# Generated by FakeRAM 2.0
VERSION 5.7 ;
BUSBITCHARS "[]" ;
PROPERTYDEFINITIONS
  MACRO width INTEGER ;
  MACRO depth INTEGER ;
  MACRO banks INTEGER ;
END PROPERTYDEFINITIONS
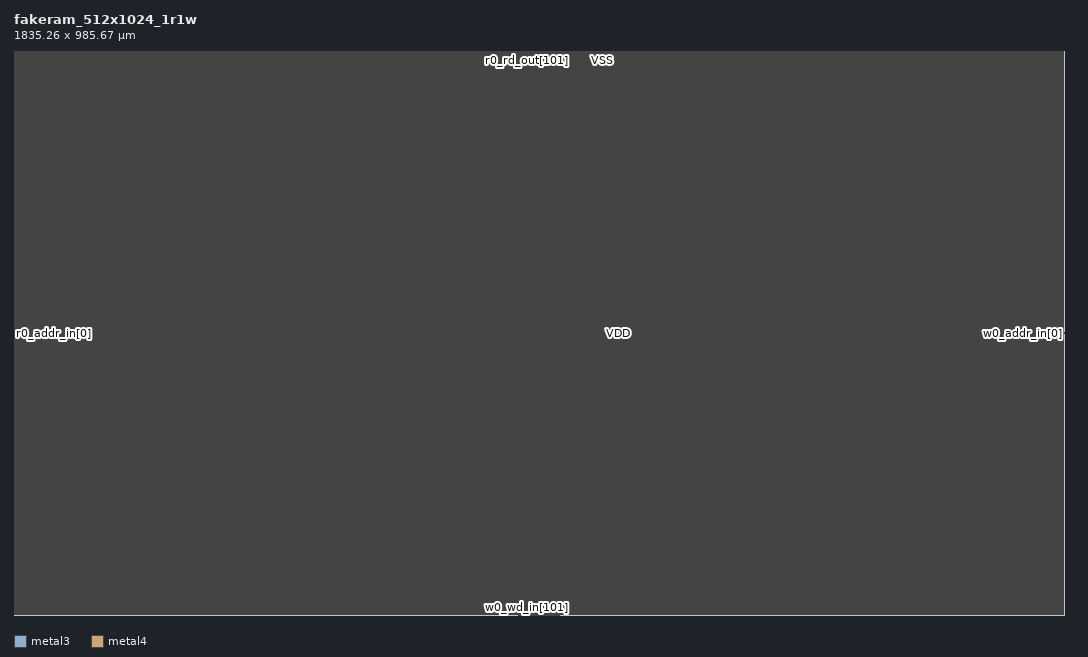
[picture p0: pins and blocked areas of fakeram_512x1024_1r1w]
MACRO fakeram_512x1024_1r1w
  PROPERTY width 512 ;
  PROPERTY depth 1024 ;
  PROPERTY banks 1 ;
  FOREIGN fakeram_512x1024_1r1w 0 0 ;
  SYMMETRY X Y R90 ;
  SIZE 1835.260 BY 985.670 ;
  CLASS BLOCK ;
  PIN r0_addr_in[0]
    DIRECTION INPUT ;
    USE SIGNAL ;
    SHAPE ABUTMENT ;
    PORT
      LAYER metal3 ;
      RECT 0.000 491.820 0.070 491.890 ;
    END
  END r0_addr_in[0]
  PIN r0_addr_in[1]
    DIRECTION INPUT ;
    USE SIGNAL ;
    SHAPE ABUTMENT ;
    PORT
      LAYER metal3 ;
      RECT 0.000 491.960 0.070 492.030 ;
    END
  END r0_addr_in[1]
  PIN r0_addr_in[2]
    DIRECTION INPUT ;
    USE SIGNAL ;
    SHAPE ABUTMENT ;
    PORT
      LAYER metal3 ;
      RECT 0.000 492.100 0.070 492.170 ;
    END
  END r0_addr_in[2]
  PIN r0_addr_in[3]
    DIRECTION INPUT ;
    USE SIGNAL ;
    SHAPE ABUTMENT ;
    PORT
      LAYER metal3 ;
      RECT 0.000 492.240 0.070 492.310 ;
    END
  END r0_addr_in[3]
  PIN r0_addr_in[4]
    DIRECTION INPUT ;
    USE SIGNAL ;
    SHAPE ABUTMENT ;
    PORT
      LAYER metal3 ;
      RECT 0.000 492.380 0.070 492.450 ;
    END
  END r0_addr_in[4]
  PIN r0_addr_in[5]
    DIRECTION INPUT ;
    USE SIGNAL ;
    SHAPE ABUTMENT ;
    PORT
      LAYER metal3 ;
      RECT 0.000 492.520 0.070 492.590 ;
    END
  END r0_addr_in[5]
  PIN r0_addr_in[6]
    DIRECTION INPUT ;
    USE SIGNAL ;
    SHAPE ABUTMENT ;
    PORT
      LAYER metal3 ;
      RECT 0.000 492.660 0.070 492.730 ;
    END
  END r0_addr_in[6]
  PIN r0_addr_in[7]
    DIRECTION INPUT ;
    USE SIGNAL ;
    SHAPE ABUTMENT ;
    PORT
      LAYER metal3 ;
      RECT 0.000 492.800 0.070 492.870 ;
    END
  END r0_addr_in[7]
  PIN r0_addr_in[8]
    DIRECTION INPUT ;
    USE SIGNAL ;
    SHAPE ABUTMENT ;
    PORT
      LAYER metal3 ;
      RECT 0.000 492.940 0.070 493.010 ;
    END
  END r0_addr_in[8]
  PIN r0_addr_in[9]
    DIRECTION INPUT ;
    USE SIGNAL ;
    SHAPE ABUTMENT ;
    PORT
      LAYER metal3 ;
      RECT 0.000 493.080 0.070 493.150 ;
    END
  END r0_addr_in[9]
  PIN r0_ce_in
    DIRECTION INPUT ;
    USE SIGNAL ;
    SHAPE ABUTMENT ;
    PORT
      LAYER metal3 ;
      RECT 0.000 493.360 0.070 493.430 ;
    END
  END r0_ce_in
  PIN r0_clk
    DIRECTION INPUT ;
    USE SIGNAL ;
    SHAPE ABUTMENT ;
    PORT
      LAYER metal3 ;
      RECT 0.000 493.500 0.070 493.570 ;
    END
  END r0_clk
  PIN r0_rd_out[0]
    DIRECTION OUTPUT ;
    USE SIGNAL ;
    SHAPE ABUTMENT ;
    PORT
      LAYER metal3 ;
      RECT 881.685 985.600 881.755 985.670 ;
    END
  END r0_rd_out[0]
  PIN r0_rd_out[1]
    DIRECTION OUTPUT ;
    USE SIGNAL ;
    SHAPE ABUTMENT ;
    PORT
      LAYER metal3 ;
      RECT 881.825 985.600 881.895 985.670 ;
    END
  END r0_rd_out[1]
  PIN r0_rd_out[2]
    DIRECTION OUTPUT ;
    USE SIGNAL ;
    SHAPE ABUTMENT ;
    PORT
      LAYER metal3 ;
      RECT 881.965 985.600 882.035 985.670 ;
    END
  END r0_rd_out[2]
  PIN r0_rd_out[3]
    DIRECTION OUTPUT ;
    USE SIGNAL ;
    SHAPE ABUTMENT ;
    PORT
      LAYER metal3 ;
      RECT 882.105 985.600 882.175 985.670 ;
    END
  END r0_rd_out[3]
  PIN r0_rd_out[4]
    DIRECTION OUTPUT ;
    USE SIGNAL ;
    SHAPE ABUTMENT ;
    PORT
      LAYER metal3 ;
      RECT 882.245 985.600 882.315 985.670 ;
    END
  END r0_rd_out[4]
  PIN r0_rd_out[5]
    DIRECTION OUTPUT ;
    USE SIGNAL ;
    SHAPE ABUTMENT ;
    PORT
      LAYER metal3 ;
      RECT 882.385 985.600 882.455 985.670 ;
    END
  END r0_rd_out[5]
  PIN r0_rd_out[6]
    DIRECTION OUTPUT ;
    USE SIGNAL ;
    SHAPE ABUTMENT ;
    PORT
      LAYER metal3 ;
      RECT 882.525 985.600 882.595 985.670 ;
    END
  END r0_rd_out[6]
  PIN r0_rd_out[7]
    DIRECTION OUTPUT ;
    USE SIGNAL ;
    SHAPE ABUTMENT ;
    PORT
      LAYER metal3 ;
      RECT 882.665 985.600 882.735 985.670 ;
    END
  END r0_rd_out[7]
  PIN r0_rd_out[8]
    DIRECTION OUTPUT ;
    USE SIGNAL ;
    SHAPE ABUTMENT ;
    PORT
      LAYER metal3 ;
      RECT 882.805 985.600 882.875 985.670 ;
    END
  END r0_rd_out[8]
  PIN r0_rd_out[9]
    DIRECTION OUTPUT ;
    USE SIGNAL ;
    SHAPE ABUTMENT ;
    PORT
      LAYER metal3 ;
      RECT 882.945 985.600 883.015 985.670 ;
    END
  END r0_rd_out[9]
  PIN r0_rd_out[10]
    DIRECTION OUTPUT ;
    USE SIGNAL ;
    SHAPE ABUTMENT ;
    PORT
      LAYER metal3 ;
      RECT 883.085 985.600 883.155 985.670 ;
    END
  END r0_rd_out[10]
  PIN r0_rd_out[11]
    DIRECTION OUTPUT ;
    USE SIGNAL ;
    SHAPE ABUTMENT ;
    PORT
      LAYER metal3 ;
      RECT 883.225 985.600 883.295 985.670 ;
    END
  END r0_rd_out[11]
  PIN r0_rd_out[12]
    DIRECTION OUTPUT ;
    USE SIGNAL ;
    SHAPE ABUTMENT ;
    PORT
      LAYER metal3 ;
      RECT 883.365 985.600 883.435 985.670 ;
    END
  END r0_rd_out[12]
  PIN r0_rd_out[13]
    DIRECTION OUTPUT ;
    USE SIGNAL ;
    SHAPE ABUTMENT ;
    PORT
      LAYER metal3 ;
      RECT 883.505 985.600 883.575 985.670 ;
    END
  END r0_rd_out[13]
  PIN r0_rd_out[14]
    DIRECTION OUTPUT ;
    USE SIGNAL ;
    SHAPE ABUTMENT ;
    PORT
      LAYER metal3 ;
      RECT 883.645 985.600 883.715 985.670 ;
    END
  END r0_rd_out[14]
  PIN r0_rd_out[15]
    DIRECTION OUTPUT ;
    USE SIGNAL ;
    SHAPE ABUTMENT ;
    PORT
      LAYER metal3 ;
      RECT 883.785 985.600 883.855 985.670 ;
    END
  END r0_rd_out[15]
  PIN r0_rd_out[16]
    DIRECTION OUTPUT ;
    USE SIGNAL ;
    SHAPE ABUTMENT ;
    PORT
      LAYER metal3 ;
      RECT 883.925 985.600 883.995 985.670 ;
    END
  END r0_rd_out[16]
  PIN r0_rd_out[17]
    DIRECTION OUTPUT ;
    USE SIGNAL ;
    SHAPE ABUTMENT ;
    PORT
      LAYER metal3 ;
      RECT 884.065 985.600 884.135 985.670 ;
    END
  END r0_rd_out[17]
  PIN r0_rd_out[18]
    DIRECTION OUTPUT ;
    USE SIGNAL ;
    SHAPE ABUTMENT ;
    PORT
      LAYER metal3 ;
      RECT 884.205 985.600 884.275 985.670 ;
    END
  END r0_rd_out[18]
  PIN r0_rd_out[19]
    DIRECTION OUTPUT ;
    USE SIGNAL ;
    SHAPE ABUTMENT ;
    PORT
      LAYER metal3 ;
      RECT 884.345 985.600 884.415 985.670 ;
    END
  END r0_rd_out[19]
  PIN r0_rd_out[20]
    DIRECTION OUTPUT ;
    USE SIGNAL ;
    SHAPE ABUTMENT ;
    PORT
      LAYER metal3 ;
      RECT 884.485 985.600 884.555 985.670 ;
    END
  END r0_rd_out[20]
  PIN r0_rd_out[21]
    DIRECTION OUTPUT ;
    USE SIGNAL ;
    SHAPE ABUTMENT ;
    PORT
      LAYER metal3 ;
      RECT 884.625 985.600 884.695 985.670 ;
    END
  END r0_rd_out[21]
  PIN r0_rd_out[22]
    DIRECTION OUTPUT ;
    USE SIGNAL ;
    SHAPE ABUTMENT ;
    PORT
      LAYER metal3 ;
      RECT 884.765 985.600 884.835 985.670 ;
    END
  END r0_rd_out[22]
  PIN r0_rd_out[23]
    DIRECTION OUTPUT ;
    USE SIGNAL ;
    SHAPE ABUTMENT ;
    PORT
      LAYER metal3 ;
      RECT 884.905 985.600 884.975 985.670 ;
    END
  END r0_rd_out[23]
  PIN r0_rd_out[24]
    DIRECTION OUTPUT ;
    USE SIGNAL ;
    SHAPE ABUTMENT ;
    PORT
      LAYER metal3 ;
      RECT 885.045 985.600 885.115 985.670 ;
    END
  END r0_rd_out[24]
  PIN r0_rd_out[25]
    DIRECTION OUTPUT ;
    USE SIGNAL ;
    SHAPE ABUTMENT ;
    PORT
      LAYER metal3 ;
      RECT 885.185 985.600 885.255 985.670 ;
    END
  END r0_rd_out[25]
  PIN r0_rd_out[26]
    DIRECTION OUTPUT ;
    USE SIGNAL ;
    SHAPE ABUTMENT ;
    PORT
      LAYER metal3 ;
      RECT 885.325 985.600 885.395 985.670 ;
    END
  END r0_rd_out[26]
  PIN r0_rd_out[27]
    DIRECTION OUTPUT ;
    USE SIGNAL ;
    SHAPE ABUTMENT ;
    PORT
      LAYER metal3 ;
      RECT 885.465 985.600 885.535 985.670 ;
    END
  END r0_rd_out[27]
  PIN r0_rd_out[28]
    DIRECTION OUTPUT ;
    USE SIGNAL ;
    SHAPE ABUTMENT ;
    PORT
      LAYER metal3 ;
      RECT 885.605 985.600 885.675 985.670 ;
    END
  END r0_rd_out[28]
  PIN r0_rd_out[29]
    DIRECTION OUTPUT ;
    USE SIGNAL ;
    SHAPE ABUTMENT ;
    PORT
      LAYER metal3 ;
      RECT 885.745 985.600 885.815 985.670 ;
    END
  END r0_rd_out[29]
  PIN r0_rd_out[30]
    DIRECTION OUTPUT ;
    USE SIGNAL ;
    SHAPE ABUTMENT ;
    PORT
      LAYER metal3 ;
      RECT 885.885 985.600 885.955 985.670 ;
    END
  END r0_rd_out[30]
  PIN r0_rd_out[31]
    DIRECTION OUTPUT ;
    USE SIGNAL ;
    SHAPE ABUTMENT ;
    PORT
      LAYER metal3 ;
      RECT 886.025 985.600 886.095 985.670 ;
    END
  END r0_rd_out[31]
  PIN r0_rd_out[32]
    DIRECTION OUTPUT ;
    USE SIGNAL ;
    SHAPE ABUTMENT ;
    PORT
      LAYER metal3 ;
      RECT 886.165 985.600 886.235 985.670 ;
    END
  END r0_rd_out[32]
  PIN r0_rd_out[33]
    DIRECTION OUTPUT ;
    USE SIGNAL ;
    SHAPE ABUTMENT ;
    PORT
      LAYER metal3 ;
      RECT 886.305 985.600 886.375 985.670 ;
    END
  END r0_rd_out[33]
  PIN r0_rd_out[34]
    DIRECTION OUTPUT ;
    USE SIGNAL ;
    SHAPE ABUTMENT ;
    PORT
      LAYER metal3 ;
      RECT 886.445 985.600 886.515 985.670 ;
    END
  END r0_rd_out[34]
  PIN r0_rd_out[35]
    DIRECTION OUTPUT ;
    USE SIGNAL ;
    SHAPE ABUTMENT ;
    PORT
      LAYER metal3 ;
      RECT 886.585 985.600 886.655 985.670 ;
    END
  END r0_rd_out[35]
  PIN r0_rd_out[36]
    DIRECTION OUTPUT ;
    USE SIGNAL ;
    SHAPE ABUTMENT ;
    PORT
      LAYER metal3 ;
      RECT 886.725 985.600 886.795 985.670 ;
    END
  END r0_rd_out[36]
  PIN r0_rd_out[37]
    DIRECTION OUTPUT ;
    USE SIGNAL ;
    SHAPE ABUTMENT ;
    PORT
      LAYER metal3 ;
      RECT 886.865 985.600 886.935 985.670 ;
    END
  END r0_rd_out[37]
  PIN r0_rd_out[38]
    DIRECTION OUTPUT ;
    USE SIGNAL ;
    SHAPE ABUTMENT ;
    PORT
      LAYER metal3 ;
      RECT 887.005 985.600 887.075 985.670 ;
    END
  END r0_rd_out[38]
  PIN r0_rd_out[39]
    DIRECTION OUTPUT ;
    USE SIGNAL ;
    SHAPE ABUTMENT ;
    PORT
      LAYER metal3 ;
      RECT 887.145 985.600 887.215 985.670 ;
    END
  END r0_rd_out[39]
  PIN r0_rd_out[40]
    DIRECTION OUTPUT ;
    USE SIGNAL ;
    SHAPE ABUTMENT ;
    PORT
      LAYER metal3 ;
      RECT 887.285 985.600 887.355 985.670 ;
    END
  END r0_rd_out[40]
  PIN r0_rd_out[41]
    DIRECTION OUTPUT ;
    USE SIGNAL ;
    SHAPE ABUTMENT ;
    PORT
      LAYER metal3 ;
      RECT 887.425 985.600 887.495 985.670 ;
    END
  END r0_rd_out[41]
  PIN r0_rd_out[42]
    DIRECTION OUTPUT ;
    USE SIGNAL ;
    SHAPE ABUTMENT ;
    PORT
      LAYER metal3 ;
      RECT 887.565 985.600 887.635 985.670 ;
    END
  END r0_rd_out[42]
  PIN r0_rd_out[43]
    DIRECTION OUTPUT ;
    USE SIGNAL ;
    SHAPE ABUTMENT ;
    PORT
      LAYER metal3 ;
      RECT 887.705 985.600 887.775 985.670 ;
    END
  END r0_rd_out[43]
  PIN r0_rd_out[44]
    DIRECTION OUTPUT ;
    USE SIGNAL ;
    SHAPE ABUTMENT ;
    PORT
      LAYER metal3 ;
      RECT 887.845 985.600 887.915 985.670 ;
    END
  END r0_rd_out[44]
  PIN r0_rd_out[45]
    DIRECTION OUTPUT ;
    USE SIGNAL ;
    SHAPE ABUTMENT ;
    PORT
      LAYER metal3 ;
      RECT 887.985 985.600 888.055 985.670 ;
    END
  END r0_rd_out[45]
  PIN r0_rd_out[46]
    DIRECTION OUTPUT ;
    USE SIGNAL ;
    SHAPE ABUTMENT ;
    PORT
      LAYER metal3 ;
      RECT 888.125 985.600 888.195 985.670 ;
    END
  END r0_rd_out[46]
  PIN r0_rd_out[47]
    DIRECTION OUTPUT ;
    USE SIGNAL ;
    SHAPE ABUTMENT ;
    PORT
      LAYER metal3 ;
      RECT 888.265 985.600 888.335 985.670 ;
    END
  END r0_rd_out[47]
  PIN r0_rd_out[48]
    DIRECTION OUTPUT ;
    USE SIGNAL ;
    SHAPE ABUTMENT ;
    PORT
      LAYER metal3 ;
      RECT 888.405 985.600 888.475 985.670 ;
    END
  END r0_rd_out[48]
  PIN r0_rd_out[49]
    DIRECTION OUTPUT ;
    USE SIGNAL ;
    SHAPE ABUTMENT ;
    PORT
      LAYER metal3 ;
      RECT 888.545 985.600 888.615 985.670 ;
    END
  END r0_rd_out[49]
  PIN r0_rd_out[50]
    DIRECTION OUTPUT ;
    USE SIGNAL ;
    SHAPE ABUTMENT ;
    PORT
      LAYER metal3 ;
      RECT 888.685 985.600 888.755 985.670 ;
    END
  END r0_rd_out[50]
  PIN r0_rd_out[51]
    DIRECTION OUTPUT ;
    USE SIGNAL ;
    SHAPE ABUTMENT ;
    PORT
      LAYER metal3 ;
      RECT 888.825 985.600 888.895 985.670 ;
    END
  END r0_rd_out[51]
  PIN r0_rd_out[52]
    DIRECTION OUTPUT ;
    USE SIGNAL ;
    SHAPE ABUTMENT ;
    PORT
      LAYER metal3 ;
      RECT 888.965 985.600 889.035 985.670 ;
    END
  END r0_rd_out[52]
  PIN r0_rd_out[53]
    DIRECTION OUTPUT ;
    USE SIGNAL ;
    SHAPE ABUTMENT ;
    PORT
      LAYER metal3 ;
      RECT 889.105 985.600 889.175 985.670 ;
    END
  END r0_rd_out[53]
  PIN r0_rd_out[54]
    DIRECTION OUTPUT ;
    USE SIGNAL ;
    SHAPE ABUTMENT ;
    PORT
      LAYER metal3 ;
      RECT 889.245 985.600 889.315 985.670 ;
    END
  END r0_rd_out[54]
  PIN r0_rd_out[55]
    DIRECTION OUTPUT ;
    USE SIGNAL ;
    SHAPE ABUTMENT ;
    PORT
      LAYER metal3 ;
      RECT 889.385 985.600 889.455 985.670 ;
    END
  END r0_rd_out[55]
  PIN r0_rd_out[56]
    DIRECTION OUTPUT ;
    USE SIGNAL ;
    SHAPE ABUTMENT ;
    PORT
      LAYER metal3 ;
      RECT 889.525 985.600 889.595 985.670 ;
    END
  END r0_rd_out[56]
  PIN r0_rd_out[57]
    DIRECTION OUTPUT ;
    USE SIGNAL ;
    SHAPE ABUTMENT ;
    PORT
      LAYER metal3 ;
      RECT 889.665 985.600 889.735 985.670 ;
    END
  END r0_rd_out[57]
  PIN r0_rd_out[58]
    DIRECTION OUTPUT ;
    USE SIGNAL ;
    SHAPE ABUTMENT ;
    PORT
      LAYER metal3 ;
      RECT 889.805 985.600 889.875 985.670 ;
    END
  END r0_rd_out[58]
  PIN r0_rd_out[59]
    DIRECTION OUTPUT ;
    USE SIGNAL ;
    SHAPE ABUTMENT ;
    PORT
      LAYER metal3 ;
      RECT 889.945 985.600 890.015 985.670 ;
    END
  END r0_rd_out[59]
  PIN r0_rd_out[60]
    DIRECTION OUTPUT ;
    USE SIGNAL ;
    SHAPE ABUTMENT ;
    PORT
      LAYER metal3 ;
      RECT 890.085 985.600 890.155 985.670 ;
    END
  END r0_rd_out[60]
  PIN r0_rd_out[61]
    DIRECTION OUTPUT ;
    USE SIGNAL ;
    SHAPE ABUTMENT ;
    PORT
      LAYER metal3 ;
      RECT 890.225 985.600 890.295 985.670 ;
    END
  END r0_rd_out[61]
  PIN r0_rd_out[62]
    DIRECTION OUTPUT ;
    USE SIGNAL ;
    SHAPE ABUTMENT ;
    PORT
      LAYER metal3 ;
      RECT 890.365 985.600 890.435 985.670 ;
    END
  END r0_rd_out[62]
  PIN r0_rd_out[63]
    DIRECTION OUTPUT ;
    USE SIGNAL ;
    SHAPE ABUTMENT ;
    PORT
      LAYER metal3 ;
      RECT 890.505 985.600 890.575 985.670 ;
    END
  END r0_rd_out[63]
  PIN r0_rd_out[64]
    DIRECTION OUTPUT ;
    USE SIGNAL ;
    SHAPE ABUTMENT ;
    PORT
      LAYER metal3 ;
      RECT 890.645 985.600 890.715 985.670 ;
    END
  END r0_rd_out[64]
  PIN r0_rd_out[65]
    DIRECTION OUTPUT ;
    USE SIGNAL ;
    SHAPE ABUTMENT ;
    PORT
      LAYER metal3 ;
      RECT 890.785 985.600 890.855 985.670 ;
    END
  END r0_rd_out[65]
  PIN r0_rd_out[66]
    DIRECTION OUTPUT ;
    USE SIGNAL ;
    SHAPE ABUTMENT ;
    PORT
      LAYER metal3 ;
      RECT 890.925 985.600 890.995 985.670 ;
    END
  END r0_rd_out[66]
  PIN r0_rd_out[67]
    DIRECTION OUTPUT ;
    USE SIGNAL ;
    SHAPE ABUTMENT ;
    PORT
      LAYER metal3 ;
      RECT 891.065 985.600 891.135 985.670 ;
    END
  END r0_rd_out[67]
  PIN r0_rd_out[68]
    DIRECTION OUTPUT ;
    USE SIGNAL ;
    SHAPE ABUTMENT ;
    PORT
      LAYER metal3 ;
      RECT 891.205 985.600 891.275 985.670 ;
    END
  END r0_rd_out[68]
  PIN r0_rd_out[69]
    DIRECTION OUTPUT ;
    USE SIGNAL ;
    SHAPE ABUTMENT ;
    PORT
      LAYER metal3 ;
      RECT 891.345 985.600 891.415 985.670 ;
    END
  END r0_rd_out[69]
  PIN r0_rd_out[70]
    DIRECTION OUTPUT ;
    USE SIGNAL ;
    SHAPE ABUTMENT ;
    PORT
      LAYER metal3 ;
      RECT 891.485 985.600 891.555 985.670 ;
    END
  END r0_rd_out[70]
  PIN r0_rd_out[71]
    DIRECTION OUTPUT ;
    USE SIGNAL ;
    SHAPE ABUTMENT ;
    PORT
      LAYER metal3 ;
      RECT 891.625 985.600 891.695 985.670 ;
    END
  END r0_rd_out[71]
  PIN r0_rd_out[72]
    DIRECTION OUTPUT ;
    USE SIGNAL ;
    SHAPE ABUTMENT ;
    PORT
      LAYER metal3 ;
      RECT 891.765 985.600 891.835 985.670 ;
    END
  END r0_rd_out[72]
  PIN r0_rd_out[73]
    DIRECTION OUTPUT ;
    USE SIGNAL ;
    SHAPE ABUTMENT ;
    PORT
      LAYER metal3 ;
      RECT 891.905 985.600 891.975 985.670 ;
    END
  END r0_rd_out[73]
  PIN r0_rd_out[74]
    DIRECTION OUTPUT ;
    USE SIGNAL ;
    SHAPE ABUTMENT ;
    PORT
      LAYER metal3 ;
      RECT 892.045 985.600 892.115 985.670 ;
    END
  END r0_rd_out[74]
  PIN r0_rd_out[75]
    DIRECTION OUTPUT ;
    USE SIGNAL ;
    SHAPE ABUTMENT ;
    PORT
      LAYER metal3 ;
      RECT 892.185 985.600 892.255 985.670 ;
    END
  END r0_rd_out[75]
  PIN r0_rd_out[76]
    DIRECTION OUTPUT ;
    USE SIGNAL ;
    SHAPE ABUTMENT ;
    PORT
      LAYER metal3 ;
      RECT 892.325 985.600 892.395 985.670 ;
    END
  END r0_rd_out[76]
  PIN r0_rd_out[77]
    DIRECTION OUTPUT ;
    USE SIGNAL ;
    SHAPE ABUTMENT ;
    PORT
      LAYER metal3 ;
      RECT 892.465 985.600 892.535 985.670 ;
    END
  END r0_rd_out[77]
  PIN r0_rd_out[78]
    DIRECTION OUTPUT ;
    USE SIGNAL ;
    SHAPE ABUTMENT ;
    PORT
      LAYER metal3 ;
      RECT 892.605 985.600 892.675 985.670 ;
    END
  END r0_rd_out[78]
  PIN r0_rd_out[79]
    DIRECTION OUTPUT ;
    USE SIGNAL ;
    SHAPE ABUTMENT ;
    PORT
      LAYER metal3 ;
      RECT 892.745 985.600 892.815 985.670 ;
    END
  END r0_rd_out[79]
  PIN r0_rd_out[80]
    DIRECTION OUTPUT ;
    USE SIGNAL ;
    SHAPE ABUTMENT ;
    PORT
      LAYER metal3 ;
      RECT 892.885 985.600 892.955 985.670 ;
    END
  END r0_rd_out[80]
  PIN r0_rd_out[81]
    DIRECTION OUTPUT ;
    USE SIGNAL ;
    SHAPE ABUTMENT ;
    PORT
      LAYER metal3 ;
      RECT 893.025 985.600 893.095 985.670 ;
    END
  END r0_rd_out[81]
  PIN r0_rd_out[82]
    DIRECTION OUTPUT ;
    USE SIGNAL ;
    SHAPE ABUTMENT ;
    PORT
      LAYER metal3 ;
      RECT 893.165 985.600 893.235 985.670 ;
    END
  END r0_rd_out[82]
  PIN r0_rd_out[83]
    DIRECTION OUTPUT ;
    USE SIGNAL ;
    SHAPE ABUTMENT ;
    PORT
      LAYER metal3 ;
      RECT 893.305 985.600 893.375 985.670 ;
    END
  END r0_rd_out[83]
  PIN r0_rd_out[84]
    DIRECTION OUTPUT ;
    USE SIGNAL ;
    SHAPE ABUTMENT ;
    PORT
      LAYER metal3 ;
      RECT 893.445 985.600 893.515 985.670 ;
    END
  END r0_rd_out[84]
  PIN r0_rd_out[85]
    DIRECTION OUTPUT ;
    USE SIGNAL ;
    SHAPE ABUTMENT ;
    PORT
      LAYER metal3 ;
      RECT 893.585 985.600 893.655 985.670 ;
    END
  END r0_rd_out[85]
  PIN r0_rd_out[86]
    DIRECTION OUTPUT ;
    USE SIGNAL ;
    SHAPE ABUTMENT ;
    PORT
      LAYER metal3 ;
      RECT 893.725 985.600 893.795 985.670 ;
    END
  END r0_rd_out[86]
  PIN r0_rd_out[87]
    DIRECTION OUTPUT ;
    USE SIGNAL ;
    SHAPE ABUTMENT ;
    PORT
      LAYER metal3 ;
      RECT 893.865 985.600 893.935 985.670 ;
    END
  END r0_rd_out[87]
  PIN r0_rd_out[88]
    DIRECTION OUTPUT ;
    USE SIGNAL ;
    SHAPE ABUTMENT ;
    PORT
      LAYER metal3 ;
      RECT 894.005 985.600 894.075 985.670 ;
    END
  END r0_rd_out[88]
  PIN r0_rd_out[89]
    DIRECTION OUTPUT ;
    USE SIGNAL ;
    SHAPE ABUTMENT ;
    PORT
      LAYER metal3 ;
      RECT 894.145 985.600 894.215 985.670 ;
    END
  END r0_rd_out[89]
  PIN r0_rd_out[90]
    DIRECTION OUTPUT ;
    USE SIGNAL ;
    SHAPE ABUTMENT ;
    PORT
      LAYER metal3 ;
      RECT 894.285 985.600 894.355 985.670 ;
    END
  END r0_rd_out[90]
  PIN r0_rd_out[91]
    DIRECTION OUTPUT ;
    USE SIGNAL ;
    SHAPE ABUTMENT ;
    PORT
      LAYER metal3 ;
      RECT 894.425 985.600 894.495 985.670 ;
    END
  END r0_rd_out[91]
  PIN r0_rd_out[92]
    DIRECTION OUTPUT ;
    USE SIGNAL ;
    SHAPE ABUTMENT ;
    PORT
      LAYER metal3 ;
      RECT 894.565 985.600 894.635 985.670 ;
    END
  END r0_rd_out[92]
  PIN r0_rd_out[93]
    DIRECTION OUTPUT ;
    USE SIGNAL ;
    SHAPE ABUTMENT ;
    PORT
      LAYER metal3 ;
      RECT 894.705 985.600 894.775 985.670 ;
    END
  END r0_rd_out[93]
  PIN r0_rd_out[94]
    DIRECTION OUTPUT ;
    USE SIGNAL ;
    SHAPE ABUTMENT ;
    PORT
      LAYER metal3 ;
      RECT 894.845 985.600 894.915 985.670 ;
    END
  END r0_rd_out[94]
  PIN r0_rd_out[95]
    DIRECTION OUTPUT ;
    USE SIGNAL ;
    SHAPE ABUTMENT ;
    PORT
      LAYER metal3 ;
      RECT 894.985 985.600 895.055 985.670 ;
    END
  END r0_rd_out[95]
  PIN r0_rd_out[96]
    DIRECTION OUTPUT ;
    USE SIGNAL ;
    SHAPE ABUTMENT ;
    PORT
      LAYER metal3 ;
      RECT 895.125 985.600 895.195 985.670 ;
    END
  END r0_rd_out[96]
  PIN r0_rd_out[97]
    DIRECTION OUTPUT ;
    USE SIGNAL ;
    SHAPE ABUTMENT ;
    PORT
      LAYER metal3 ;
      RECT 895.265 985.600 895.335 985.670 ;
    END
  END r0_rd_out[97]
  PIN r0_rd_out[98]
    DIRECTION OUTPUT ;
    USE SIGNAL ;
    SHAPE ABUTMENT ;
    PORT
      LAYER metal3 ;
      RECT 895.405 985.600 895.475 985.670 ;
    END
  END r0_rd_out[98]
  PIN r0_rd_out[99]
    DIRECTION OUTPUT ;
    USE SIGNAL ;
    SHAPE ABUTMENT ;
    PORT
      LAYER metal3 ;
      RECT 895.545 985.600 895.615 985.670 ;
    END
  END r0_rd_out[99]
  PIN r0_rd_out[100]
    DIRECTION OUTPUT ;
    USE SIGNAL ;
    SHAPE ABUTMENT ;
    PORT
      LAYER metal3 ;
      RECT 895.685 985.600 895.755 985.670 ;
    END
  END r0_rd_out[100]
  PIN r0_rd_out[101]
    DIRECTION OUTPUT ;
    USE SIGNAL ;
    SHAPE ABUTMENT ;
    PORT
      LAYER metal3 ;
      RECT 895.825 985.600 895.895 985.670 ;
    END
  END r0_rd_out[101]
  PIN r0_rd_out[102]
    DIRECTION OUTPUT ;
    USE SIGNAL ;
    SHAPE ABUTMENT ;
    PORT
      LAYER metal3 ;
      RECT 895.965 985.600 896.035 985.670 ;
    END
  END r0_rd_out[102]
  PIN r0_rd_out[103]
    DIRECTION OUTPUT ;
    USE SIGNAL ;
    SHAPE ABUTMENT ;
    PORT
      LAYER metal3 ;
      RECT 896.105 985.600 896.175 985.670 ;
    END
  END r0_rd_out[103]
  PIN r0_rd_out[104]
    DIRECTION OUTPUT ;
    USE SIGNAL ;
    SHAPE ABUTMENT ;
    PORT
      LAYER metal3 ;
      RECT 896.245 985.600 896.315 985.670 ;
    END
  END r0_rd_out[104]
  PIN r0_rd_out[105]
    DIRECTION OUTPUT ;
    USE SIGNAL ;
    SHAPE ABUTMENT ;
    PORT
      LAYER metal3 ;
      RECT 896.385 985.600 896.455 985.670 ;
    END
  END r0_rd_out[105]
  PIN r0_rd_out[106]
    DIRECTION OUTPUT ;
    USE SIGNAL ;
    SHAPE ABUTMENT ;
    PORT
      LAYER metal3 ;
      RECT 896.525 985.600 896.595 985.670 ;
    END
  END r0_rd_out[106]
  PIN r0_rd_out[107]
    DIRECTION OUTPUT ;
    USE SIGNAL ;
    SHAPE ABUTMENT ;
    PORT
      LAYER metal3 ;
      RECT 896.665 985.600 896.735 985.670 ;
    END
  END r0_rd_out[107]
  PIN r0_rd_out[108]
    DIRECTION OUTPUT ;
    USE SIGNAL ;
    SHAPE ABUTMENT ;
    PORT
      LAYER metal3 ;
      RECT 896.805 985.600 896.875 985.670 ;
    END
  END r0_rd_out[108]
  PIN r0_rd_out[109]
    DIRECTION OUTPUT ;
    USE SIGNAL ;
    SHAPE ABUTMENT ;
    PORT
      LAYER metal3 ;
      RECT 896.945 985.600 897.015 985.670 ;
    END
  END r0_rd_out[109]
  PIN r0_rd_out[110]
    DIRECTION OUTPUT ;
    USE SIGNAL ;
    SHAPE ABUTMENT ;
    PORT
      LAYER metal3 ;
      RECT 897.085 985.600 897.155 985.670 ;
    END
  END r0_rd_out[110]
  PIN r0_rd_out[111]
    DIRECTION OUTPUT ;
    USE SIGNAL ;
    SHAPE ABUTMENT ;
    PORT
      LAYER metal3 ;
      RECT 897.225 985.600 897.295 985.670 ;
    END
  END r0_rd_out[111]
  PIN r0_rd_out[112]
    DIRECTION OUTPUT ;
    USE SIGNAL ;
    SHAPE ABUTMENT ;
    PORT
      LAYER metal3 ;
      RECT 897.365 985.600 897.435 985.670 ;
    END
  END r0_rd_out[112]
  PIN r0_rd_out[113]
    DIRECTION OUTPUT ;
    USE SIGNAL ;
    SHAPE ABUTMENT ;
    PORT
      LAYER metal3 ;
      RECT 897.505 985.600 897.575 985.670 ;
    END
  END r0_rd_out[113]
  PIN r0_rd_out[114]
    DIRECTION OUTPUT ;
    USE SIGNAL ;
    SHAPE ABUTMENT ;
    PORT
      LAYER metal3 ;
      RECT 897.645 985.600 897.715 985.670 ;
    END
  END r0_rd_out[114]
  PIN r0_rd_out[115]
    DIRECTION OUTPUT ;
    USE SIGNAL ;
    SHAPE ABUTMENT ;
    PORT
      LAYER metal3 ;
      RECT 897.785 985.600 897.855 985.670 ;
    END
  END r0_rd_out[115]
  PIN r0_rd_out[116]
    DIRECTION OUTPUT ;
    USE SIGNAL ;
    SHAPE ABUTMENT ;
    PORT
      LAYER metal3 ;
      RECT 897.925 985.600 897.995 985.670 ;
    END
  END r0_rd_out[116]
  PIN r0_rd_out[117]
    DIRECTION OUTPUT ;
    USE SIGNAL ;
    SHAPE ABUTMENT ;
    PORT
      LAYER metal3 ;
      RECT 898.065 985.600 898.135 985.670 ;
    END
  END r0_rd_out[117]
  PIN r0_rd_out[118]
    DIRECTION OUTPUT ;
    USE SIGNAL ;
    SHAPE ABUTMENT ;
    PORT
      LAYER metal3 ;
      RECT 898.205 985.600 898.275 985.670 ;
    END
  END r0_rd_out[118]
  PIN r0_rd_out[119]
    DIRECTION OUTPUT ;
    USE SIGNAL ;
    SHAPE ABUTMENT ;
    PORT
      LAYER metal3 ;
      RECT 898.345 985.600 898.415 985.670 ;
    END
  END r0_rd_out[119]
  PIN r0_rd_out[120]
    DIRECTION OUTPUT ;
    USE SIGNAL ;
    SHAPE ABUTMENT ;
    PORT
      LAYER metal3 ;
      RECT 898.485 985.600 898.555 985.670 ;
    END
  END r0_rd_out[120]
  PIN r0_rd_out[121]
    DIRECTION OUTPUT ;
    USE SIGNAL ;
    SHAPE ABUTMENT ;
    PORT
      LAYER metal3 ;
      RECT 898.625 985.600 898.695 985.670 ;
    END
  END r0_rd_out[121]
  PIN r0_rd_out[122]
    DIRECTION OUTPUT ;
    USE SIGNAL ;
    SHAPE ABUTMENT ;
    PORT
      LAYER metal3 ;
      RECT 898.765 985.600 898.835 985.670 ;
    END
  END r0_rd_out[122]
  PIN r0_rd_out[123]
    DIRECTION OUTPUT ;
    USE SIGNAL ;
    SHAPE ABUTMENT ;
    PORT
      LAYER metal3 ;
      RECT 898.905 985.600 898.975 985.670 ;
    END
  END r0_rd_out[123]
  PIN r0_rd_out[124]
    DIRECTION OUTPUT ;
    USE SIGNAL ;
    SHAPE ABUTMENT ;
    PORT
      LAYER metal3 ;
      RECT 899.045 985.600 899.115 985.670 ;
    END
  END r0_rd_out[124]
  PIN r0_rd_out[125]
    DIRECTION OUTPUT ;
    USE SIGNAL ;
    SHAPE ABUTMENT ;
    PORT
      LAYER metal3 ;
      RECT 899.185 985.600 899.255 985.670 ;
    END
  END r0_rd_out[125]
  PIN r0_rd_out[126]
    DIRECTION OUTPUT ;
    USE SIGNAL ;
    SHAPE ABUTMENT ;
    PORT
      LAYER metal3 ;
      RECT 899.325 985.600 899.395 985.670 ;
    END
  END r0_rd_out[126]
  PIN r0_rd_out[127]
    DIRECTION OUTPUT ;
    USE SIGNAL ;
    SHAPE ABUTMENT ;
    PORT
      LAYER metal3 ;
      RECT 899.465 985.600 899.535 985.670 ;
    END
  END r0_rd_out[127]
  PIN r0_rd_out[128]
    DIRECTION OUTPUT ;
    USE SIGNAL ;
    SHAPE ABUTMENT ;
    PORT
      LAYER metal3 ;
      RECT 899.605 985.600 899.675 985.670 ;
    END
  END r0_rd_out[128]
  PIN r0_rd_out[129]
    DIRECTION OUTPUT ;
    USE SIGNAL ;
    SHAPE ABUTMENT ;
    PORT
      LAYER metal3 ;
      RECT 899.745 985.600 899.815 985.670 ;
    END
  END r0_rd_out[129]
  PIN r0_rd_out[130]
    DIRECTION OUTPUT ;
    USE SIGNAL ;
    SHAPE ABUTMENT ;
    PORT
      LAYER metal3 ;
      RECT 899.885 985.600 899.955 985.670 ;
    END
  END r0_rd_out[130]
  PIN r0_rd_out[131]
    DIRECTION OUTPUT ;
    USE SIGNAL ;
    SHAPE ABUTMENT ;
    PORT
      LAYER metal3 ;
      RECT 900.025 985.600 900.095 985.670 ;
    END
  END r0_rd_out[131]
  PIN r0_rd_out[132]
    DIRECTION OUTPUT ;
    USE SIGNAL ;
    SHAPE ABUTMENT ;
    PORT
      LAYER metal3 ;
      RECT 900.165 985.600 900.235 985.670 ;
    END
  END r0_rd_out[132]
  PIN r0_rd_out[133]
    DIRECTION OUTPUT ;
    USE SIGNAL ;
    SHAPE ABUTMENT ;
    PORT
      LAYER metal3 ;
      RECT 900.305 985.600 900.375 985.670 ;
    END
  END r0_rd_out[133]
  PIN r0_rd_out[134]
    DIRECTION OUTPUT ;
    USE SIGNAL ;
    SHAPE ABUTMENT ;
    PORT
      LAYER metal3 ;
      RECT 900.445 985.600 900.515 985.670 ;
    END
  END r0_rd_out[134]
  PIN r0_rd_out[135]
    DIRECTION OUTPUT ;
    USE SIGNAL ;
    SHAPE ABUTMENT ;
    PORT
      LAYER metal3 ;
      RECT 900.585 985.600 900.655 985.670 ;
    END
  END r0_rd_out[135]
  PIN r0_rd_out[136]
    DIRECTION OUTPUT ;
    USE SIGNAL ;
    SHAPE ABUTMENT ;
    PORT
      LAYER metal3 ;
      RECT 900.725 985.600 900.795 985.670 ;
    END
  END r0_rd_out[136]
  PIN r0_rd_out[137]
    DIRECTION OUTPUT ;
    USE SIGNAL ;
    SHAPE ABUTMENT ;
    PORT
      LAYER metal3 ;
      RECT 900.865 985.600 900.935 985.670 ;
    END
  END r0_rd_out[137]
  PIN r0_rd_out[138]
    DIRECTION OUTPUT ;
    USE SIGNAL ;
    SHAPE ABUTMENT ;
    PORT
      LAYER metal3 ;
      RECT 901.005 985.600 901.075 985.670 ;
    END
  END r0_rd_out[138]
  PIN r0_rd_out[139]
    DIRECTION OUTPUT ;
    USE SIGNAL ;
    SHAPE ABUTMENT ;
    PORT
      LAYER metal3 ;
      RECT 901.145 985.600 901.215 985.670 ;
    END
  END r0_rd_out[139]
  PIN r0_rd_out[140]
    DIRECTION OUTPUT ;
    USE SIGNAL ;
    SHAPE ABUTMENT ;
    PORT
      LAYER metal3 ;
      RECT 901.285 985.600 901.355 985.670 ;
    END
  END r0_rd_out[140]
  PIN r0_rd_out[141]
    DIRECTION OUTPUT ;
    USE SIGNAL ;
    SHAPE ABUTMENT ;
    PORT
      LAYER metal3 ;
      RECT 901.425 985.600 901.495 985.670 ;
    END
  END r0_rd_out[141]
  PIN r0_rd_out[142]
    DIRECTION OUTPUT ;
    USE SIGNAL ;
    SHAPE ABUTMENT ;
    PORT
      LAYER metal3 ;
      RECT 901.565 985.600 901.635 985.670 ;
    END
  END r0_rd_out[142]
  PIN r0_rd_out[143]
    DIRECTION OUTPUT ;
    USE SIGNAL ;
    SHAPE ABUTMENT ;
    PORT
      LAYER metal3 ;
      RECT 901.705 985.600 901.775 985.670 ;
    END
  END r0_rd_out[143]
  PIN r0_rd_out[144]
    DIRECTION OUTPUT ;
    USE SIGNAL ;
    SHAPE ABUTMENT ;
    PORT
      LAYER metal3 ;
      RECT 901.845 985.600 901.915 985.670 ;
    END
  END r0_rd_out[144]
  PIN r0_rd_out[145]
    DIRECTION OUTPUT ;
    USE SIGNAL ;
    SHAPE ABUTMENT ;
    PORT
      LAYER metal3 ;
      RECT 901.985 985.600 902.055 985.670 ;
    END
  END r0_rd_out[145]
  PIN r0_rd_out[146]
    DIRECTION OUTPUT ;
    USE SIGNAL ;
    SHAPE ABUTMENT ;
    PORT
      LAYER metal3 ;
      RECT 902.125 985.600 902.195 985.670 ;
    END
  END r0_rd_out[146]
  PIN r0_rd_out[147]
    DIRECTION OUTPUT ;
    USE SIGNAL ;
    SHAPE ABUTMENT ;
    PORT
      LAYER metal3 ;
      RECT 902.265 985.600 902.335 985.670 ;
    END
  END r0_rd_out[147]
  PIN r0_rd_out[148]
    DIRECTION OUTPUT ;
    USE SIGNAL ;
    SHAPE ABUTMENT ;
    PORT
      LAYER metal3 ;
      RECT 902.405 985.600 902.475 985.670 ;
    END
  END r0_rd_out[148]
  PIN r0_rd_out[149]
    DIRECTION OUTPUT ;
    USE SIGNAL ;
    SHAPE ABUTMENT ;
    PORT
      LAYER metal3 ;
      RECT 902.545 985.600 902.615 985.670 ;
    END
  END r0_rd_out[149]
  PIN r0_rd_out[150]
    DIRECTION OUTPUT ;
    USE SIGNAL ;
    SHAPE ABUTMENT ;
    PORT
      LAYER metal3 ;
      RECT 902.685 985.600 902.755 985.670 ;
    END
  END r0_rd_out[150]
  PIN r0_rd_out[151]
    DIRECTION OUTPUT ;
    USE SIGNAL ;
    SHAPE ABUTMENT ;
    PORT
      LAYER metal3 ;
      RECT 902.825 985.600 902.895 985.670 ;
    END
  END r0_rd_out[151]
  PIN r0_rd_out[152]
    DIRECTION OUTPUT ;
    USE SIGNAL ;
    SHAPE ABUTMENT ;
    PORT
      LAYER metal3 ;
      RECT 902.965 985.600 903.035 985.670 ;
    END
  END r0_rd_out[152]
  PIN r0_rd_out[153]
    DIRECTION OUTPUT ;
    USE SIGNAL ;
    SHAPE ABUTMENT ;
    PORT
      LAYER metal3 ;
      RECT 903.105 985.600 903.175 985.670 ;
    END
  END r0_rd_out[153]
  PIN r0_rd_out[154]
    DIRECTION OUTPUT ;
    USE SIGNAL ;
    SHAPE ABUTMENT ;
    PORT
      LAYER metal3 ;
      RECT 903.245 985.600 903.315 985.670 ;
    END
  END r0_rd_out[154]
  PIN r0_rd_out[155]
    DIRECTION OUTPUT ;
    USE SIGNAL ;
    SHAPE ABUTMENT ;
    PORT
      LAYER metal3 ;
      RECT 903.385 985.600 903.455 985.670 ;
    END
  END r0_rd_out[155]
  PIN r0_rd_out[156]
    DIRECTION OUTPUT ;
    USE SIGNAL ;
    SHAPE ABUTMENT ;
    PORT
      LAYER metal3 ;
      RECT 903.525 985.600 903.595 985.670 ;
    END
  END r0_rd_out[156]
  PIN r0_rd_out[157]
    DIRECTION OUTPUT ;
    USE SIGNAL ;
    SHAPE ABUTMENT ;
    PORT
      LAYER metal3 ;
      RECT 903.665 985.600 903.735 985.670 ;
    END
  END r0_rd_out[157]
  PIN r0_rd_out[158]
    DIRECTION OUTPUT ;
    USE SIGNAL ;
    SHAPE ABUTMENT ;
    PORT
      LAYER metal3 ;
      RECT 903.805 985.600 903.875 985.670 ;
    END
  END r0_rd_out[158]
  PIN r0_rd_out[159]
    DIRECTION OUTPUT ;
    USE SIGNAL ;
    SHAPE ABUTMENT ;
    PORT
      LAYER metal3 ;
      RECT 903.945 985.600 904.015 985.670 ;
    END
  END r0_rd_out[159]
  PIN r0_rd_out[160]
    DIRECTION OUTPUT ;
    USE SIGNAL ;
    SHAPE ABUTMENT ;
    PORT
      LAYER metal3 ;
      RECT 904.085 985.600 904.155 985.670 ;
    END
  END r0_rd_out[160]
  PIN r0_rd_out[161]
    DIRECTION OUTPUT ;
    USE SIGNAL ;
    SHAPE ABUTMENT ;
    PORT
      LAYER metal3 ;
      RECT 904.225 985.600 904.295 985.670 ;
    END
  END r0_rd_out[161]
  PIN r0_rd_out[162]
    DIRECTION OUTPUT ;
    USE SIGNAL ;
    SHAPE ABUTMENT ;
    PORT
      LAYER metal3 ;
      RECT 904.365 985.600 904.435 985.670 ;
    END
  END r0_rd_out[162]
  PIN r0_rd_out[163]
    DIRECTION OUTPUT ;
    USE SIGNAL ;
    SHAPE ABUTMENT ;
    PORT
      LAYER metal3 ;
      RECT 904.505 985.600 904.575 985.670 ;
    END
  END r0_rd_out[163]
  PIN r0_rd_out[164]
    DIRECTION OUTPUT ;
    USE SIGNAL ;
    SHAPE ABUTMENT ;
    PORT
      LAYER metal3 ;
      RECT 904.645 985.600 904.715 985.670 ;
    END
  END r0_rd_out[164]
  PIN r0_rd_out[165]
    DIRECTION OUTPUT ;
    USE SIGNAL ;
    SHAPE ABUTMENT ;
    PORT
      LAYER metal3 ;
      RECT 904.785 985.600 904.855 985.670 ;
    END
  END r0_rd_out[165]
  PIN r0_rd_out[166]
    DIRECTION OUTPUT ;
    USE SIGNAL ;
    SHAPE ABUTMENT ;
    PORT
      LAYER metal3 ;
      RECT 904.925 985.600 904.995 985.670 ;
    END
  END r0_rd_out[166]
  PIN r0_rd_out[167]
    DIRECTION OUTPUT ;
    USE SIGNAL ;
    SHAPE ABUTMENT ;
    PORT
      LAYER metal3 ;
      RECT 905.065 985.600 905.135 985.670 ;
    END
  END r0_rd_out[167]
  PIN r0_rd_out[168]
    DIRECTION OUTPUT ;
    USE SIGNAL ;
    SHAPE ABUTMENT ;
    PORT
      LAYER metal3 ;
      RECT 905.205 985.600 905.275 985.670 ;
    END
  END r0_rd_out[168]
  PIN r0_rd_out[169]
    DIRECTION OUTPUT ;
    USE SIGNAL ;
    SHAPE ABUTMENT ;
    PORT
      LAYER metal3 ;
      RECT 905.345 985.600 905.415 985.670 ;
    END
  END r0_rd_out[169]
  PIN r0_rd_out[170]
    DIRECTION OUTPUT ;
    USE SIGNAL ;
    SHAPE ABUTMENT ;
    PORT
      LAYER metal3 ;
      RECT 905.485 985.600 905.555 985.670 ;
    END
  END r0_rd_out[170]
  PIN r0_rd_out[171]
    DIRECTION OUTPUT ;
    USE SIGNAL ;
    SHAPE ABUTMENT ;
    PORT
      LAYER metal3 ;
      RECT 905.625 985.600 905.695 985.670 ;
    END
  END r0_rd_out[171]
  PIN r0_rd_out[172]
    DIRECTION OUTPUT ;
    USE SIGNAL ;
    SHAPE ABUTMENT ;
    PORT
      LAYER metal3 ;
      RECT 905.765 985.600 905.835 985.670 ;
    END
  END r0_rd_out[172]
  PIN r0_rd_out[173]
    DIRECTION OUTPUT ;
    USE SIGNAL ;
    SHAPE ABUTMENT ;
    PORT
      LAYER metal3 ;
      RECT 905.905 985.600 905.975 985.670 ;
    END
  END r0_rd_out[173]
  PIN r0_rd_out[174]
    DIRECTION OUTPUT ;
    USE SIGNAL ;
    SHAPE ABUTMENT ;
    PORT
      LAYER metal3 ;
      RECT 906.045 985.600 906.115 985.670 ;
    END
  END r0_rd_out[174]
  PIN r0_rd_out[175]
    DIRECTION OUTPUT ;
    USE SIGNAL ;
    SHAPE ABUTMENT ;
    PORT
      LAYER metal3 ;
      RECT 906.185 985.600 906.255 985.670 ;
    END
  END r0_rd_out[175]
  PIN r0_rd_out[176]
    DIRECTION OUTPUT ;
    USE SIGNAL ;
    SHAPE ABUTMENT ;
    PORT
      LAYER metal3 ;
      RECT 906.325 985.600 906.395 985.670 ;
    END
  END r0_rd_out[176]
  PIN r0_rd_out[177]
    DIRECTION OUTPUT ;
    USE SIGNAL ;
    SHAPE ABUTMENT ;
    PORT
      LAYER metal3 ;
      RECT 906.465 985.600 906.535 985.670 ;
    END
  END r0_rd_out[177]
  PIN r0_rd_out[178]
    DIRECTION OUTPUT ;
    USE SIGNAL ;
    SHAPE ABUTMENT ;
    PORT
      LAYER metal3 ;
      RECT 906.605 985.600 906.675 985.670 ;
    END
  END r0_rd_out[178]
  PIN r0_rd_out[179]
    DIRECTION OUTPUT ;
    USE SIGNAL ;
    SHAPE ABUTMENT ;
    PORT
      LAYER metal3 ;
      RECT 906.745 985.600 906.815 985.670 ;
    END
  END r0_rd_out[179]
  PIN r0_rd_out[180]
    DIRECTION OUTPUT ;
    USE SIGNAL ;
    SHAPE ABUTMENT ;
    PORT
      LAYER metal3 ;
      RECT 906.885 985.600 906.955 985.670 ;
    END
  END r0_rd_out[180]
  PIN r0_rd_out[181]
    DIRECTION OUTPUT ;
    USE SIGNAL ;
    SHAPE ABUTMENT ;
    PORT
      LAYER metal3 ;
      RECT 907.025 985.600 907.095 985.670 ;
    END
  END r0_rd_out[181]
  PIN r0_rd_out[182]
    DIRECTION OUTPUT ;
    USE SIGNAL ;
    SHAPE ABUTMENT ;
    PORT
      LAYER metal3 ;
      RECT 907.165 985.600 907.235 985.670 ;
    END
  END r0_rd_out[182]
  PIN r0_rd_out[183]
    DIRECTION OUTPUT ;
    USE SIGNAL ;
    SHAPE ABUTMENT ;
    PORT
      LAYER metal3 ;
      RECT 907.305 985.600 907.375 985.670 ;
    END
  END r0_rd_out[183]
  PIN r0_rd_out[184]
    DIRECTION OUTPUT ;
    USE SIGNAL ;
    SHAPE ABUTMENT ;
    PORT
      LAYER metal3 ;
      RECT 907.445 985.600 907.515 985.670 ;
    END
  END r0_rd_out[184]
  PIN r0_rd_out[185]
    DIRECTION OUTPUT ;
    USE SIGNAL ;
    SHAPE ABUTMENT ;
    PORT
      LAYER metal3 ;
      RECT 907.585 985.600 907.655 985.670 ;
    END
  END r0_rd_out[185]
  PIN r0_rd_out[186]
    DIRECTION OUTPUT ;
    USE SIGNAL ;
    SHAPE ABUTMENT ;
    PORT
      LAYER metal3 ;
      RECT 907.725 985.600 907.795 985.670 ;
    END
  END r0_rd_out[186]
  PIN r0_rd_out[187]
    DIRECTION OUTPUT ;
    USE SIGNAL ;
    SHAPE ABUTMENT ;
    PORT
      LAYER metal3 ;
      RECT 907.865 985.600 907.935 985.670 ;
    END
  END r0_rd_out[187]
  PIN r0_rd_out[188]
    DIRECTION OUTPUT ;
    USE SIGNAL ;
    SHAPE ABUTMENT ;
    PORT
      LAYER metal3 ;
      RECT 908.005 985.600 908.075 985.670 ;
    END
  END r0_rd_out[188]
  PIN r0_rd_out[189]
    DIRECTION OUTPUT ;
    USE SIGNAL ;
    SHAPE ABUTMENT ;
    PORT
      LAYER metal3 ;
      RECT 908.145 985.600 908.215 985.670 ;
    END
  END r0_rd_out[189]
  PIN r0_rd_out[190]
    DIRECTION OUTPUT ;
    USE SIGNAL ;
    SHAPE ABUTMENT ;
    PORT
      LAYER metal3 ;
      RECT 908.285 985.600 908.355 985.670 ;
    END
  END r0_rd_out[190]
  PIN r0_rd_out[191]
    DIRECTION OUTPUT ;
    USE SIGNAL ;
    SHAPE ABUTMENT ;
    PORT
      LAYER metal3 ;
      RECT 908.425 985.600 908.495 985.670 ;
    END
  END r0_rd_out[191]
  PIN r0_rd_out[192]
    DIRECTION OUTPUT ;
    USE SIGNAL ;
    SHAPE ABUTMENT ;
    PORT
      LAYER metal3 ;
      RECT 908.565 985.600 908.635 985.670 ;
    END
  END r0_rd_out[192]
  PIN r0_rd_out[193]
    DIRECTION OUTPUT ;
    USE SIGNAL ;
    SHAPE ABUTMENT ;
    PORT
      LAYER metal3 ;
      RECT 908.705 985.600 908.775 985.670 ;
    END
  END r0_rd_out[193]
  PIN r0_rd_out[194]
    DIRECTION OUTPUT ;
    USE SIGNAL ;
    SHAPE ABUTMENT ;
    PORT
      LAYER metal3 ;
      RECT 908.845 985.600 908.915 985.670 ;
    END
  END r0_rd_out[194]
  PIN r0_rd_out[195]
    DIRECTION OUTPUT ;
    USE SIGNAL ;
    SHAPE ABUTMENT ;
    PORT
      LAYER metal3 ;
      RECT 908.985 985.600 909.055 985.670 ;
    END
  END r0_rd_out[195]
  PIN r0_rd_out[196]
    DIRECTION OUTPUT ;
    USE SIGNAL ;
    SHAPE ABUTMENT ;
    PORT
      LAYER metal3 ;
      RECT 909.125 985.600 909.195 985.670 ;
    END
  END r0_rd_out[196]
  PIN r0_rd_out[197]
    DIRECTION OUTPUT ;
    USE SIGNAL ;
    SHAPE ABUTMENT ;
    PORT
      LAYER metal3 ;
      RECT 909.265 985.600 909.335 985.670 ;
    END
  END r0_rd_out[197]
  PIN r0_rd_out[198]
    DIRECTION OUTPUT ;
    USE SIGNAL ;
    SHAPE ABUTMENT ;
    PORT
      LAYER metal3 ;
      RECT 909.405 985.600 909.475 985.670 ;
    END
  END r0_rd_out[198]
  PIN r0_rd_out[199]
    DIRECTION OUTPUT ;
    USE SIGNAL ;
    SHAPE ABUTMENT ;
    PORT
      LAYER metal3 ;
      RECT 909.545 985.600 909.615 985.670 ;
    END
  END r0_rd_out[199]
  PIN r0_rd_out[200]
    DIRECTION OUTPUT ;
    USE SIGNAL ;
    SHAPE ABUTMENT ;
    PORT
      LAYER metal3 ;
      RECT 909.685 985.600 909.755 985.670 ;
    END
  END r0_rd_out[200]
  PIN r0_rd_out[201]
    DIRECTION OUTPUT ;
    USE SIGNAL ;
    SHAPE ABUTMENT ;
    PORT
      LAYER metal3 ;
      RECT 909.825 985.600 909.895 985.670 ;
    END
  END r0_rd_out[201]
  PIN r0_rd_out[202]
    DIRECTION OUTPUT ;
    USE SIGNAL ;
    SHAPE ABUTMENT ;
    PORT
      LAYER metal3 ;
      RECT 909.965 985.600 910.035 985.670 ;
    END
  END r0_rd_out[202]
  PIN r0_rd_out[203]
    DIRECTION OUTPUT ;
    USE SIGNAL ;
    SHAPE ABUTMENT ;
    PORT
      LAYER metal3 ;
      RECT 910.105 985.600 910.175 985.670 ;
    END
  END r0_rd_out[203]
  PIN r0_rd_out[204]
    DIRECTION OUTPUT ;
    USE SIGNAL ;
    SHAPE ABUTMENT ;
    PORT
      LAYER metal3 ;
      RECT 910.245 985.600 910.315 985.670 ;
    END
  END r0_rd_out[204]
  PIN r0_rd_out[205]
    DIRECTION OUTPUT ;
    USE SIGNAL ;
    SHAPE ABUTMENT ;
    PORT
      LAYER metal3 ;
      RECT 910.385 985.600 910.455 985.670 ;
    END
  END r0_rd_out[205]
  PIN r0_rd_out[206]
    DIRECTION OUTPUT ;
    USE SIGNAL ;
    SHAPE ABUTMENT ;
    PORT
      LAYER metal3 ;
      RECT 910.525 985.600 910.595 985.670 ;
    END
  END r0_rd_out[206]
  PIN r0_rd_out[207]
    DIRECTION OUTPUT ;
    USE SIGNAL ;
    SHAPE ABUTMENT ;
    PORT
      LAYER metal3 ;
      RECT 910.665 985.600 910.735 985.670 ;
    END
  END r0_rd_out[207]
  PIN r0_rd_out[208]
    DIRECTION OUTPUT ;
    USE SIGNAL ;
    SHAPE ABUTMENT ;
    PORT
      LAYER metal3 ;
      RECT 910.805 985.600 910.875 985.670 ;
    END
  END r0_rd_out[208]
  PIN r0_rd_out[209]
    DIRECTION OUTPUT ;
    USE SIGNAL ;
    SHAPE ABUTMENT ;
    PORT
      LAYER metal3 ;
      RECT 910.945 985.600 911.015 985.670 ;
    END
  END r0_rd_out[209]
  PIN r0_rd_out[210]
    DIRECTION OUTPUT ;
    USE SIGNAL ;
    SHAPE ABUTMENT ;
    PORT
      LAYER metal3 ;
      RECT 911.085 985.600 911.155 985.670 ;
    END
  END r0_rd_out[210]
  PIN r0_rd_out[211]
    DIRECTION OUTPUT ;
    USE SIGNAL ;
    SHAPE ABUTMENT ;
    PORT
      LAYER metal3 ;
      RECT 911.225 985.600 911.295 985.670 ;
    END
  END r0_rd_out[211]
  PIN r0_rd_out[212]
    DIRECTION OUTPUT ;
    USE SIGNAL ;
    SHAPE ABUTMENT ;
    PORT
      LAYER metal3 ;
      RECT 911.365 985.600 911.435 985.670 ;
    END
  END r0_rd_out[212]
  PIN r0_rd_out[213]
    DIRECTION OUTPUT ;
    USE SIGNAL ;
    SHAPE ABUTMENT ;
    PORT
      LAYER metal3 ;
      RECT 911.505 985.600 911.575 985.670 ;
    END
  END r0_rd_out[213]
  PIN r0_rd_out[214]
    DIRECTION OUTPUT ;
    USE SIGNAL ;
    SHAPE ABUTMENT ;
    PORT
      LAYER metal3 ;
      RECT 911.645 985.600 911.715 985.670 ;
    END
  END r0_rd_out[214]
  PIN r0_rd_out[215]
    DIRECTION OUTPUT ;
    USE SIGNAL ;
    SHAPE ABUTMENT ;
    PORT
      LAYER metal3 ;
      RECT 911.785 985.600 911.855 985.670 ;
    END
  END r0_rd_out[215]
  PIN r0_rd_out[216]
    DIRECTION OUTPUT ;
    USE SIGNAL ;
    SHAPE ABUTMENT ;
    PORT
      LAYER metal3 ;
      RECT 911.925 985.600 911.995 985.670 ;
    END
  END r0_rd_out[216]
  PIN r0_rd_out[217]
    DIRECTION OUTPUT ;
    USE SIGNAL ;
    SHAPE ABUTMENT ;
    PORT
      LAYER metal3 ;
      RECT 912.065 985.600 912.135 985.670 ;
    END
  END r0_rd_out[217]
  PIN r0_rd_out[218]
    DIRECTION OUTPUT ;
    USE SIGNAL ;
    SHAPE ABUTMENT ;
    PORT
      LAYER metal3 ;
      RECT 912.205 985.600 912.275 985.670 ;
    END
  END r0_rd_out[218]
  PIN r0_rd_out[219]
    DIRECTION OUTPUT ;
    USE SIGNAL ;
    SHAPE ABUTMENT ;
    PORT
      LAYER metal3 ;
      RECT 912.345 985.600 912.415 985.670 ;
    END
  END r0_rd_out[219]
  PIN r0_rd_out[220]
    DIRECTION OUTPUT ;
    USE SIGNAL ;
    SHAPE ABUTMENT ;
    PORT
      LAYER metal3 ;
      RECT 912.485 985.600 912.555 985.670 ;
    END
  END r0_rd_out[220]
  PIN r0_rd_out[221]
    DIRECTION OUTPUT ;
    USE SIGNAL ;
    SHAPE ABUTMENT ;
    PORT
      LAYER metal3 ;
      RECT 912.625 985.600 912.695 985.670 ;
    END
  END r0_rd_out[221]
  PIN r0_rd_out[222]
    DIRECTION OUTPUT ;
    USE SIGNAL ;
    SHAPE ABUTMENT ;
    PORT
      LAYER metal3 ;
      RECT 912.765 985.600 912.835 985.670 ;
    END
  END r0_rd_out[222]
  PIN r0_rd_out[223]
    DIRECTION OUTPUT ;
    USE SIGNAL ;
    SHAPE ABUTMENT ;
    PORT
      LAYER metal3 ;
      RECT 912.905 985.600 912.975 985.670 ;
    END
  END r0_rd_out[223]
  PIN r0_rd_out[224]
    DIRECTION OUTPUT ;
    USE SIGNAL ;
    SHAPE ABUTMENT ;
    PORT
      LAYER metal3 ;
      RECT 913.045 985.600 913.115 985.670 ;
    END
  END r0_rd_out[224]
  PIN r0_rd_out[225]
    DIRECTION OUTPUT ;
    USE SIGNAL ;
    SHAPE ABUTMENT ;
    PORT
      LAYER metal3 ;
      RECT 913.185 985.600 913.255 985.670 ;
    END
  END r0_rd_out[225]
  PIN r0_rd_out[226]
    DIRECTION OUTPUT ;
    USE SIGNAL ;
    SHAPE ABUTMENT ;
    PORT
      LAYER metal3 ;
      RECT 913.325 985.600 913.395 985.670 ;
    END
  END r0_rd_out[226]
  PIN r0_rd_out[227]
    DIRECTION OUTPUT ;
    USE SIGNAL ;
    SHAPE ABUTMENT ;
    PORT
      LAYER metal3 ;
      RECT 913.465 985.600 913.535 985.670 ;
    END
  END r0_rd_out[227]
  PIN r0_rd_out[228]
    DIRECTION OUTPUT ;
    USE SIGNAL ;
    SHAPE ABUTMENT ;
    PORT
      LAYER metal3 ;
      RECT 913.605 985.600 913.675 985.670 ;
    END
  END r0_rd_out[228]
  PIN r0_rd_out[229]
    DIRECTION OUTPUT ;
    USE SIGNAL ;
    SHAPE ABUTMENT ;
    PORT
      LAYER metal3 ;
      RECT 913.745 985.600 913.815 985.670 ;
    END
  END r0_rd_out[229]
  PIN r0_rd_out[230]
    DIRECTION OUTPUT ;
    USE SIGNAL ;
    SHAPE ABUTMENT ;
    PORT
      LAYER metal3 ;
      RECT 913.885 985.600 913.955 985.670 ;
    END
  END r0_rd_out[230]
  PIN r0_rd_out[231]
    DIRECTION OUTPUT ;
    USE SIGNAL ;
    SHAPE ABUTMENT ;
    PORT
      LAYER metal3 ;
      RECT 914.025 985.600 914.095 985.670 ;
    END
  END r0_rd_out[231]
  PIN r0_rd_out[232]
    DIRECTION OUTPUT ;
    USE SIGNAL ;
    SHAPE ABUTMENT ;
    PORT
      LAYER metal3 ;
      RECT 914.165 985.600 914.235 985.670 ;
    END
  END r0_rd_out[232]
  PIN r0_rd_out[233]
    DIRECTION OUTPUT ;
    USE SIGNAL ;
    SHAPE ABUTMENT ;
    PORT
      LAYER metal3 ;
      RECT 914.305 985.600 914.375 985.670 ;
    END
  END r0_rd_out[233]
  PIN r0_rd_out[234]
    DIRECTION OUTPUT ;
    USE SIGNAL ;
    SHAPE ABUTMENT ;
    PORT
      LAYER metal3 ;
      RECT 914.445 985.600 914.515 985.670 ;
    END
  END r0_rd_out[234]
  PIN r0_rd_out[235]
    DIRECTION OUTPUT ;
    USE SIGNAL ;
    SHAPE ABUTMENT ;
    PORT
      LAYER metal3 ;
      RECT 914.585 985.600 914.655 985.670 ;
    END
  END r0_rd_out[235]
  PIN r0_rd_out[236]
    DIRECTION OUTPUT ;
    USE SIGNAL ;
    SHAPE ABUTMENT ;
    PORT
      LAYER metal3 ;
      RECT 914.725 985.600 914.795 985.670 ;
    END
  END r0_rd_out[236]
  PIN r0_rd_out[237]
    DIRECTION OUTPUT ;
    USE SIGNAL ;
    SHAPE ABUTMENT ;
    PORT
      LAYER metal3 ;
      RECT 914.865 985.600 914.935 985.670 ;
    END
  END r0_rd_out[237]
  PIN r0_rd_out[238]
    DIRECTION OUTPUT ;
    USE SIGNAL ;
    SHAPE ABUTMENT ;
    PORT
      LAYER metal3 ;
      RECT 915.005 985.600 915.075 985.670 ;
    END
  END r0_rd_out[238]
  PIN r0_rd_out[239]
    DIRECTION OUTPUT ;
    USE SIGNAL ;
    SHAPE ABUTMENT ;
    PORT
      LAYER metal3 ;
      RECT 915.145 985.600 915.215 985.670 ;
    END
  END r0_rd_out[239]
  PIN r0_rd_out[240]
    DIRECTION OUTPUT ;
    USE SIGNAL ;
    SHAPE ABUTMENT ;
    PORT
      LAYER metal3 ;
      RECT 915.285 985.600 915.355 985.670 ;
    END
  END r0_rd_out[240]
  PIN r0_rd_out[241]
    DIRECTION OUTPUT ;
    USE SIGNAL ;
    SHAPE ABUTMENT ;
    PORT
      LAYER metal3 ;
      RECT 915.425 985.600 915.495 985.670 ;
    END
  END r0_rd_out[241]
  PIN r0_rd_out[242]
    DIRECTION OUTPUT ;
    USE SIGNAL ;
    SHAPE ABUTMENT ;
    PORT
      LAYER metal3 ;
      RECT 915.565 985.600 915.635 985.670 ;
    END
  END r0_rd_out[242]
  PIN r0_rd_out[243]
    DIRECTION OUTPUT ;
    USE SIGNAL ;
    SHAPE ABUTMENT ;
    PORT
      LAYER metal3 ;
      RECT 915.705 985.600 915.775 985.670 ;
    END
  END r0_rd_out[243]
  PIN r0_rd_out[244]
    DIRECTION OUTPUT ;
    USE SIGNAL ;
    SHAPE ABUTMENT ;
    PORT
      LAYER metal3 ;
      RECT 915.845 985.600 915.915 985.670 ;
    END
  END r0_rd_out[244]
  PIN r0_rd_out[245]
    DIRECTION OUTPUT ;
    USE SIGNAL ;
    SHAPE ABUTMENT ;
    PORT
      LAYER metal3 ;
      RECT 915.985 985.600 916.055 985.670 ;
    END
  END r0_rd_out[245]
  PIN r0_rd_out[246]
    DIRECTION OUTPUT ;
    USE SIGNAL ;
    SHAPE ABUTMENT ;
    PORT
      LAYER metal3 ;
      RECT 916.125 985.600 916.195 985.670 ;
    END
  END r0_rd_out[246]
  PIN r0_rd_out[247]
    DIRECTION OUTPUT ;
    USE SIGNAL ;
    SHAPE ABUTMENT ;
    PORT
      LAYER metal3 ;
      RECT 916.265 985.600 916.335 985.670 ;
    END
  END r0_rd_out[247]
  PIN r0_rd_out[248]
    DIRECTION OUTPUT ;
    USE SIGNAL ;
    SHAPE ABUTMENT ;
    PORT
      LAYER metal3 ;
      RECT 916.405 985.600 916.475 985.670 ;
    END
  END r0_rd_out[248]
  PIN r0_rd_out[249]
    DIRECTION OUTPUT ;
    USE SIGNAL ;
    SHAPE ABUTMENT ;
    PORT
      LAYER metal3 ;
      RECT 916.545 985.600 916.615 985.670 ;
    END
  END r0_rd_out[249]
  PIN r0_rd_out[250]
    DIRECTION OUTPUT ;
    USE SIGNAL ;
    SHAPE ABUTMENT ;
    PORT
      LAYER metal3 ;
      RECT 916.685 985.600 916.755 985.670 ;
    END
  END r0_rd_out[250]
  PIN r0_rd_out[251]
    DIRECTION OUTPUT ;
    USE SIGNAL ;
    SHAPE ABUTMENT ;
    PORT
      LAYER metal3 ;
      RECT 916.825 985.600 916.895 985.670 ;
    END
  END r0_rd_out[251]
  PIN r0_rd_out[252]
    DIRECTION OUTPUT ;
    USE SIGNAL ;
    SHAPE ABUTMENT ;
    PORT
      LAYER metal3 ;
      RECT 916.965 985.600 917.035 985.670 ;
    END
  END r0_rd_out[252]
  PIN r0_rd_out[253]
    DIRECTION OUTPUT ;
    USE SIGNAL ;
    SHAPE ABUTMENT ;
    PORT
      LAYER metal3 ;
      RECT 917.105 985.600 917.175 985.670 ;
    END
  END r0_rd_out[253]
  PIN r0_rd_out[254]
    DIRECTION OUTPUT ;
    USE SIGNAL ;
    SHAPE ABUTMENT ;
    PORT
      LAYER metal3 ;
      RECT 917.245 985.600 917.315 985.670 ;
    END
  END r0_rd_out[254]
  PIN r0_rd_out[255]
    DIRECTION OUTPUT ;
    USE SIGNAL ;
    SHAPE ABUTMENT ;
    PORT
      LAYER metal3 ;
      RECT 917.385 985.600 917.455 985.670 ;
    END
  END r0_rd_out[255]
  PIN r0_rd_out[256]
    DIRECTION OUTPUT ;
    USE SIGNAL ;
    SHAPE ABUTMENT ;
    PORT
      LAYER metal3 ;
      RECT 917.525 985.600 917.595 985.670 ;
    END
  END r0_rd_out[256]
  PIN r0_rd_out[257]
    DIRECTION OUTPUT ;
    USE SIGNAL ;
    SHAPE ABUTMENT ;
    PORT
      LAYER metal3 ;
      RECT 917.665 985.600 917.735 985.670 ;
    END
  END r0_rd_out[257]
  PIN r0_rd_out[258]
    DIRECTION OUTPUT ;
    USE SIGNAL ;
    SHAPE ABUTMENT ;
    PORT
      LAYER metal3 ;
      RECT 917.805 985.600 917.875 985.670 ;
    END
  END r0_rd_out[258]
  PIN r0_rd_out[259]
    DIRECTION OUTPUT ;
    USE SIGNAL ;
    SHAPE ABUTMENT ;
    PORT
      LAYER metal3 ;
      RECT 917.945 985.600 918.015 985.670 ;
    END
  END r0_rd_out[259]
  PIN r0_rd_out[260]
    DIRECTION OUTPUT ;
    USE SIGNAL ;
    SHAPE ABUTMENT ;
    PORT
      LAYER metal3 ;
      RECT 918.085 985.600 918.155 985.670 ;
    END
  END r0_rd_out[260]
  PIN r0_rd_out[261]
    DIRECTION OUTPUT ;
    USE SIGNAL ;
    SHAPE ABUTMENT ;
    PORT
      LAYER metal3 ;
      RECT 918.225 985.600 918.295 985.670 ;
    END
  END r0_rd_out[261]
  PIN r0_rd_out[262]
    DIRECTION OUTPUT ;
    USE SIGNAL ;
    SHAPE ABUTMENT ;
    PORT
      LAYER metal3 ;
      RECT 918.365 985.600 918.435 985.670 ;
    END
  END r0_rd_out[262]
  PIN r0_rd_out[263]
    DIRECTION OUTPUT ;
    USE SIGNAL ;
    SHAPE ABUTMENT ;
    PORT
      LAYER metal3 ;
      RECT 918.505 985.600 918.575 985.670 ;
    END
  END r0_rd_out[263]
  PIN r0_rd_out[264]
    DIRECTION OUTPUT ;
    USE SIGNAL ;
    SHAPE ABUTMENT ;
    PORT
      LAYER metal3 ;
      RECT 918.645 985.600 918.715 985.670 ;
    END
  END r0_rd_out[264]
  PIN r0_rd_out[265]
    DIRECTION OUTPUT ;
    USE SIGNAL ;
    SHAPE ABUTMENT ;
    PORT
      LAYER metal3 ;
      RECT 918.785 985.600 918.855 985.670 ;
    END
  END r0_rd_out[265]
  PIN r0_rd_out[266]
    DIRECTION OUTPUT ;
    USE SIGNAL ;
    SHAPE ABUTMENT ;
    PORT
      LAYER metal3 ;
      RECT 918.925 985.600 918.995 985.670 ;
    END
  END r0_rd_out[266]
  PIN r0_rd_out[267]
    DIRECTION OUTPUT ;
    USE SIGNAL ;
    SHAPE ABUTMENT ;
    PORT
      LAYER metal3 ;
      RECT 919.065 985.600 919.135 985.670 ;
    END
  END r0_rd_out[267]
  PIN r0_rd_out[268]
    DIRECTION OUTPUT ;
    USE SIGNAL ;
    SHAPE ABUTMENT ;
    PORT
      LAYER metal3 ;
      RECT 919.205 985.600 919.275 985.670 ;
    END
  END r0_rd_out[268]
  PIN r0_rd_out[269]
    DIRECTION OUTPUT ;
    USE SIGNAL ;
    SHAPE ABUTMENT ;
    PORT
      LAYER metal3 ;
      RECT 919.345 985.600 919.415 985.670 ;
    END
  END r0_rd_out[269]
  PIN r0_rd_out[270]
    DIRECTION OUTPUT ;
    USE SIGNAL ;
    SHAPE ABUTMENT ;
    PORT
      LAYER metal3 ;
      RECT 919.485 985.600 919.555 985.670 ;
    END
  END r0_rd_out[270]
  PIN r0_rd_out[271]
    DIRECTION OUTPUT ;
    USE SIGNAL ;
    SHAPE ABUTMENT ;
    PORT
      LAYER metal3 ;
      RECT 919.625 985.600 919.695 985.670 ;
    END
  END r0_rd_out[271]
  PIN r0_rd_out[272]
    DIRECTION OUTPUT ;
    USE SIGNAL ;
    SHAPE ABUTMENT ;
    PORT
      LAYER metal3 ;
      RECT 919.765 985.600 919.835 985.670 ;
    END
  END r0_rd_out[272]
  PIN r0_rd_out[273]
    DIRECTION OUTPUT ;
    USE SIGNAL ;
    SHAPE ABUTMENT ;
    PORT
      LAYER metal3 ;
      RECT 919.905 985.600 919.975 985.670 ;
    END
  END r0_rd_out[273]
  PIN r0_rd_out[274]
    DIRECTION OUTPUT ;
    USE SIGNAL ;
    SHAPE ABUTMENT ;
    PORT
      LAYER metal3 ;
      RECT 920.045 985.600 920.115 985.670 ;
    END
  END r0_rd_out[274]
  PIN r0_rd_out[275]
    DIRECTION OUTPUT ;
    USE SIGNAL ;
    SHAPE ABUTMENT ;
    PORT
      LAYER metal3 ;
      RECT 920.185 985.600 920.255 985.670 ;
    END
  END r0_rd_out[275]
  PIN r0_rd_out[276]
    DIRECTION OUTPUT ;
    USE SIGNAL ;
    SHAPE ABUTMENT ;
    PORT
      LAYER metal3 ;
      RECT 920.325 985.600 920.395 985.670 ;
    END
  END r0_rd_out[276]
  PIN r0_rd_out[277]
    DIRECTION OUTPUT ;
    USE SIGNAL ;
    SHAPE ABUTMENT ;
    PORT
      LAYER metal3 ;
      RECT 920.465 985.600 920.535 985.670 ;
    END
  END r0_rd_out[277]
  PIN r0_rd_out[278]
    DIRECTION OUTPUT ;
    USE SIGNAL ;
    SHAPE ABUTMENT ;
    PORT
      LAYER metal3 ;
      RECT 920.605 985.600 920.675 985.670 ;
    END
  END r0_rd_out[278]
  PIN r0_rd_out[279]
    DIRECTION OUTPUT ;
    USE SIGNAL ;
    SHAPE ABUTMENT ;
    PORT
      LAYER metal3 ;
      RECT 920.745 985.600 920.815 985.670 ;
    END
  END r0_rd_out[279]
  PIN r0_rd_out[280]
    DIRECTION OUTPUT ;
    USE SIGNAL ;
    SHAPE ABUTMENT ;
    PORT
      LAYER metal3 ;
      RECT 920.885 985.600 920.955 985.670 ;
    END
  END r0_rd_out[280]
  PIN r0_rd_out[281]
    DIRECTION OUTPUT ;
    USE SIGNAL ;
    SHAPE ABUTMENT ;
    PORT
      LAYER metal3 ;
      RECT 921.025 985.600 921.095 985.670 ;
    END
  END r0_rd_out[281]
  PIN r0_rd_out[282]
    DIRECTION OUTPUT ;
    USE SIGNAL ;
    SHAPE ABUTMENT ;
    PORT
      LAYER metal3 ;
      RECT 921.165 985.600 921.235 985.670 ;
    END
  END r0_rd_out[282]
  PIN r0_rd_out[283]
    DIRECTION OUTPUT ;
    USE SIGNAL ;
    SHAPE ABUTMENT ;
    PORT
      LAYER metal3 ;
      RECT 921.305 985.600 921.375 985.670 ;
    END
  END r0_rd_out[283]
  PIN r0_rd_out[284]
    DIRECTION OUTPUT ;
    USE SIGNAL ;
    SHAPE ABUTMENT ;
    PORT
      LAYER metal3 ;
      RECT 921.445 985.600 921.515 985.670 ;
    END
  END r0_rd_out[284]
  PIN r0_rd_out[285]
    DIRECTION OUTPUT ;
    USE SIGNAL ;
    SHAPE ABUTMENT ;
    PORT
      LAYER metal3 ;
      RECT 921.585 985.600 921.655 985.670 ;
    END
  END r0_rd_out[285]
  PIN r0_rd_out[286]
    DIRECTION OUTPUT ;
    USE SIGNAL ;
    SHAPE ABUTMENT ;
    PORT
      LAYER metal3 ;
      RECT 921.725 985.600 921.795 985.670 ;
    END
  END r0_rd_out[286]
  PIN r0_rd_out[287]
    DIRECTION OUTPUT ;
    USE SIGNAL ;
    SHAPE ABUTMENT ;
    PORT
      LAYER metal3 ;
      RECT 921.865 985.600 921.935 985.670 ;
    END
  END r0_rd_out[287]
  PIN r0_rd_out[288]
    DIRECTION OUTPUT ;
    USE SIGNAL ;
    SHAPE ABUTMENT ;
    PORT
      LAYER metal3 ;
      RECT 922.005 985.600 922.075 985.670 ;
    END
  END r0_rd_out[288]
  PIN r0_rd_out[289]
    DIRECTION OUTPUT ;
    USE SIGNAL ;
    SHAPE ABUTMENT ;
    PORT
      LAYER metal3 ;
      RECT 922.145 985.600 922.215 985.670 ;
    END
  END r0_rd_out[289]
  PIN r0_rd_out[290]
    DIRECTION OUTPUT ;
    USE SIGNAL ;
    SHAPE ABUTMENT ;
    PORT
      LAYER metal3 ;
      RECT 922.285 985.600 922.355 985.670 ;
    END
  END r0_rd_out[290]
  PIN r0_rd_out[291]
    DIRECTION OUTPUT ;
    USE SIGNAL ;
    SHAPE ABUTMENT ;
    PORT
      LAYER metal3 ;
      RECT 922.425 985.600 922.495 985.670 ;
    END
  END r0_rd_out[291]
  PIN r0_rd_out[292]
    DIRECTION OUTPUT ;
    USE SIGNAL ;
    SHAPE ABUTMENT ;
    PORT
      LAYER metal3 ;
      RECT 922.565 985.600 922.635 985.670 ;
    END
  END r0_rd_out[292]
  PIN r0_rd_out[293]
    DIRECTION OUTPUT ;
    USE SIGNAL ;
    SHAPE ABUTMENT ;
    PORT
      LAYER metal3 ;
      RECT 922.705 985.600 922.775 985.670 ;
    END
  END r0_rd_out[293]
  PIN r0_rd_out[294]
    DIRECTION OUTPUT ;
    USE SIGNAL ;
    SHAPE ABUTMENT ;
    PORT
      LAYER metal3 ;
      RECT 922.845 985.600 922.915 985.670 ;
    END
  END r0_rd_out[294]
  PIN r0_rd_out[295]
    DIRECTION OUTPUT ;
    USE SIGNAL ;
    SHAPE ABUTMENT ;
    PORT
      LAYER metal3 ;
      RECT 922.985 985.600 923.055 985.670 ;
    END
  END r0_rd_out[295]
  PIN r0_rd_out[296]
    DIRECTION OUTPUT ;
    USE SIGNAL ;
    SHAPE ABUTMENT ;
    PORT
      LAYER metal3 ;
      RECT 923.125 985.600 923.195 985.670 ;
    END
  END r0_rd_out[296]
  PIN r0_rd_out[297]
    DIRECTION OUTPUT ;
    USE SIGNAL ;
    SHAPE ABUTMENT ;
    PORT
      LAYER metal3 ;
      RECT 923.265 985.600 923.335 985.670 ;
    END
  END r0_rd_out[297]
  PIN r0_rd_out[298]
    DIRECTION OUTPUT ;
    USE SIGNAL ;
    SHAPE ABUTMENT ;
    PORT
      LAYER metal3 ;
      RECT 923.405 985.600 923.475 985.670 ;
    END
  END r0_rd_out[298]
  PIN r0_rd_out[299]
    DIRECTION OUTPUT ;
    USE SIGNAL ;
    SHAPE ABUTMENT ;
    PORT
      LAYER metal3 ;
      RECT 923.545 985.600 923.615 985.670 ;
    END
  END r0_rd_out[299]
  PIN r0_rd_out[300]
    DIRECTION OUTPUT ;
    USE SIGNAL ;
    SHAPE ABUTMENT ;
    PORT
      LAYER metal3 ;
      RECT 923.685 985.600 923.755 985.670 ;
    END
  END r0_rd_out[300]
  PIN r0_rd_out[301]
    DIRECTION OUTPUT ;
    USE SIGNAL ;
    SHAPE ABUTMENT ;
    PORT
      LAYER metal3 ;
      RECT 923.825 985.600 923.895 985.670 ;
    END
  END r0_rd_out[301]
  PIN r0_rd_out[302]
    DIRECTION OUTPUT ;
    USE SIGNAL ;
    SHAPE ABUTMENT ;
    PORT
      LAYER metal3 ;
      RECT 923.965 985.600 924.035 985.670 ;
    END
  END r0_rd_out[302]
  PIN r0_rd_out[303]
    DIRECTION OUTPUT ;
    USE SIGNAL ;
    SHAPE ABUTMENT ;
    PORT
      LAYER metal3 ;
      RECT 924.105 985.600 924.175 985.670 ;
    END
  END r0_rd_out[303]
  PIN r0_rd_out[304]
    DIRECTION OUTPUT ;
    USE SIGNAL ;
    SHAPE ABUTMENT ;
    PORT
      LAYER metal3 ;
      RECT 924.245 985.600 924.315 985.670 ;
    END
  END r0_rd_out[304]
  PIN r0_rd_out[305]
    DIRECTION OUTPUT ;
    USE SIGNAL ;
    SHAPE ABUTMENT ;
    PORT
      LAYER metal3 ;
      RECT 924.385 985.600 924.455 985.670 ;
    END
  END r0_rd_out[305]
  PIN r0_rd_out[306]
    DIRECTION OUTPUT ;
    USE SIGNAL ;
    SHAPE ABUTMENT ;
    PORT
      LAYER metal3 ;
      RECT 924.525 985.600 924.595 985.670 ;
    END
  END r0_rd_out[306]
  PIN r0_rd_out[307]
    DIRECTION OUTPUT ;
    USE SIGNAL ;
    SHAPE ABUTMENT ;
    PORT
      LAYER metal3 ;
      RECT 924.665 985.600 924.735 985.670 ;
    END
  END r0_rd_out[307]
  PIN r0_rd_out[308]
    DIRECTION OUTPUT ;
    USE SIGNAL ;
    SHAPE ABUTMENT ;
    PORT
      LAYER metal3 ;
      RECT 924.805 985.600 924.875 985.670 ;
    END
  END r0_rd_out[308]
  PIN r0_rd_out[309]
    DIRECTION OUTPUT ;
    USE SIGNAL ;
    SHAPE ABUTMENT ;
    PORT
      LAYER metal3 ;
      RECT 924.945 985.600 925.015 985.670 ;
    END
  END r0_rd_out[309]
  PIN r0_rd_out[310]
    DIRECTION OUTPUT ;
    USE SIGNAL ;
    SHAPE ABUTMENT ;
    PORT
      LAYER metal3 ;
      RECT 925.085 985.600 925.155 985.670 ;
    END
  END r0_rd_out[310]
  PIN r0_rd_out[311]
    DIRECTION OUTPUT ;
    USE SIGNAL ;
    SHAPE ABUTMENT ;
    PORT
      LAYER metal3 ;
      RECT 925.225 985.600 925.295 985.670 ;
    END
  END r0_rd_out[311]
  PIN r0_rd_out[312]
    DIRECTION OUTPUT ;
    USE SIGNAL ;
    SHAPE ABUTMENT ;
    PORT
      LAYER metal3 ;
      RECT 925.365 985.600 925.435 985.670 ;
    END
  END r0_rd_out[312]
  PIN r0_rd_out[313]
    DIRECTION OUTPUT ;
    USE SIGNAL ;
    SHAPE ABUTMENT ;
    PORT
      LAYER metal3 ;
      RECT 925.505 985.600 925.575 985.670 ;
    END
  END r0_rd_out[313]
  PIN r0_rd_out[314]
    DIRECTION OUTPUT ;
    USE SIGNAL ;
    SHAPE ABUTMENT ;
    PORT
      LAYER metal3 ;
      RECT 925.645 985.600 925.715 985.670 ;
    END
  END r0_rd_out[314]
  PIN r0_rd_out[315]
    DIRECTION OUTPUT ;
    USE SIGNAL ;
    SHAPE ABUTMENT ;
    PORT
      LAYER metal3 ;
      RECT 925.785 985.600 925.855 985.670 ;
    END
  END r0_rd_out[315]
  PIN r0_rd_out[316]
    DIRECTION OUTPUT ;
    USE SIGNAL ;
    SHAPE ABUTMENT ;
    PORT
      LAYER metal3 ;
      RECT 925.925 985.600 925.995 985.670 ;
    END
  END r0_rd_out[316]
  PIN r0_rd_out[317]
    DIRECTION OUTPUT ;
    USE SIGNAL ;
    SHAPE ABUTMENT ;
    PORT
      LAYER metal3 ;
      RECT 926.065 985.600 926.135 985.670 ;
    END
  END r0_rd_out[317]
  PIN r0_rd_out[318]
    DIRECTION OUTPUT ;
    USE SIGNAL ;
    SHAPE ABUTMENT ;
    PORT
      LAYER metal3 ;
      RECT 926.205 985.600 926.275 985.670 ;
    END
  END r0_rd_out[318]
  PIN r0_rd_out[319]
    DIRECTION OUTPUT ;
    USE SIGNAL ;
    SHAPE ABUTMENT ;
    PORT
      LAYER metal3 ;
      RECT 926.345 985.600 926.415 985.670 ;
    END
  END r0_rd_out[319]
  PIN r0_rd_out[320]
    DIRECTION OUTPUT ;
    USE SIGNAL ;
    SHAPE ABUTMENT ;
    PORT
      LAYER metal3 ;
      RECT 926.485 985.600 926.555 985.670 ;
    END
  END r0_rd_out[320]
  PIN r0_rd_out[321]
    DIRECTION OUTPUT ;
    USE SIGNAL ;
    SHAPE ABUTMENT ;
    PORT
      LAYER metal3 ;
      RECT 926.625 985.600 926.695 985.670 ;
    END
  END r0_rd_out[321]
  PIN r0_rd_out[322]
    DIRECTION OUTPUT ;
    USE SIGNAL ;
    SHAPE ABUTMENT ;
    PORT
      LAYER metal3 ;
      RECT 926.765 985.600 926.835 985.670 ;
    END
  END r0_rd_out[322]
  PIN r0_rd_out[323]
    DIRECTION OUTPUT ;
    USE SIGNAL ;
    SHAPE ABUTMENT ;
    PORT
      LAYER metal3 ;
      RECT 926.905 985.600 926.975 985.670 ;
    END
  END r0_rd_out[323]
  PIN r0_rd_out[324]
    DIRECTION OUTPUT ;
    USE SIGNAL ;
    SHAPE ABUTMENT ;
    PORT
      LAYER metal3 ;
      RECT 927.045 985.600 927.115 985.670 ;
    END
  END r0_rd_out[324]
  PIN r0_rd_out[325]
    DIRECTION OUTPUT ;
    USE SIGNAL ;
    SHAPE ABUTMENT ;
    PORT
      LAYER metal3 ;
      RECT 927.185 985.600 927.255 985.670 ;
    END
  END r0_rd_out[325]
  PIN r0_rd_out[326]
    DIRECTION OUTPUT ;
    USE SIGNAL ;
    SHAPE ABUTMENT ;
    PORT
      LAYER metal3 ;
      RECT 927.325 985.600 927.395 985.670 ;
    END
  END r0_rd_out[326]
  PIN r0_rd_out[327]
    DIRECTION OUTPUT ;
    USE SIGNAL ;
    SHAPE ABUTMENT ;
    PORT
      LAYER metal3 ;
      RECT 927.465 985.600 927.535 985.670 ;
    END
  END r0_rd_out[327]
  PIN r0_rd_out[328]
    DIRECTION OUTPUT ;
    USE SIGNAL ;
    SHAPE ABUTMENT ;
    PORT
      LAYER metal3 ;
      RECT 927.605 985.600 927.675 985.670 ;
    END
  END r0_rd_out[328]
  PIN r0_rd_out[329]
    DIRECTION OUTPUT ;
    USE SIGNAL ;
    SHAPE ABUTMENT ;
    PORT
      LAYER metal3 ;
      RECT 927.745 985.600 927.815 985.670 ;
    END
  END r0_rd_out[329]
  PIN r0_rd_out[330]
    DIRECTION OUTPUT ;
    USE SIGNAL ;
    SHAPE ABUTMENT ;
    PORT
      LAYER metal3 ;
      RECT 927.885 985.600 927.955 985.670 ;
    END
  END r0_rd_out[330]
  PIN r0_rd_out[331]
    DIRECTION OUTPUT ;
    USE SIGNAL ;
    SHAPE ABUTMENT ;
    PORT
      LAYER metal3 ;
      RECT 928.025 985.600 928.095 985.670 ;
    END
  END r0_rd_out[331]
  PIN r0_rd_out[332]
    DIRECTION OUTPUT ;
    USE SIGNAL ;
    SHAPE ABUTMENT ;
    PORT
      LAYER metal3 ;
      RECT 928.165 985.600 928.235 985.670 ;
    END
  END r0_rd_out[332]
  PIN r0_rd_out[333]
    DIRECTION OUTPUT ;
    USE SIGNAL ;
    SHAPE ABUTMENT ;
    PORT
      LAYER metal3 ;
      RECT 928.305 985.600 928.375 985.670 ;
    END
  END r0_rd_out[333]
  PIN r0_rd_out[334]
    DIRECTION OUTPUT ;
    USE SIGNAL ;
    SHAPE ABUTMENT ;
    PORT
      LAYER metal3 ;
      RECT 928.445 985.600 928.515 985.670 ;
    END
  END r0_rd_out[334]
  PIN r0_rd_out[335]
    DIRECTION OUTPUT ;
    USE SIGNAL ;
    SHAPE ABUTMENT ;
    PORT
      LAYER metal3 ;
      RECT 928.585 985.600 928.655 985.670 ;
    END
  END r0_rd_out[335]
  PIN r0_rd_out[336]
    DIRECTION OUTPUT ;
    USE SIGNAL ;
    SHAPE ABUTMENT ;
    PORT
      LAYER metal3 ;
      RECT 928.725 985.600 928.795 985.670 ;
    END
  END r0_rd_out[336]
  PIN r0_rd_out[337]
    DIRECTION OUTPUT ;
    USE SIGNAL ;
    SHAPE ABUTMENT ;
    PORT
      LAYER metal3 ;
      RECT 928.865 985.600 928.935 985.670 ;
    END
  END r0_rd_out[337]
  PIN r0_rd_out[338]
    DIRECTION OUTPUT ;
    USE SIGNAL ;
    SHAPE ABUTMENT ;
    PORT
      LAYER metal3 ;
      RECT 929.005 985.600 929.075 985.670 ;
    END
  END r0_rd_out[338]
  PIN r0_rd_out[339]
    DIRECTION OUTPUT ;
    USE SIGNAL ;
    SHAPE ABUTMENT ;
    PORT
      LAYER metal3 ;
      RECT 929.145 985.600 929.215 985.670 ;
    END
  END r0_rd_out[339]
  PIN r0_rd_out[340]
    DIRECTION OUTPUT ;
    USE SIGNAL ;
    SHAPE ABUTMENT ;
    PORT
      LAYER metal3 ;
      RECT 929.285 985.600 929.355 985.670 ;
    END
  END r0_rd_out[340]
  PIN r0_rd_out[341]
    DIRECTION OUTPUT ;
    USE SIGNAL ;
    SHAPE ABUTMENT ;
    PORT
      LAYER metal3 ;
      RECT 929.425 985.600 929.495 985.670 ;
    END
  END r0_rd_out[341]
  PIN r0_rd_out[342]
    DIRECTION OUTPUT ;
    USE SIGNAL ;
    SHAPE ABUTMENT ;
    PORT
      LAYER metal3 ;
      RECT 929.565 985.600 929.635 985.670 ;
    END
  END r0_rd_out[342]
  PIN r0_rd_out[343]
    DIRECTION OUTPUT ;
    USE SIGNAL ;
    SHAPE ABUTMENT ;
    PORT
      LAYER metal3 ;
      RECT 929.705 985.600 929.775 985.670 ;
    END
  END r0_rd_out[343]
  PIN r0_rd_out[344]
    DIRECTION OUTPUT ;
    USE SIGNAL ;
    SHAPE ABUTMENT ;
    PORT
      LAYER metal3 ;
      RECT 929.845 985.600 929.915 985.670 ;
    END
  END r0_rd_out[344]
  PIN r0_rd_out[345]
    DIRECTION OUTPUT ;
    USE SIGNAL ;
    SHAPE ABUTMENT ;
    PORT
      LAYER metal3 ;
      RECT 929.985 985.600 930.055 985.670 ;
    END
  END r0_rd_out[345]
  PIN r0_rd_out[346]
    DIRECTION OUTPUT ;
    USE SIGNAL ;
    SHAPE ABUTMENT ;
    PORT
      LAYER metal3 ;
      RECT 930.125 985.600 930.195 985.670 ;
    END
  END r0_rd_out[346]
  PIN r0_rd_out[347]
    DIRECTION OUTPUT ;
    USE SIGNAL ;
    SHAPE ABUTMENT ;
    PORT
      LAYER metal3 ;
      RECT 930.265 985.600 930.335 985.670 ;
    END
  END r0_rd_out[347]
  PIN r0_rd_out[348]
    DIRECTION OUTPUT ;
    USE SIGNAL ;
    SHAPE ABUTMENT ;
    PORT
      LAYER metal3 ;
      RECT 930.405 985.600 930.475 985.670 ;
    END
  END r0_rd_out[348]
  PIN r0_rd_out[349]
    DIRECTION OUTPUT ;
    USE SIGNAL ;
    SHAPE ABUTMENT ;
    PORT
      LAYER metal3 ;
      RECT 930.545 985.600 930.615 985.670 ;
    END
  END r0_rd_out[349]
  PIN r0_rd_out[350]
    DIRECTION OUTPUT ;
    USE SIGNAL ;
    SHAPE ABUTMENT ;
    PORT
      LAYER metal3 ;
      RECT 930.685 985.600 930.755 985.670 ;
    END
  END r0_rd_out[350]
  PIN r0_rd_out[351]
    DIRECTION OUTPUT ;
    USE SIGNAL ;
    SHAPE ABUTMENT ;
    PORT
      LAYER metal3 ;
      RECT 930.825 985.600 930.895 985.670 ;
    END
  END r0_rd_out[351]
  PIN r0_rd_out[352]
    DIRECTION OUTPUT ;
    USE SIGNAL ;
    SHAPE ABUTMENT ;
    PORT
      LAYER metal3 ;
      RECT 930.965 985.600 931.035 985.670 ;
    END
  END r0_rd_out[352]
  PIN r0_rd_out[353]
    DIRECTION OUTPUT ;
    USE SIGNAL ;
    SHAPE ABUTMENT ;
    PORT
      LAYER metal3 ;
      RECT 931.105 985.600 931.175 985.670 ;
    END
  END r0_rd_out[353]
  PIN r0_rd_out[354]
    DIRECTION OUTPUT ;
    USE SIGNAL ;
    SHAPE ABUTMENT ;
    PORT
      LAYER metal3 ;
      RECT 931.245 985.600 931.315 985.670 ;
    END
  END r0_rd_out[354]
  PIN r0_rd_out[355]
    DIRECTION OUTPUT ;
    USE SIGNAL ;
    SHAPE ABUTMENT ;
    PORT
      LAYER metal3 ;
      RECT 931.385 985.600 931.455 985.670 ;
    END
  END r0_rd_out[355]
  PIN r0_rd_out[356]
    DIRECTION OUTPUT ;
    USE SIGNAL ;
    SHAPE ABUTMENT ;
    PORT
      LAYER metal3 ;
      RECT 931.525 985.600 931.595 985.670 ;
    END
  END r0_rd_out[356]
  PIN r0_rd_out[357]
    DIRECTION OUTPUT ;
    USE SIGNAL ;
    SHAPE ABUTMENT ;
    PORT
      LAYER metal3 ;
      RECT 931.665 985.600 931.735 985.670 ;
    END
  END r0_rd_out[357]
  PIN r0_rd_out[358]
    DIRECTION OUTPUT ;
    USE SIGNAL ;
    SHAPE ABUTMENT ;
    PORT
      LAYER metal3 ;
      RECT 931.805 985.600 931.875 985.670 ;
    END
  END r0_rd_out[358]
  PIN r0_rd_out[359]
    DIRECTION OUTPUT ;
    USE SIGNAL ;
    SHAPE ABUTMENT ;
    PORT
      LAYER metal3 ;
      RECT 931.945 985.600 932.015 985.670 ;
    END
  END r0_rd_out[359]
  PIN r0_rd_out[360]
    DIRECTION OUTPUT ;
    USE SIGNAL ;
    SHAPE ABUTMENT ;
    PORT
      LAYER metal3 ;
      RECT 932.085 985.600 932.155 985.670 ;
    END
  END r0_rd_out[360]
  PIN r0_rd_out[361]
    DIRECTION OUTPUT ;
    USE SIGNAL ;
    SHAPE ABUTMENT ;
    PORT
      LAYER metal3 ;
      RECT 932.225 985.600 932.295 985.670 ;
    END
  END r0_rd_out[361]
  PIN r0_rd_out[362]
    DIRECTION OUTPUT ;
    USE SIGNAL ;
    SHAPE ABUTMENT ;
    PORT
      LAYER metal3 ;
      RECT 932.365 985.600 932.435 985.670 ;
    END
  END r0_rd_out[362]
  PIN r0_rd_out[363]
    DIRECTION OUTPUT ;
    USE SIGNAL ;
    SHAPE ABUTMENT ;
    PORT
      LAYER metal3 ;
      RECT 932.505 985.600 932.575 985.670 ;
    END
  END r0_rd_out[363]
  PIN r0_rd_out[364]
    DIRECTION OUTPUT ;
    USE SIGNAL ;
    SHAPE ABUTMENT ;
    PORT
      LAYER metal3 ;
      RECT 932.645 985.600 932.715 985.670 ;
    END
  END r0_rd_out[364]
  PIN r0_rd_out[365]
    DIRECTION OUTPUT ;
    USE SIGNAL ;
    SHAPE ABUTMENT ;
    PORT
      LAYER metal3 ;
      RECT 932.785 985.600 932.855 985.670 ;
    END
  END r0_rd_out[365]
  PIN r0_rd_out[366]
    DIRECTION OUTPUT ;
    USE SIGNAL ;
    SHAPE ABUTMENT ;
    PORT
      LAYER metal3 ;
      RECT 932.925 985.600 932.995 985.670 ;
    END
  END r0_rd_out[366]
  PIN r0_rd_out[367]
    DIRECTION OUTPUT ;
    USE SIGNAL ;
    SHAPE ABUTMENT ;
    PORT
      LAYER metal3 ;
      RECT 933.065 985.600 933.135 985.670 ;
    END
  END r0_rd_out[367]
  PIN r0_rd_out[368]
    DIRECTION OUTPUT ;
    USE SIGNAL ;
    SHAPE ABUTMENT ;
    PORT
      LAYER metal3 ;
      RECT 933.205 985.600 933.275 985.670 ;
    END
  END r0_rd_out[368]
  PIN r0_rd_out[369]
    DIRECTION OUTPUT ;
    USE SIGNAL ;
    SHAPE ABUTMENT ;
    PORT
      LAYER metal3 ;
      RECT 933.345 985.600 933.415 985.670 ;
    END
  END r0_rd_out[369]
  PIN r0_rd_out[370]
    DIRECTION OUTPUT ;
    USE SIGNAL ;
    SHAPE ABUTMENT ;
    PORT
      LAYER metal3 ;
      RECT 933.485 985.600 933.555 985.670 ;
    END
  END r0_rd_out[370]
  PIN r0_rd_out[371]
    DIRECTION OUTPUT ;
    USE SIGNAL ;
    SHAPE ABUTMENT ;
    PORT
      LAYER metal3 ;
      RECT 933.625 985.600 933.695 985.670 ;
    END
  END r0_rd_out[371]
  PIN r0_rd_out[372]
    DIRECTION OUTPUT ;
    USE SIGNAL ;
    SHAPE ABUTMENT ;
    PORT
      LAYER metal3 ;
      RECT 933.765 985.600 933.835 985.670 ;
    END
  END r0_rd_out[372]
  PIN r0_rd_out[373]
    DIRECTION OUTPUT ;
    USE SIGNAL ;
    SHAPE ABUTMENT ;
    PORT
      LAYER metal3 ;
      RECT 933.905 985.600 933.975 985.670 ;
    END
  END r0_rd_out[373]
  PIN r0_rd_out[374]
    DIRECTION OUTPUT ;
    USE SIGNAL ;
    SHAPE ABUTMENT ;
    PORT
      LAYER metal3 ;
      RECT 934.045 985.600 934.115 985.670 ;
    END
  END r0_rd_out[374]
  PIN r0_rd_out[375]
    DIRECTION OUTPUT ;
    USE SIGNAL ;
    SHAPE ABUTMENT ;
    PORT
      LAYER metal3 ;
      RECT 934.185 985.600 934.255 985.670 ;
    END
  END r0_rd_out[375]
  PIN r0_rd_out[376]
    DIRECTION OUTPUT ;
    USE SIGNAL ;
    SHAPE ABUTMENT ;
    PORT
      LAYER metal3 ;
      RECT 934.325 985.600 934.395 985.670 ;
    END
  END r0_rd_out[376]
  PIN r0_rd_out[377]
    DIRECTION OUTPUT ;
    USE SIGNAL ;
    SHAPE ABUTMENT ;
    PORT
      LAYER metal3 ;
      RECT 934.465 985.600 934.535 985.670 ;
    END
  END r0_rd_out[377]
  PIN r0_rd_out[378]
    DIRECTION OUTPUT ;
    USE SIGNAL ;
    SHAPE ABUTMENT ;
    PORT
      LAYER metal3 ;
      RECT 934.605 985.600 934.675 985.670 ;
    END
  END r0_rd_out[378]
  PIN r0_rd_out[379]
    DIRECTION OUTPUT ;
    USE SIGNAL ;
    SHAPE ABUTMENT ;
    PORT
      LAYER metal3 ;
      RECT 934.745 985.600 934.815 985.670 ;
    END
  END r0_rd_out[379]
  PIN r0_rd_out[380]
    DIRECTION OUTPUT ;
    USE SIGNAL ;
    SHAPE ABUTMENT ;
    PORT
      LAYER metal3 ;
      RECT 934.885 985.600 934.955 985.670 ;
    END
  END r0_rd_out[380]
  PIN r0_rd_out[381]
    DIRECTION OUTPUT ;
    USE SIGNAL ;
    SHAPE ABUTMENT ;
    PORT
      LAYER metal3 ;
      RECT 935.025 985.600 935.095 985.670 ;
    END
  END r0_rd_out[381]
  PIN r0_rd_out[382]
    DIRECTION OUTPUT ;
    USE SIGNAL ;
    SHAPE ABUTMENT ;
    PORT
      LAYER metal3 ;
      RECT 935.165 985.600 935.235 985.670 ;
    END
  END r0_rd_out[382]
  PIN r0_rd_out[383]
    DIRECTION OUTPUT ;
    USE SIGNAL ;
    SHAPE ABUTMENT ;
    PORT
      LAYER metal3 ;
      RECT 935.305 985.600 935.375 985.670 ;
    END
  END r0_rd_out[383]
  PIN r0_rd_out[384]
    DIRECTION OUTPUT ;
    USE SIGNAL ;
    SHAPE ABUTMENT ;
    PORT
      LAYER metal3 ;
      RECT 935.445 985.600 935.515 985.670 ;
    END
  END r0_rd_out[384]
  PIN r0_rd_out[385]
    DIRECTION OUTPUT ;
    USE SIGNAL ;
    SHAPE ABUTMENT ;
    PORT
      LAYER metal3 ;
      RECT 935.585 985.600 935.655 985.670 ;
    END
  END r0_rd_out[385]
  PIN r0_rd_out[386]
    DIRECTION OUTPUT ;
    USE SIGNAL ;
    SHAPE ABUTMENT ;
    PORT
      LAYER metal3 ;
      RECT 935.725 985.600 935.795 985.670 ;
    END
  END r0_rd_out[386]
  PIN r0_rd_out[387]
    DIRECTION OUTPUT ;
    USE SIGNAL ;
    SHAPE ABUTMENT ;
    PORT
      LAYER metal3 ;
      RECT 935.865 985.600 935.935 985.670 ;
    END
  END r0_rd_out[387]
  PIN r0_rd_out[388]
    DIRECTION OUTPUT ;
    USE SIGNAL ;
    SHAPE ABUTMENT ;
    PORT
      LAYER metal3 ;
      RECT 936.005 985.600 936.075 985.670 ;
    END
  END r0_rd_out[388]
  PIN r0_rd_out[389]
    DIRECTION OUTPUT ;
    USE SIGNAL ;
    SHAPE ABUTMENT ;
    PORT
      LAYER metal3 ;
      RECT 936.145 985.600 936.215 985.670 ;
    END
  END r0_rd_out[389]
  PIN r0_rd_out[390]
    DIRECTION OUTPUT ;
    USE SIGNAL ;
    SHAPE ABUTMENT ;
    PORT
      LAYER metal3 ;
      RECT 936.285 985.600 936.355 985.670 ;
    END
  END r0_rd_out[390]
  PIN r0_rd_out[391]
    DIRECTION OUTPUT ;
    USE SIGNAL ;
    SHAPE ABUTMENT ;
    PORT
      LAYER metal3 ;
      RECT 936.425 985.600 936.495 985.670 ;
    END
  END r0_rd_out[391]
  PIN r0_rd_out[392]
    DIRECTION OUTPUT ;
    USE SIGNAL ;
    SHAPE ABUTMENT ;
    PORT
      LAYER metal3 ;
      RECT 936.565 985.600 936.635 985.670 ;
    END
  END r0_rd_out[392]
  PIN r0_rd_out[393]
    DIRECTION OUTPUT ;
    USE SIGNAL ;
    SHAPE ABUTMENT ;
    PORT
      LAYER metal3 ;
      RECT 936.705 985.600 936.775 985.670 ;
    END
  END r0_rd_out[393]
  PIN r0_rd_out[394]
    DIRECTION OUTPUT ;
    USE SIGNAL ;
    SHAPE ABUTMENT ;
    PORT
      LAYER metal3 ;
      RECT 936.845 985.600 936.915 985.670 ;
    END
  END r0_rd_out[394]
  PIN r0_rd_out[395]
    DIRECTION OUTPUT ;
    USE SIGNAL ;
    SHAPE ABUTMENT ;
    PORT
      LAYER metal3 ;
      RECT 936.985 985.600 937.055 985.670 ;
    END
  END r0_rd_out[395]
  PIN r0_rd_out[396]
    DIRECTION OUTPUT ;
    USE SIGNAL ;
    SHAPE ABUTMENT ;
    PORT
      LAYER metal3 ;
      RECT 937.125 985.600 937.195 985.670 ;
    END
  END r0_rd_out[396]
  PIN r0_rd_out[397]
    DIRECTION OUTPUT ;
    USE SIGNAL ;
    SHAPE ABUTMENT ;
    PORT
      LAYER metal3 ;
      RECT 937.265 985.600 937.335 985.670 ;
    END
  END r0_rd_out[397]
  PIN r0_rd_out[398]
    DIRECTION OUTPUT ;
    USE SIGNAL ;
    SHAPE ABUTMENT ;
    PORT
      LAYER metal3 ;
      RECT 937.405 985.600 937.475 985.670 ;
    END
  END r0_rd_out[398]
  PIN r0_rd_out[399]
    DIRECTION OUTPUT ;
    USE SIGNAL ;
    SHAPE ABUTMENT ;
    PORT
      LAYER metal3 ;
      RECT 937.545 985.600 937.615 985.670 ;
    END
  END r0_rd_out[399]
  PIN r0_rd_out[400]
    DIRECTION OUTPUT ;
    USE SIGNAL ;
    SHAPE ABUTMENT ;
    PORT
      LAYER metal3 ;
      RECT 937.685 985.600 937.755 985.670 ;
    END
  END r0_rd_out[400]
  PIN r0_rd_out[401]
    DIRECTION OUTPUT ;
    USE SIGNAL ;
    SHAPE ABUTMENT ;
    PORT
      LAYER metal3 ;
      RECT 937.825 985.600 937.895 985.670 ;
    END
  END r0_rd_out[401]
  PIN r0_rd_out[402]
    DIRECTION OUTPUT ;
    USE SIGNAL ;
    SHAPE ABUTMENT ;
    PORT
      LAYER metal3 ;
      RECT 937.965 985.600 938.035 985.670 ;
    END
  END r0_rd_out[402]
  PIN r0_rd_out[403]
    DIRECTION OUTPUT ;
    USE SIGNAL ;
    SHAPE ABUTMENT ;
    PORT
      LAYER metal3 ;
      RECT 938.105 985.600 938.175 985.670 ;
    END
  END r0_rd_out[403]
  PIN r0_rd_out[404]
    DIRECTION OUTPUT ;
    USE SIGNAL ;
    SHAPE ABUTMENT ;
    PORT
      LAYER metal3 ;
      RECT 938.245 985.600 938.315 985.670 ;
    END
  END r0_rd_out[404]
  PIN r0_rd_out[405]
    DIRECTION OUTPUT ;
    USE SIGNAL ;
    SHAPE ABUTMENT ;
    PORT
      LAYER metal3 ;
      RECT 938.385 985.600 938.455 985.670 ;
    END
  END r0_rd_out[405]
  PIN r0_rd_out[406]
    DIRECTION OUTPUT ;
    USE SIGNAL ;
    SHAPE ABUTMENT ;
    PORT
      LAYER metal3 ;
      RECT 938.525 985.600 938.595 985.670 ;
    END
  END r0_rd_out[406]
  PIN r0_rd_out[407]
    DIRECTION OUTPUT ;
    USE SIGNAL ;
    SHAPE ABUTMENT ;
    PORT
      LAYER metal3 ;
      RECT 938.665 985.600 938.735 985.670 ;
    END
  END r0_rd_out[407]
  PIN r0_rd_out[408]
    DIRECTION OUTPUT ;
    USE SIGNAL ;
    SHAPE ABUTMENT ;
    PORT
      LAYER metal3 ;
      RECT 938.805 985.600 938.875 985.670 ;
    END
  END r0_rd_out[408]
  PIN r0_rd_out[409]
    DIRECTION OUTPUT ;
    USE SIGNAL ;
    SHAPE ABUTMENT ;
    PORT
      LAYER metal3 ;
      RECT 938.945 985.600 939.015 985.670 ;
    END
  END r0_rd_out[409]
  PIN r0_rd_out[410]
    DIRECTION OUTPUT ;
    USE SIGNAL ;
    SHAPE ABUTMENT ;
    PORT
      LAYER metal3 ;
      RECT 939.085 985.600 939.155 985.670 ;
    END
  END r0_rd_out[410]
  PIN r0_rd_out[411]
    DIRECTION OUTPUT ;
    USE SIGNAL ;
    SHAPE ABUTMENT ;
    PORT
      LAYER metal3 ;
      RECT 939.225 985.600 939.295 985.670 ;
    END
  END r0_rd_out[411]
  PIN r0_rd_out[412]
    DIRECTION OUTPUT ;
    USE SIGNAL ;
    SHAPE ABUTMENT ;
    PORT
      LAYER metal3 ;
      RECT 939.365 985.600 939.435 985.670 ;
    END
  END r0_rd_out[412]
  PIN r0_rd_out[413]
    DIRECTION OUTPUT ;
    USE SIGNAL ;
    SHAPE ABUTMENT ;
    PORT
      LAYER metal3 ;
      RECT 939.505 985.600 939.575 985.670 ;
    END
  END r0_rd_out[413]
  PIN r0_rd_out[414]
    DIRECTION OUTPUT ;
    USE SIGNAL ;
    SHAPE ABUTMENT ;
    PORT
      LAYER metal3 ;
      RECT 939.645 985.600 939.715 985.670 ;
    END
  END r0_rd_out[414]
  PIN r0_rd_out[415]
    DIRECTION OUTPUT ;
    USE SIGNAL ;
    SHAPE ABUTMENT ;
    PORT
      LAYER metal3 ;
      RECT 939.785 985.600 939.855 985.670 ;
    END
  END r0_rd_out[415]
  PIN r0_rd_out[416]
    DIRECTION OUTPUT ;
    USE SIGNAL ;
    SHAPE ABUTMENT ;
    PORT
      LAYER metal3 ;
      RECT 939.925 985.600 939.995 985.670 ;
    END
  END r0_rd_out[416]
  PIN r0_rd_out[417]
    DIRECTION OUTPUT ;
    USE SIGNAL ;
    SHAPE ABUTMENT ;
    PORT
      LAYER metal3 ;
      RECT 940.065 985.600 940.135 985.670 ;
    END
  END r0_rd_out[417]
  PIN r0_rd_out[418]
    DIRECTION OUTPUT ;
    USE SIGNAL ;
    SHAPE ABUTMENT ;
    PORT
      LAYER metal3 ;
      RECT 940.205 985.600 940.275 985.670 ;
    END
  END r0_rd_out[418]
  PIN r0_rd_out[419]
    DIRECTION OUTPUT ;
    USE SIGNAL ;
    SHAPE ABUTMENT ;
    PORT
      LAYER metal3 ;
      RECT 940.345 985.600 940.415 985.670 ;
    END
  END r0_rd_out[419]
  PIN r0_rd_out[420]
    DIRECTION OUTPUT ;
    USE SIGNAL ;
    SHAPE ABUTMENT ;
    PORT
      LAYER metal3 ;
      RECT 940.485 985.600 940.555 985.670 ;
    END
  END r0_rd_out[420]
  PIN r0_rd_out[421]
    DIRECTION OUTPUT ;
    USE SIGNAL ;
    SHAPE ABUTMENT ;
    PORT
      LAYER metal3 ;
      RECT 940.625 985.600 940.695 985.670 ;
    END
  END r0_rd_out[421]
  PIN r0_rd_out[422]
    DIRECTION OUTPUT ;
    USE SIGNAL ;
    SHAPE ABUTMENT ;
    PORT
      LAYER metal3 ;
      RECT 940.765 985.600 940.835 985.670 ;
    END
  END r0_rd_out[422]
  PIN r0_rd_out[423]
    DIRECTION OUTPUT ;
    USE SIGNAL ;
    SHAPE ABUTMENT ;
    PORT
      LAYER metal3 ;
      RECT 940.905 985.600 940.975 985.670 ;
    END
  END r0_rd_out[423]
  PIN r0_rd_out[424]
    DIRECTION OUTPUT ;
    USE SIGNAL ;
    SHAPE ABUTMENT ;
    PORT
      LAYER metal3 ;
      RECT 941.045 985.600 941.115 985.670 ;
    END
  END r0_rd_out[424]
  PIN r0_rd_out[425]
    DIRECTION OUTPUT ;
    USE SIGNAL ;
    SHAPE ABUTMENT ;
    PORT
      LAYER metal3 ;
      RECT 941.185 985.600 941.255 985.670 ;
    END
  END r0_rd_out[425]
  PIN r0_rd_out[426]
    DIRECTION OUTPUT ;
    USE SIGNAL ;
    SHAPE ABUTMENT ;
    PORT
      LAYER metal3 ;
      RECT 941.325 985.600 941.395 985.670 ;
    END
  END r0_rd_out[426]
  PIN r0_rd_out[427]
    DIRECTION OUTPUT ;
    USE SIGNAL ;
    SHAPE ABUTMENT ;
    PORT
      LAYER metal3 ;
      RECT 941.465 985.600 941.535 985.670 ;
    END
  END r0_rd_out[427]
  PIN r0_rd_out[428]
    DIRECTION OUTPUT ;
    USE SIGNAL ;
    SHAPE ABUTMENT ;
    PORT
      LAYER metal3 ;
      RECT 941.605 985.600 941.675 985.670 ;
    END
  END r0_rd_out[428]
  PIN r0_rd_out[429]
    DIRECTION OUTPUT ;
    USE SIGNAL ;
    SHAPE ABUTMENT ;
    PORT
      LAYER metal3 ;
      RECT 941.745 985.600 941.815 985.670 ;
    END
  END r0_rd_out[429]
  PIN r0_rd_out[430]
    DIRECTION OUTPUT ;
    USE SIGNAL ;
    SHAPE ABUTMENT ;
    PORT
      LAYER metal3 ;
      RECT 941.885 985.600 941.955 985.670 ;
    END
  END r0_rd_out[430]
  PIN r0_rd_out[431]
    DIRECTION OUTPUT ;
    USE SIGNAL ;
    SHAPE ABUTMENT ;
    PORT
      LAYER metal3 ;
      RECT 942.025 985.600 942.095 985.670 ;
    END
  END r0_rd_out[431]
  PIN r0_rd_out[432]
    DIRECTION OUTPUT ;
    USE SIGNAL ;
    SHAPE ABUTMENT ;
    PORT
      LAYER metal3 ;
      RECT 942.165 985.600 942.235 985.670 ;
    END
  END r0_rd_out[432]
  PIN r0_rd_out[433]
    DIRECTION OUTPUT ;
    USE SIGNAL ;
    SHAPE ABUTMENT ;
    PORT
      LAYER metal3 ;
      RECT 942.305 985.600 942.375 985.670 ;
    END
  END r0_rd_out[433]
  PIN r0_rd_out[434]
    DIRECTION OUTPUT ;
    USE SIGNAL ;
    SHAPE ABUTMENT ;
    PORT
      LAYER metal3 ;
      RECT 942.445 985.600 942.515 985.670 ;
    END
  END r0_rd_out[434]
  PIN r0_rd_out[435]
    DIRECTION OUTPUT ;
    USE SIGNAL ;
    SHAPE ABUTMENT ;
    PORT
      LAYER metal3 ;
      RECT 942.585 985.600 942.655 985.670 ;
    END
  END r0_rd_out[435]
  PIN r0_rd_out[436]
    DIRECTION OUTPUT ;
    USE SIGNAL ;
    SHAPE ABUTMENT ;
    PORT
      LAYER metal3 ;
      RECT 942.725 985.600 942.795 985.670 ;
    END
  END r0_rd_out[436]
  PIN r0_rd_out[437]
    DIRECTION OUTPUT ;
    USE SIGNAL ;
    SHAPE ABUTMENT ;
    PORT
      LAYER metal3 ;
      RECT 942.865 985.600 942.935 985.670 ;
    END
  END r0_rd_out[437]
  PIN r0_rd_out[438]
    DIRECTION OUTPUT ;
    USE SIGNAL ;
    SHAPE ABUTMENT ;
    PORT
      LAYER metal3 ;
      RECT 943.005 985.600 943.075 985.670 ;
    END
  END r0_rd_out[438]
  PIN r0_rd_out[439]
    DIRECTION OUTPUT ;
    USE SIGNAL ;
    SHAPE ABUTMENT ;
    PORT
      LAYER metal3 ;
      RECT 943.145 985.600 943.215 985.670 ;
    END
  END r0_rd_out[439]
  PIN r0_rd_out[440]
    DIRECTION OUTPUT ;
    USE SIGNAL ;
    SHAPE ABUTMENT ;
    PORT
      LAYER metal3 ;
      RECT 943.285 985.600 943.355 985.670 ;
    END
  END r0_rd_out[440]
  PIN r0_rd_out[441]
    DIRECTION OUTPUT ;
    USE SIGNAL ;
    SHAPE ABUTMENT ;
    PORT
      LAYER metal3 ;
      RECT 943.425 985.600 943.495 985.670 ;
    END
  END r0_rd_out[441]
  PIN r0_rd_out[442]
    DIRECTION OUTPUT ;
    USE SIGNAL ;
    SHAPE ABUTMENT ;
    PORT
      LAYER metal3 ;
      RECT 943.565 985.600 943.635 985.670 ;
    END
  END r0_rd_out[442]
  PIN r0_rd_out[443]
    DIRECTION OUTPUT ;
    USE SIGNAL ;
    SHAPE ABUTMENT ;
    PORT
      LAYER metal3 ;
      RECT 943.705 985.600 943.775 985.670 ;
    END
  END r0_rd_out[443]
  PIN r0_rd_out[444]
    DIRECTION OUTPUT ;
    USE SIGNAL ;
    SHAPE ABUTMENT ;
    PORT
      LAYER metal3 ;
      RECT 943.845 985.600 943.915 985.670 ;
    END
  END r0_rd_out[444]
  PIN r0_rd_out[445]
    DIRECTION OUTPUT ;
    USE SIGNAL ;
    SHAPE ABUTMENT ;
    PORT
      LAYER metal3 ;
      RECT 943.985 985.600 944.055 985.670 ;
    END
  END r0_rd_out[445]
  PIN r0_rd_out[446]
    DIRECTION OUTPUT ;
    USE SIGNAL ;
    SHAPE ABUTMENT ;
    PORT
      LAYER metal3 ;
      RECT 944.125 985.600 944.195 985.670 ;
    END
  END r0_rd_out[446]
  PIN r0_rd_out[447]
    DIRECTION OUTPUT ;
    USE SIGNAL ;
    SHAPE ABUTMENT ;
    PORT
      LAYER metal3 ;
      RECT 944.265 985.600 944.335 985.670 ;
    END
  END r0_rd_out[447]
  PIN r0_rd_out[448]
    DIRECTION OUTPUT ;
    USE SIGNAL ;
    SHAPE ABUTMENT ;
    PORT
      LAYER metal3 ;
      RECT 944.405 985.600 944.475 985.670 ;
    END
  END r0_rd_out[448]
  PIN r0_rd_out[449]
    DIRECTION OUTPUT ;
    USE SIGNAL ;
    SHAPE ABUTMENT ;
    PORT
      LAYER metal3 ;
      RECT 944.545 985.600 944.615 985.670 ;
    END
  END r0_rd_out[449]
  PIN r0_rd_out[450]
    DIRECTION OUTPUT ;
    USE SIGNAL ;
    SHAPE ABUTMENT ;
    PORT
      LAYER metal3 ;
      RECT 944.685 985.600 944.755 985.670 ;
    END
  END r0_rd_out[450]
  PIN r0_rd_out[451]
    DIRECTION OUTPUT ;
    USE SIGNAL ;
    SHAPE ABUTMENT ;
    PORT
      LAYER metal3 ;
      RECT 944.825 985.600 944.895 985.670 ;
    END
  END r0_rd_out[451]
  PIN r0_rd_out[452]
    DIRECTION OUTPUT ;
    USE SIGNAL ;
    SHAPE ABUTMENT ;
    PORT
      LAYER metal3 ;
      RECT 944.965 985.600 945.035 985.670 ;
    END
  END r0_rd_out[452]
  PIN r0_rd_out[453]
    DIRECTION OUTPUT ;
    USE SIGNAL ;
    SHAPE ABUTMENT ;
    PORT
      LAYER metal3 ;
      RECT 945.105 985.600 945.175 985.670 ;
    END
  END r0_rd_out[453]
  PIN r0_rd_out[454]
    DIRECTION OUTPUT ;
    USE SIGNAL ;
    SHAPE ABUTMENT ;
    PORT
      LAYER metal3 ;
      RECT 945.245 985.600 945.315 985.670 ;
    END
  END r0_rd_out[454]
  PIN r0_rd_out[455]
    DIRECTION OUTPUT ;
    USE SIGNAL ;
    SHAPE ABUTMENT ;
    PORT
      LAYER metal3 ;
      RECT 945.385 985.600 945.455 985.670 ;
    END
  END r0_rd_out[455]
  PIN r0_rd_out[456]
    DIRECTION OUTPUT ;
    USE SIGNAL ;
    SHAPE ABUTMENT ;
    PORT
      LAYER metal3 ;
      RECT 945.525 985.600 945.595 985.670 ;
    END
  END r0_rd_out[456]
  PIN r0_rd_out[457]
    DIRECTION OUTPUT ;
    USE SIGNAL ;
    SHAPE ABUTMENT ;
    PORT
      LAYER metal3 ;
      RECT 945.665 985.600 945.735 985.670 ;
    END
  END r0_rd_out[457]
  PIN r0_rd_out[458]
    DIRECTION OUTPUT ;
    USE SIGNAL ;
    SHAPE ABUTMENT ;
    PORT
      LAYER metal3 ;
      RECT 945.805 985.600 945.875 985.670 ;
    END
  END r0_rd_out[458]
  PIN r0_rd_out[459]
    DIRECTION OUTPUT ;
    USE SIGNAL ;
    SHAPE ABUTMENT ;
    PORT
      LAYER metal3 ;
      RECT 945.945 985.600 946.015 985.670 ;
    END
  END r0_rd_out[459]
  PIN r0_rd_out[460]
    DIRECTION OUTPUT ;
    USE SIGNAL ;
    SHAPE ABUTMENT ;
    PORT
      LAYER metal3 ;
      RECT 946.085 985.600 946.155 985.670 ;
    END
  END r0_rd_out[460]
  PIN r0_rd_out[461]
    DIRECTION OUTPUT ;
    USE SIGNAL ;
    SHAPE ABUTMENT ;
    PORT
      LAYER metal3 ;
      RECT 946.225 985.600 946.295 985.670 ;
    END
  END r0_rd_out[461]
  PIN r0_rd_out[462]
    DIRECTION OUTPUT ;
    USE SIGNAL ;
    SHAPE ABUTMENT ;
    PORT
      LAYER metal3 ;
      RECT 946.365 985.600 946.435 985.670 ;
    END
  END r0_rd_out[462]
  PIN r0_rd_out[463]
    DIRECTION OUTPUT ;
    USE SIGNAL ;
    SHAPE ABUTMENT ;
    PORT
      LAYER metal3 ;
      RECT 946.505 985.600 946.575 985.670 ;
    END
  END r0_rd_out[463]
  PIN r0_rd_out[464]
    DIRECTION OUTPUT ;
    USE SIGNAL ;
    SHAPE ABUTMENT ;
    PORT
      LAYER metal3 ;
      RECT 946.645 985.600 946.715 985.670 ;
    END
  END r0_rd_out[464]
  PIN r0_rd_out[465]
    DIRECTION OUTPUT ;
    USE SIGNAL ;
    SHAPE ABUTMENT ;
    PORT
      LAYER metal3 ;
      RECT 946.785 985.600 946.855 985.670 ;
    END
  END r0_rd_out[465]
  PIN r0_rd_out[466]
    DIRECTION OUTPUT ;
    USE SIGNAL ;
    SHAPE ABUTMENT ;
    PORT
      LAYER metal3 ;
      RECT 946.925 985.600 946.995 985.670 ;
    END
  END r0_rd_out[466]
  PIN r0_rd_out[467]
    DIRECTION OUTPUT ;
    USE SIGNAL ;
    SHAPE ABUTMENT ;
    PORT
      LAYER metal3 ;
      RECT 947.065 985.600 947.135 985.670 ;
    END
  END r0_rd_out[467]
  PIN r0_rd_out[468]
    DIRECTION OUTPUT ;
    USE SIGNAL ;
    SHAPE ABUTMENT ;
    PORT
      LAYER metal3 ;
      RECT 947.205 985.600 947.275 985.670 ;
    END
  END r0_rd_out[468]
  PIN r0_rd_out[469]
    DIRECTION OUTPUT ;
    USE SIGNAL ;
    SHAPE ABUTMENT ;
    PORT
      LAYER metal3 ;
      RECT 947.345 985.600 947.415 985.670 ;
    END
  END r0_rd_out[469]
  PIN r0_rd_out[470]
    DIRECTION OUTPUT ;
    USE SIGNAL ;
    SHAPE ABUTMENT ;
    PORT
      LAYER metal3 ;
      RECT 947.485 985.600 947.555 985.670 ;
    END
  END r0_rd_out[470]
  PIN r0_rd_out[471]
    DIRECTION OUTPUT ;
    USE SIGNAL ;
    SHAPE ABUTMENT ;
    PORT
      LAYER metal3 ;
      RECT 947.625 985.600 947.695 985.670 ;
    END
  END r0_rd_out[471]
  PIN r0_rd_out[472]
    DIRECTION OUTPUT ;
    USE SIGNAL ;
    SHAPE ABUTMENT ;
    PORT
      LAYER metal3 ;
      RECT 947.765 985.600 947.835 985.670 ;
    END
  END r0_rd_out[472]
  PIN r0_rd_out[473]
    DIRECTION OUTPUT ;
    USE SIGNAL ;
    SHAPE ABUTMENT ;
    PORT
      LAYER metal3 ;
      RECT 947.905 985.600 947.975 985.670 ;
    END
  END r0_rd_out[473]
  PIN r0_rd_out[474]
    DIRECTION OUTPUT ;
    USE SIGNAL ;
    SHAPE ABUTMENT ;
    PORT
      LAYER metal3 ;
      RECT 948.045 985.600 948.115 985.670 ;
    END
  END r0_rd_out[474]
  PIN r0_rd_out[475]
    DIRECTION OUTPUT ;
    USE SIGNAL ;
    SHAPE ABUTMENT ;
    PORT
      LAYER metal3 ;
      RECT 948.185 985.600 948.255 985.670 ;
    END
  END r0_rd_out[475]
  PIN r0_rd_out[476]
    DIRECTION OUTPUT ;
    USE SIGNAL ;
    SHAPE ABUTMENT ;
    PORT
      LAYER metal3 ;
      RECT 948.325 985.600 948.395 985.670 ;
    END
  END r0_rd_out[476]
  PIN r0_rd_out[477]
    DIRECTION OUTPUT ;
    USE SIGNAL ;
    SHAPE ABUTMENT ;
    PORT
      LAYER metal3 ;
      RECT 948.465 985.600 948.535 985.670 ;
    END
  END r0_rd_out[477]
  PIN r0_rd_out[478]
    DIRECTION OUTPUT ;
    USE SIGNAL ;
    SHAPE ABUTMENT ;
    PORT
      LAYER metal3 ;
      RECT 948.605 985.600 948.675 985.670 ;
    END
  END r0_rd_out[478]
  PIN r0_rd_out[479]
    DIRECTION OUTPUT ;
    USE SIGNAL ;
    SHAPE ABUTMENT ;
    PORT
      LAYER metal3 ;
      RECT 948.745 985.600 948.815 985.670 ;
    END
  END r0_rd_out[479]
  PIN r0_rd_out[480]
    DIRECTION OUTPUT ;
    USE SIGNAL ;
    SHAPE ABUTMENT ;
    PORT
      LAYER metal3 ;
      RECT 948.885 985.600 948.955 985.670 ;
    END
  END r0_rd_out[480]
  PIN r0_rd_out[481]
    DIRECTION OUTPUT ;
    USE SIGNAL ;
    SHAPE ABUTMENT ;
    PORT
      LAYER metal3 ;
      RECT 949.025 985.600 949.095 985.670 ;
    END
  END r0_rd_out[481]
  PIN r0_rd_out[482]
    DIRECTION OUTPUT ;
    USE SIGNAL ;
    SHAPE ABUTMENT ;
    PORT
      LAYER metal3 ;
      RECT 949.165 985.600 949.235 985.670 ;
    END
  END r0_rd_out[482]
  PIN r0_rd_out[483]
    DIRECTION OUTPUT ;
    USE SIGNAL ;
    SHAPE ABUTMENT ;
    PORT
      LAYER metal3 ;
      RECT 949.305 985.600 949.375 985.670 ;
    END
  END r0_rd_out[483]
  PIN r0_rd_out[484]
    DIRECTION OUTPUT ;
    USE SIGNAL ;
    SHAPE ABUTMENT ;
    PORT
      LAYER metal3 ;
      RECT 949.445 985.600 949.515 985.670 ;
    END
  END r0_rd_out[484]
  PIN r0_rd_out[485]
    DIRECTION OUTPUT ;
    USE SIGNAL ;
    SHAPE ABUTMENT ;
    PORT
      LAYER metal3 ;
      RECT 949.585 985.600 949.655 985.670 ;
    END
  END r0_rd_out[485]
  PIN r0_rd_out[486]
    DIRECTION OUTPUT ;
    USE SIGNAL ;
    SHAPE ABUTMENT ;
    PORT
      LAYER metal3 ;
      RECT 949.725 985.600 949.795 985.670 ;
    END
  END r0_rd_out[486]
  PIN r0_rd_out[487]
    DIRECTION OUTPUT ;
    USE SIGNAL ;
    SHAPE ABUTMENT ;
    PORT
      LAYER metal3 ;
      RECT 949.865 985.600 949.935 985.670 ;
    END
  END r0_rd_out[487]
  PIN r0_rd_out[488]
    DIRECTION OUTPUT ;
    USE SIGNAL ;
    SHAPE ABUTMENT ;
    PORT
      LAYER metal3 ;
      RECT 950.005 985.600 950.075 985.670 ;
    END
  END r0_rd_out[488]
  PIN r0_rd_out[489]
    DIRECTION OUTPUT ;
    USE SIGNAL ;
    SHAPE ABUTMENT ;
    PORT
      LAYER metal3 ;
      RECT 950.145 985.600 950.215 985.670 ;
    END
  END r0_rd_out[489]
  PIN r0_rd_out[490]
    DIRECTION OUTPUT ;
    USE SIGNAL ;
    SHAPE ABUTMENT ;
    PORT
      LAYER metal3 ;
      RECT 950.285 985.600 950.355 985.670 ;
    END
  END r0_rd_out[490]
  PIN r0_rd_out[491]
    DIRECTION OUTPUT ;
    USE SIGNAL ;
    SHAPE ABUTMENT ;
    PORT
      LAYER metal3 ;
      RECT 950.425 985.600 950.495 985.670 ;
    END
  END r0_rd_out[491]
  PIN r0_rd_out[492]
    DIRECTION OUTPUT ;
    USE SIGNAL ;
    SHAPE ABUTMENT ;
    PORT
      LAYER metal3 ;
      RECT 950.565 985.600 950.635 985.670 ;
    END
  END r0_rd_out[492]
  PIN r0_rd_out[493]
    DIRECTION OUTPUT ;
    USE SIGNAL ;
    SHAPE ABUTMENT ;
    PORT
      LAYER metal3 ;
      RECT 950.705 985.600 950.775 985.670 ;
    END
  END r0_rd_out[493]
  PIN r0_rd_out[494]
    DIRECTION OUTPUT ;
    USE SIGNAL ;
    SHAPE ABUTMENT ;
    PORT
      LAYER metal3 ;
      RECT 950.845 985.600 950.915 985.670 ;
    END
  END r0_rd_out[494]
  PIN r0_rd_out[495]
    DIRECTION OUTPUT ;
    USE SIGNAL ;
    SHAPE ABUTMENT ;
    PORT
      LAYER metal3 ;
      RECT 950.985 985.600 951.055 985.670 ;
    END
  END r0_rd_out[495]
  PIN r0_rd_out[496]
    DIRECTION OUTPUT ;
    USE SIGNAL ;
    SHAPE ABUTMENT ;
    PORT
      LAYER metal3 ;
      RECT 951.125 985.600 951.195 985.670 ;
    END
  END r0_rd_out[496]
  PIN r0_rd_out[497]
    DIRECTION OUTPUT ;
    USE SIGNAL ;
    SHAPE ABUTMENT ;
    PORT
      LAYER metal3 ;
      RECT 951.265 985.600 951.335 985.670 ;
    END
  END r0_rd_out[497]
  PIN r0_rd_out[498]
    DIRECTION OUTPUT ;
    USE SIGNAL ;
    SHAPE ABUTMENT ;
    PORT
      LAYER metal3 ;
      RECT 951.405 985.600 951.475 985.670 ;
    END
  END r0_rd_out[498]
  PIN r0_rd_out[499]
    DIRECTION OUTPUT ;
    USE SIGNAL ;
    SHAPE ABUTMENT ;
    PORT
      LAYER metal3 ;
      RECT 951.545 985.600 951.615 985.670 ;
    END
  END r0_rd_out[499]
  PIN r0_rd_out[500]
    DIRECTION OUTPUT ;
    USE SIGNAL ;
    SHAPE ABUTMENT ;
    PORT
      LAYER metal3 ;
      RECT 951.685 985.600 951.755 985.670 ;
    END
  END r0_rd_out[500]
  PIN r0_rd_out[501]
    DIRECTION OUTPUT ;
    USE SIGNAL ;
    SHAPE ABUTMENT ;
    PORT
      LAYER metal3 ;
      RECT 951.825 985.600 951.895 985.670 ;
    END
  END r0_rd_out[501]
  PIN r0_rd_out[502]
    DIRECTION OUTPUT ;
    USE SIGNAL ;
    SHAPE ABUTMENT ;
    PORT
      LAYER metal3 ;
      RECT 951.965 985.600 952.035 985.670 ;
    END
  END r0_rd_out[502]
  PIN r0_rd_out[503]
    DIRECTION OUTPUT ;
    USE SIGNAL ;
    SHAPE ABUTMENT ;
    PORT
      LAYER metal3 ;
      RECT 952.105 985.600 952.175 985.670 ;
    END
  END r0_rd_out[503]
  PIN r0_rd_out[504]
    DIRECTION OUTPUT ;
    USE SIGNAL ;
    SHAPE ABUTMENT ;
    PORT
      LAYER metal3 ;
      RECT 952.245 985.600 952.315 985.670 ;
    END
  END r0_rd_out[504]
  PIN r0_rd_out[505]
    DIRECTION OUTPUT ;
    USE SIGNAL ;
    SHAPE ABUTMENT ;
    PORT
      LAYER metal3 ;
      RECT 952.385 985.600 952.455 985.670 ;
    END
  END r0_rd_out[505]
  PIN r0_rd_out[506]
    DIRECTION OUTPUT ;
    USE SIGNAL ;
    SHAPE ABUTMENT ;
    PORT
      LAYER metal3 ;
      RECT 952.525 985.600 952.595 985.670 ;
    END
  END r0_rd_out[506]
  PIN r0_rd_out[507]
    DIRECTION OUTPUT ;
    USE SIGNAL ;
    SHAPE ABUTMENT ;
    PORT
      LAYER metal3 ;
      RECT 952.665 985.600 952.735 985.670 ;
    END
  END r0_rd_out[507]
  PIN r0_rd_out[508]
    DIRECTION OUTPUT ;
    USE SIGNAL ;
    SHAPE ABUTMENT ;
    PORT
      LAYER metal3 ;
      RECT 952.805 985.600 952.875 985.670 ;
    END
  END r0_rd_out[508]
  PIN r0_rd_out[509]
    DIRECTION OUTPUT ;
    USE SIGNAL ;
    SHAPE ABUTMENT ;
    PORT
      LAYER metal3 ;
      RECT 952.945 985.600 953.015 985.670 ;
    END
  END r0_rd_out[509]
  PIN r0_rd_out[510]
    DIRECTION OUTPUT ;
    USE SIGNAL ;
    SHAPE ABUTMENT ;
    PORT
      LAYER metal3 ;
      RECT 953.085 985.600 953.155 985.670 ;
    END
  END r0_rd_out[510]
  PIN r0_rd_out[511]
    DIRECTION OUTPUT ;
    USE SIGNAL ;
    SHAPE ABUTMENT ;
    PORT
      LAYER metal3 ;
      RECT 953.225 985.600 953.295 985.670 ;
    END
  END r0_rd_out[511]
  PIN w0_addr_in[0]
    DIRECTION INPUT ;
    USE SIGNAL ;
    SHAPE ABUTMENT ;
    PORT
      LAYER metal3 ;
      RECT 1835.190 491.820 1835.260 491.890 ;
    END
  END w0_addr_in[0]
  PIN w0_addr_in[1]
    DIRECTION INPUT ;
    USE SIGNAL ;
    SHAPE ABUTMENT ;
    PORT
      LAYER metal3 ;
      RECT 1835.190 491.960 1835.260 492.030 ;
    END
  END w0_addr_in[1]
  PIN w0_addr_in[2]
    DIRECTION INPUT ;
    USE SIGNAL ;
    SHAPE ABUTMENT ;
    PORT
      LAYER metal3 ;
      RECT 1835.190 492.100 1835.260 492.170 ;
    END
  END w0_addr_in[2]
  PIN w0_addr_in[3]
    DIRECTION INPUT ;
    USE SIGNAL ;
    SHAPE ABUTMENT ;
    PORT
      LAYER metal3 ;
      RECT 1835.190 492.240 1835.260 492.310 ;
    END
  END w0_addr_in[3]
  PIN w0_addr_in[4]
    DIRECTION INPUT ;
    USE SIGNAL ;
    SHAPE ABUTMENT ;
    PORT
      LAYER metal3 ;
      RECT 1835.190 492.380 1835.260 492.450 ;
    END
  END w0_addr_in[4]
  PIN w0_addr_in[5]
    DIRECTION INPUT ;
    USE SIGNAL ;
    SHAPE ABUTMENT ;
    PORT
      LAYER metal3 ;
      RECT 1835.190 492.520 1835.260 492.590 ;
    END
  END w0_addr_in[5]
  PIN w0_addr_in[6]
    DIRECTION INPUT ;
    USE SIGNAL ;
    SHAPE ABUTMENT ;
    PORT
      LAYER metal3 ;
      RECT 1835.190 492.660 1835.260 492.730 ;
    END
  END w0_addr_in[6]
  PIN w0_addr_in[7]
    DIRECTION INPUT ;
    USE SIGNAL ;
    SHAPE ABUTMENT ;
    PORT
      LAYER metal3 ;
      RECT 1835.190 492.800 1835.260 492.870 ;
    END
  END w0_addr_in[7]
  PIN w0_addr_in[8]
    DIRECTION INPUT ;
    USE SIGNAL ;
    SHAPE ABUTMENT ;
    PORT
      LAYER metal3 ;
      RECT 1835.190 492.940 1835.260 493.010 ;
    END
  END w0_addr_in[8]
  PIN w0_addr_in[9]
    DIRECTION INPUT ;
    USE SIGNAL ;
    SHAPE ABUTMENT ;
    PORT
      LAYER metal3 ;
      RECT 1835.190 493.080 1835.260 493.150 ;
    END
  END w0_addr_in[9]
  PIN w0_we_in
    DIRECTION INPUT ;
    USE SIGNAL ;
    SHAPE ABUTMENT ;
    PORT
      LAYER metal3 ;
      RECT 1835.190 493.360 1835.260 493.430 ;
    END
  END w0_we_in
  PIN w0_ce_in
    DIRECTION INPUT ;
    USE SIGNAL ;
    SHAPE ABUTMENT ;
    PORT
      LAYER metal3 ;
      RECT 1835.190 493.500 1835.260 493.570 ;
    END
  END w0_ce_in
  PIN w0_clk
    DIRECTION INPUT ;
    USE SIGNAL ;
    SHAPE ABUTMENT ;
    PORT
      LAYER metal3 ;
      RECT 1835.190 493.640 1835.260 493.710 ;
    END
  END w0_clk
  PIN w0_wd_in[0]
    DIRECTION INPUT ;
    USE SIGNAL ;
    SHAPE ABUTMENT ;
    PORT
      LAYER metal3 ;
      RECT 881.685 0.000 881.755 0.070 ;
    END
  END w0_wd_in[0]
  PIN w0_wd_in[1]
    DIRECTION INPUT ;
    USE SIGNAL ;
    SHAPE ABUTMENT ;
    PORT
      LAYER metal3 ;
      RECT 881.825 0.000 881.895 0.070 ;
    END
  END w0_wd_in[1]
  PIN w0_wd_in[2]
    DIRECTION INPUT ;
    USE SIGNAL ;
    SHAPE ABUTMENT ;
    PORT
      LAYER metal3 ;
      RECT 881.965 0.000 882.035 0.070 ;
    END
  END w0_wd_in[2]
  PIN w0_wd_in[3]
    DIRECTION INPUT ;
    USE SIGNAL ;
    SHAPE ABUTMENT ;
    PORT
      LAYER metal3 ;
      RECT 882.105 0.000 882.175 0.070 ;
    END
  END w0_wd_in[3]
  PIN w0_wd_in[4]
    DIRECTION INPUT ;
    USE SIGNAL ;
    SHAPE ABUTMENT ;
    PORT
      LAYER metal3 ;
      RECT 882.245 0.000 882.315 0.070 ;
    END
  END w0_wd_in[4]
  PIN w0_wd_in[5]
    DIRECTION INPUT ;
    USE SIGNAL ;
    SHAPE ABUTMENT ;
    PORT
      LAYER metal3 ;
      RECT 882.385 0.000 882.455 0.070 ;
    END
  END w0_wd_in[5]
  PIN w0_wd_in[6]
    DIRECTION INPUT ;
    USE SIGNAL ;
    SHAPE ABUTMENT ;
    PORT
      LAYER metal3 ;
      RECT 882.525 0.000 882.595 0.070 ;
    END
  END w0_wd_in[6]
  PIN w0_wd_in[7]
    DIRECTION INPUT ;
    USE SIGNAL ;
    SHAPE ABUTMENT ;
    PORT
      LAYER metal3 ;
      RECT 882.665 0.000 882.735 0.070 ;
    END
  END w0_wd_in[7]
  PIN w0_wd_in[8]
    DIRECTION INPUT ;
    USE SIGNAL ;
    SHAPE ABUTMENT ;
    PORT
      LAYER metal3 ;
      RECT 882.805 0.000 882.875 0.070 ;
    END
  END w0_wd_in[8]
  PIN w0_wd_in[9]
    DIRECTION INPUT ;
    USE SIGNAL ;
    SHAPE ABUTMENT ;
    PORT
      LAYER metal3 ;
      RECT 882.945 0.000 883.015 0.070 ;
    END
  END w0_wd_in[9]
  PIN w0_wd_in[10]
    DIRECTION INPUT ;
    USE SIGNAL ;
    SHAPE ABUTMENT ;
    PORT
      LAYER metal3 ;
      RECT 883.085 0.000 883.155 0.070 ;
    END
  END w0_wd_in[10]
  PIN w0_wd_in[11]
    DIRECTION INPUT ;
    USE SIGNAL ;
    SHAPE ABUTMENT ;
    PORT
      LAYER metal3 ;
      RECT 883.225 0.000 883.295 0.070 ;
    END
  END w0_wd_in[11]
  PIN w0_wd_in[12]
    DIRECTION INPUT ;
    USE SIGNAL ;
    SHAPE ABUTMENT ;
    PORT
      LAYER metal3 ;
      RECT 883.365 0.000 883.435 0.070 ;
    END
  END w0_wd_in[12]
  PIN w0_wd_in[13]
    DIRECTION INPUT ;
    USE SIGNAL ;
    SHAPE ABUTMENT ;
    PORT
      LAYER metal3 ;
      RECT 883.505 0.000 883.575 0.070 ;
    END
  END w0_wd_in[13]
  PIN w0_wd_in[14]
    DIRECTION INPUT ;
    USE SIGNAL ;
    SHAPE ABUTMENT ;
    PORT
      LAYER metal3 ;
      RECT 883.645 0.000 883.715 0.070 ;
    END
  END w0_wd_in[14]
  PIN w0_wd_in[15]
    DIRECTION INPUT ;
    USE SIGNAL ;
    SHAPE ABUTMENT ;
    PORT
      LAYER metal3 ;
      RECT 883.785 0.000 883.855 0.070 ;
    END
  END w0_wd_in[15]
  PIN w0_wd_in[16]
    DIRECTION INPUT ;
    USE SIGNAL ;
    SHAPE ABUTMENT ;
    PORT
      LAYER metal3 ;
      RECT 883.925 0.000 883.995 0.070 ;
    END
  END w0_wd_in[16]
  PIN w0_wd_in[17]
    DIRECTION INPUT ;
    USE SIGNAL ;
    SHAPE ABUTMENT ;
    PORT
      LAYER metal3 ;
      RECT 884.065 0.000 884.135 0.070 ;
    END
  END w0_wd_in[17]
  PIN w0_wd_in[18]
    DIRECTION INPUT ;
    USE SIGNAL ;
    SHAPE ABUTMENT ;
    PORT
      LAYER metal3 ;
      RECT 884.205 0.000 884.275 0.070 ;
    END
  END w0_wd_in[18]
  PIN w0_wd_in[19]
    DIRECTION INPUT ;
    USE SIGNAL ;
    SHAPE ABUTMENT ;
    PORT
      LAYER metal3 ;
      RECT 884.345 0.000 884.415 0.070 ;
    END
  END w0_wd_in[19]
  PIN w0_wd_in[20]
    DIRECTION INPUT ;
    USE SIGNAL ;
    SHAPE ABUTMENT ;
    PORT
      LAYER metal3 ;
      RECT 884.485 0.000 884.555 0.070 ;
    END
  END w0_wd_in[20]
  PIN w0_wd_in[21]
    DIRECTION INPUT ;
    USE SIGNAL ;
    SHAPE ABUTMENT ;
    PORT
      LAYER metal3 ;
      RECT 884.625 0.000 884.695 0.070 ;
    END
  END w0_wd_in[21]
  PIN w0_wd_in[22]
    DIRECTION INPUT ;
    USE SIGNAL ;
    SHAPE ABUTMENT ;
    PORT
      LAYER metal3 ;
      RECT 884.765 0.000 884.835 0.070 ;
    END
  END w0_wd_in[22]
  PIN w0_wd_in[23]
    DIRECTION INPUT ;
    USE SIGNAL ;
    SHAPE ABUTMENT ;
    PORT
      LAYER metal3 ;
      RECT 884.905 0.000 884.975 0.070 ;
    END
  END w0_wd_in[23]
  PIN w0_wd_in[24]
    DIRECTION INPUT ;
    USE SIGNAL ;
    SHAPE ABUTMENT ;
    PORT
      LAYER metal3 ;
      RECT 885.045 0.000 885.115 0.070 ;
    END
  END w0_wd_in[24]
  PIN w0_wd_in[25]
    DIRECTION INPUT ;
    USE SIGNAL ;
    SHAPE ABUTMENT ;
    PORT
      LAYER metal3 ;
      RECT 885.185 0.000 885.255 0.070 ;
    END
  END w0_wd_in[25]
  PIN w0_wd_in[26]
    DIRECTION INPUT ;
    USE SIGNAL ;
    SHAPE ABUTMENT ;
    PORT
      LAYER metal3 ;
      RECT 885.325 0.000 885.395 0.070 ;
    END
  END w0_wd_in[26]
  PIN w0_wd_in[27]
    DIRECTION INPUT ;
    USE SIGNAL ;
    SHAPE ABUTMENT ;
    PORT
      LAYER metal3 ;
      RECT 885.465 0.000 885.535 0.070 ;
    END
  END w0_wd_in[27]
  PIN w0_wd_in[28]
    DIRECTION INPUT ;
    USE SIGNAL ;
    SHAPE ABUTMENT ;
    PORT
      LAYER metal3 ;
      RECT 885.605 0.000 885.675 0.070 ;
    END
  END w0_wd_in[28]
  PIN w0_wd_in[29]
    DIRECTION INPUT ;
    USE SIGNAL ;
    SHAPE ABUTMENT ;
    PORT
      LAYER metal3 ;
      RECT 885.745 0.000 885.815 0.070 ;
    END
  END w0_wd_in[29]
  PIN w0_wd_in[30]
    DIRECTION INPUT ;
    USE SIGNAL ;
    SHAPE ABUTMENT ;
    PORT
      LAYER metal3 ;
      RECT 885.885 0.000 885.955 0.070 ;
    END
  END w0_wd_in[30]
  PIN w0_wd_in[31]
    DIRECTION INPUT ;
    USE SIGNAL ;
    SHAPE ABUTMENT ;
    PORT
      LAYER metal3 ;
      RECT 886.025 0.000 886.095 0.070 ;
    END
  END w0_wd_in[31]
  PIN w0_wd_in[32]
    DIRECTION INPUT ;
    USE SIGNAL ;
    SHAPE ABUTMENT ;
    PORT
      LAYER metal3 ;
      RECT 886.165 0.000 886.235 0.070 ;
    END
  END w0_wd_in[32]
  PIN w0_wd_in[33]
    DIRECTION INPUT ;
    USE SIGNAL ;
    SHAPE ABUTMENT ;
    PORT
      LAYER metal3 ;
      RECT 886.305 0.000 886.375 0.070 ;
    END
  END w0_wd_in[33]
  PIN w0_wd_in[34]
    DIRECTION INPUT ;
    USE SIGNAL ;
    SHAPE ABUTMENT ;
    PORT
      LAYER metal3 ;
      RECT 886.445 0.000 886.515 0.070 ;
    END
  END w0_wd_in[34]
  PIN w0_wd_in[35]
    DIRECTION INPUT ;
    USE SIGNAL ;
    SHAPE ABUTMENT ;
    PORT
      LAYER metal3 ;
      RECT 886.585 0.000 886.655 0.070 ;
    END
  END w0_wd_in[35]
  PIN w0_wd_in[36]
    DIRECTION INPUT ;
    USE SIGNAL ;
    SHAPE ABUTMENT ;
    PORT
      LAYER metal3 ;
      RECT 886.725 0.000 886.795 0.070 ;
    END
  END w0_wd_in[36]
  PIN w0_wd_in[37]
    DIRECTION INPUT ;
    USE SIGNAL ;
    SHAPE ABUTMENT ;
    PORT
      LAYER metal3 ;
      RECT 886.865 0.000 886.935 0.070 ;
    END
  END w0_wd_in[37]
  PIN w0_wd_in[38]
    DIRECTION INPUT ;
    USE SIGNAL ;
    SHAPE ABUTMENT ;
    PORT
      LAYER metal3 ;
      RECT 887.005 0.000 887.075 0.070 ;
    END
  END w0_wd_in[38]
  PIN w0_wd_in[39]
    DIRECTION INPUT ;
    USE SIGNAL ;
    SHAPE ABUTMENT ;
    PORT
      LAYER metal3 ;
      RECT 887.145 0.000 887.215 0.070 ;
    END
  END w0_wd_in[39]
  PIN w0_wd_in[40]
    DIRECTION INPUT ;
    USE SIGNAL ;
    SHAPE ABUTMENT ;
    PORT
      LAYER metal3 ;
      RECT 887.285 0.000 887.355 0.070 ;
    END
  END w0_wd_in[40]
  PIN w0_wd_in[41]
    DIRECTION INPUT ;
    USE SIGNAL ;
    SHAPE ABUTMENT ;
    PORT
      LAYER metal3 ;
      RECT 887.425 0.000 887.495 0.070 ;
    END
  END w0_wd_in[41]
  PIN w0_wd_in[42]
    DIRECTION INPUT ;
    USE SIGNAL ;
    SHAPE ABUTMENT ;
    PORT
      LAYER metal3 ;
      RECT 887.565 0.000 887.635 0.070 ;
    END
  END w0_wd_in[42]
  PIN w0_wd_in[43]
    DIRECTION INPUT ;
    USE SIGNAL ;
    SHAPE ABUTMENT ;
    PORT
      LAYER metal3 ;
      RECT 887.705 0.000 887.775 0.070 ;
    END
  END w0_wd_in[43]
  PIN w0_wd_in[44]
    DIRECTION INPUT ;
    USE SIGNAL ;
    SHAPE ABUTMENT ;
    PORT
      LAYER metal3 ;
      RECT 887.845 0.000 887.915 0.070 ;
    END
  END w0_wd_in[44]
  PIN w0_wd_in[45]
    DIRECTION INPUT ;
    USE SIGNAL ;
    SHAPE ABUTMENT ;
    PORT
      LAYER metal3 ;
      RECT 887.985 0.000 888.055 0.070 ;
    END
  END w0_wd_in[45]
  PIN w0_wd_in[46]
    DIRECTION INPUT ;
    USE SIGNAL ;
    SHAPE ABUTMENT ;
    PORT
      LAYER metal3 ;
      RECT 888.125 0.000 888.195 0.070 ;
    END
  END w0_wd_in[46]
  PIN w0_wd_in[47]
    DIRECTION INPUT ;
    USE SIGNAL ;
    SHAPE ABUTMENT ;
    PORT
      LAYER metal3 ;
      RECT 888.265 0.000 888.335 0.070 ;
    END
  END w0_wd_in[47]
  PIN w0_wd_in[48]
    DIRECTION INPUT ;
    USE SIGNAL ;
    SHAPE ABUTMENT ;
    PORT
      LAYER metal3 ;
      RECT 888.405 0.000 888.475 0.070 ;
    END
  END w0_wd_in[48]
  PIN w0_wd_in[49]
    DIRECTION INPUT ;
    USE SIGNAL ;
    SHAPE ABUTMENT ;
    PORT
      LAYER metal3 ;
      RECT 888.545 0.000 888.615 0.070 ;
    END
  END w0_wd_in[49]
  PIN w0_wd_in[50]
    DIRECTION INPUT ;
    USE SIGNAL ;
    SHAPE ABUTMENT ;
    PORT
      LAYER metal3 ;
      RECT 888.685 0.000 888.755 0.070 ;
    END
  END w0_wd_in[50]
  PIN w0_wd_in[51]
    DIRECTION INPUT ;
    USE SIGNAL ;
    SHAPE ABUTMENT ;
    PORT
      LAYER metal3 ;
      RECT 888.825 0.000 888.895 0.070 ;
    END
  END w0_wd_in[51]
  PIN w0_wd_in[52]
    DIRECTION INPUT ;
    USE SIGNAL ;
    SHAPE ABUTMENT ;
    PORT
      LAYER metal3 ;
      RECT 888.965 0.000 889.035 0.070 ;
    END
  END w0_wd_in[52]
  PIN w0_wd_in[53]
    DIRECTION INPUT ;
    USE SIGNAL ;
    SHAPE ABUTMENT ;
    PORT
      LAYER metal3 ;
      RECT 889.105 0.000 889.175 0.070 ;
    END
  END w0_wd_in[53]
  PIN w0_wd_in[54]
    DIRECTION INPUT ;
    USE SIGNAL ;
    SHAPE ABUTMENT ;
    PORT
      LAYER metal3 ;
      RECT 889.245 0.000 889.315 0.070 ;
    END
  END w0_wd_in[54]
  PIN w0_wd_in[55]
    DIRECTION INPUT ;
    USE SIGNAL ;
    SHAPE ABUTMENT ;
    PORT
      LAYER metal3 ;
      RECT 889.385 0.000 889.455 0.070 ;
    END
  END w0_wd_in[55]
  PIN w0_wd_in[56]
    DIRECTION INPUT ;
    USE SIGNAL ;
    SHAPE ABUTMENT ;
    PORT
      LAYER metal3 ;
      RECT 889.525 0.000 889.595 0.070 ;
    END
  END w0_wd_in[56]
  PIN w0_wd_in[57]
    DIRECTION INPUT ;
    USE SIGNAL ;
    SHAPE ABUTMENT ;
    PORT
      LAYER metal3 ;
      RECT 889.665 0.000 889.735 0.070 ;
    END
  END w0_wd_in[57]
  PIN w0_wd_in[58]
    DIRECTION INPUT ;
    USE SIGNAL ;
    SHAPE ABUTMENT ;
    PORT
      LAYER metal3 ;
      RECT 889.805 0.000 889.875 0.070 ;
    END
  END w0_wd_in[58]
  PIN w0_wd_in[59]
    DIRECTION INPUT ;
    USE SIGNAL ;
    SHAPE ABUTMENT ;
    PORT
      LAYER metal3 ;
      RECT 889.945 0.000 890.015 0.070 ;
    END
  END w0_wd_in[59]
  PIN w0_wd_in[60]
    DIRECTION INPUT ;
    USE SIGNAL ;
    SHAPE ABUTMENT ;
    PORT
      LAYER metal3 ;
      RECT 890.085 0.000 890.155 0.070 ;
    END
  END w0_wd_in[60]
  PIN w0_wd_in[61]
    DIRECTION INPUT ;
    USE SIGNAL ;
    SHAPE ABUTMENT ;
    PORT
      LAYER metal3 ;
      RECT 890.225 0.000 890.295 0.070 ;
    END
  END w0_wd_in[61]
  PIN w0_wd_in[62]
    DIRECTION INPUT ;
    USE SIGNAL ;
    SHAPE ABUTMENT ;
    PORT
      LAYER metal3 ;
      RECT 890.365 0.000 890.435 0.070 ;
    END
  END w0_wd_in[62]
  PIN w0_wd_in[63]
    DIRECTION INPUT ;
    USE SIGNAL ;
    SHAPE ABUTMENT ;
    PORT
      LAYER metal3 ;
      RECT 890.505 0.000 890.575 0.070 ;
    END
  END w0_wd_in[63]
  PIN w0_wd_in[64]
    DIRECTION INPUT ;
    USE SIGNAL ;
    SHAPE ABUTMENT ;
    PORT
      LAYER metal3 ;
      RECT 890.645 0.000 890.715 0.070 ;
    END
  END w0_wd_in[64]
  PIN w0_wd_in[65]
    DIRECTION INPUT ;
    USE SIGNAL ;
    SHAPE ABUTMENT ;
    PORT
      LAYER metal3 ;
      RECT 890.785 0.000 890.855 0.070 ;
    END
  END w0_wd_in[65]
  PIN w0_wd_in[66]
    DIRECTION INPUT ;
    USE SIGNAL ;
    SHAPE ABUTMENT ;
    PORT
      LAYER metal3 ;
      RECT 890.925 0.000 890.995 0.070 ;
    END
  END w0_wd_in[66]
  PIN w0_wd_in[67]
    DIRECTION INPUT ;
    USE SIGNAL ;
    SHAPE ABUTMENT ;
    PORT
      LAYER metal3 ;
      RECT 891.065 0.000 891.135 0.070 ;
    END
  END w0_wd_in[67]
  PIN w0_wd_in[68]
    DIRECTION INPUT ;
    USE SIGNAL ;
    SHAPE ABUTMENT ;
    PORT
      LAYER metal3 ;
      RECT 891.205 0.000 891.275 0.070 ;
    END
  END w0_wd_in[68]
  PIN w0_wd_in[69]
    DIRECTION INPUT ;
    USE SIGNAL ;
    SHAPE ABUTMENT ;
    PORT
      LAYER metal3 ;
      RECT 891.345 0.000 891.415 0.070 ;
    END
  END w0_wd_in[69]
  PIN w0_wd_in[70]
    DIRECTION INPUT ;
    USE SIGNAL ;
    SHAPE ABUTMENT ;
    PORT
      LAYER metal3 ;
      RECT 891.485 0.000 891.555 0.070 ;
    END
  END w0_wd_in[70]
  PIN w0_wd_in[71]
    DIRECTION INPUT ;
    USE SIGNAL ;
    SHAPE ABUTMENT ;
    PORT
      LAYER metal3 ;
      RECT 891.625 0.000 891.695 0.070 ;
    END
  END w0_wd_in[71]
  PIN w0_wd_in[72]
    DIRECTION INPUT ;
    USE SIGNAL ;
    SHAPE ABUTMENT ;
    PORT
      LAYER metal3 ;
      RECT 891.765 0.000 891.835 0.070 ;
    END
  END w0_wd_in[72]
  PIN w0_wd_in[73]
    DIRECTION INPUT ;
    USE SIGNAL ;
    SHAPE ABUTMENT ;
    PORT
      LAYER metal3 ;
      RECT 891.905 0.000 891.975 0.070 ;
    END
  END w0_wd_in[73]
  PIN w0_wd_in[74]
    DIRECTION INPUT ;
    USE SIGNAL ;
    SHAPE ABUTMENT ;
    PORT
      LAYER metal3 ;
      RECT 892.045 0.000 892.115 0.070 ;
    END
  END w0_wd_in[74]
  PIN w0_wd_in[75]
    DIRECTION INPUT ;
    USE SIGNAL ;
    SHAPE ABUTMENT ;
    PORT
      LAYER metal3 ;
      RECT 892.185 0.000 892.255 0.070 ;
    END
  END w0_wd_in[75]
  PIN w0_wd_in[76]
    DIRECTION INPUT ;
    USE SIGNAL ;
    SHAPE ABUTMENT ;
    PORT
      LAYER metal3 ;
      RECT 892.325 0.000 892.395 0.070 ;
    END
  END w0_wd_in[76]
  PIN w0_wd_in[77]
    DIRECTION INPUT ;
    USE SIGNAL ;
    SHAPE ABUTMENT ;
    PORT
      LAYER metal3 ;
      RECT 892.465 0.000 892.535 0.070 ;
    END
  END w0_wd_in[77]
  PIN w0_wd_in[78]
    DIRECTION INPUT ;
    USE SIGNAL ;
    SHAPE ABUTMENT ;
    PORT
      LAYER metal3 ;
      RECT 892.605 0.000 892.675 0.070 ;
    END
  END w0_wd_in[78]
  PIN w0_wd_in[79]
    DIRECTION INPUT ;
    USE SIGNAL ;
    SHAPE ABUTMENT ;
    PORT
      LAYER metal3 ;
      RECT 892.745 0.000 892.815 0.070 ;
    END
  END w0_wd_in[79]
  PIN w0_wd_in[80]
    DIRECTION INPUT ;
    USE SIGNAL ;
    SHAPE ABUTMENT ;
    PORT
      LAYER metal3 ;
      RECT 892.885 0.000 892.955 0.070 ;
    END
  END w0_wd_in[80]
  PIN w0_wd_in[81]
    DIRECTION INPUT ;
    USE SIGNAL ;
    SHAPE ABUTMENT ;
    PORT
      LAYER metal3 ;
      RECT 893.025 0.000 893.095 0.070 ;
    END
  END w0_wd_in[81]
  PIN w0_wd_in[82]
    DIRECTION INPUT ;
    USE SIGNAL ;
    SHAPE ABUTMENT ;
    PORT
      LAYER metal3 ;
      RECT 893.165 0.000 893.235 0.070 ;
    END
  END w0_wd_in[82]
  PIN w0_wd_in[83]
    DIRECTION INPUT ;
    USE SIGNAL ;
    SHAPE ABUTMENT ;
    PORT
      LAYER metal3 ;
      RECT 893.305 0.000 893.375 0.070 ;
    END
  END w0_wd_in[83]
  PIN w0_wd_in[84]
    DIRECTION INPUT ;
    USE SIGNAL ;
    SHAPE ABUTMENT ;
    PORT
      LAYER metal3 ;
      RECT 893.445 0.000 893.515 0.070 ;
    END
  END w0_wd_in[84]
  PIN w0_wd_in[85]
    DIRECTION INPUT ;
    USE SIGNAL ;
    SHAPE ABUTMENT ;
    PORT
      LAYER metal3 ;
      RECT 893.585 0.000 893.655 0.070 ;
    END
  END w0_wd_in[85]
  PIN w0_wd_in[86]
    DIRECTION INPUT ;
    USE SIGNAL ;
    SHAPE ABUTMENT ;
    PORT
      LAYER metal3 ;
      RECT 893.725 0.000 893.795 0.070 ;
    END
  END w0_wd_in[86]
  PIN w0_wd_in[87]
    DIRECTION INPUT ;
    USE SIGNAL ;
    SHAPE ABUTMENT ;
    PORT
      LAYER metal3 ;
      RECT 893.865 0.000 893.935 0.070 ;
    END
  END w0_wd_in[87]
  PIN w0_wd_in[88]
    DIRECTION INPUT ;
    USE SIGNAL ;
    SHAPE ABUTMENT ;
    PORT
      LAYER metal3 ;
      RECT 894.005 0.000 894.075 0.070 ;
    END
  END w0_wd_in[88]
  PIN w0_wd_in[89]
    DIRECTION INPUT ;
    USE SIGNAL ;
    SHAPE ABUTMENT ;
    PORT
      LAYER metal3 ;
      RECT 894.145 0.000 894.215 0.070 ;
    END
  END w0_wd_in[89]
  PIN w0_wd_in[90]
    DIRECTION INPUT ;
    USE SIGNAL ;
    SHAPE ABUTMENT ;
    PORT
      LAYER metal3 ;
      RECT 894.285 0.000 894.355 0.070 ;
    END
  END w0_wd_in[90]
  PIN w0_wd_in[91]
    DIRECTION INPUT ;
    USE SIGNAL ;
    SHAPE ABUTMENT ;
    PORT
      LAYER metal3 ;
      RECT 894.425 0.000 894.495 0.070 ;
    END
  END w0_wd_in[91]
  PIN w0_wd_in[92]
    DIRECTION INPUT ;
    USE SIGNAL ;
    SHAPE ABUTMENT ;
    PORT
      LAYER metal3 ;
      RECT 894.565 0.000 894.635 0.070 ;
    END
  END w0_wd_in[92]
  PIN w0_wd_in[93]
    DIRECTION INPUT ;
    USE SIGNAL ;
    SHAPE ABUTMENT ;
    PORT
      LAYER metal3 ;
      RECT 894.705 0.000 894.775 0.070 ;
    END
  END w0_wd_in[93]
  PIN w0_wd_in[94]
    DIRECTION INPUT ;
    USE SIGNAL ;
    SHAPE ABUTMENT ;
    PORT
      LAYER metal3 ;
      RECT 894.845 0.000 894.915 0.070 ;
    END
  END w0_wd_in[94]
  PIN w0_wd_in[95]
    DIRECTION INPUT ;
    USE SIGNAL ;
    SHAPE ABUTMENT ;
    PORT
      LAYER metal3 ;
      RECT 894.985 0.000 895.055 0.070 ;
    END
  END w0_wd_in[95]
  PIN w0_wd_in[96]
    DIRECTION INPUT ;
    USE SIGNAL ;
    SHAPE ABUTMENT ;
    PORT
      LAYER metal3 ;
      RECT 895.125 0.000 895.195 0.070 ;
    END
  END w0_wd_in[96]
  PIN w0_wd_in[97]
    DIRECTION INPUT ;
    USE SIGNAL ;
    SHAPE ABUTMENT ;
    PORT
      LAYER metal3 ;
      RECT 895.265 0.000 895.335 0.070 ;
    END
  END w0_wd_in[97]
  PIN w0_wd_in[98]
    DIRECTION INPUT ;
    USE SIGNAL ;
    SHAPE ABUTMENT ;
    PORT
      LAYER metal3 ;
      RECT 895.405 0.000 895.475 0.070 ;
    END
  END w0_wd_in[98]
  PIN w0_wd_in[99]
    DIRECTION INPUT ;
    USE SIGNAL ;
    SHAPE ABUTMENT ;
    PORT
      LAYER metal3 ;
      RECT 895.545 0.000 895.615 0.070 ;
    END
  END w0_wd_in[99]
  PIN w0_wd_in[100]
    DIRECTION INPUT ;
    USE SIGNAL ;
    SHAPE ABUTMENT ;
    PORT
      LAYER metal3 ;
      RECT 895.685 0.000 895.755 0.070 ;
    END
  END w0_wd_in[100]
  PIN w0_wd_in[101]
    DIRECTION INPUT ;
    USE SIGNAL ;
    SHAPE ABUTMENT ;
    PORT
      LAYER metal3 ;
      RECT 895.825 0.000 895.895 0.070 ;
    END
  END w0_wd_in[101]
  PIN w0_wd_in[102]
    DIRECTION INPUT ;
    USE SIGNAL ;
    SHAPE ABUTMENT ;
    PORT
      LAYER metal3 ;
      RECT 895.965 0.000 896.035 0.070 ;
    END
  END w0_wd_in[102]
  PIN w0_wd_in[103]
    DIRECTION INPUT ;
    USE SIGNAL ;
    SHAPE ABUTMENT ;
    PORT
      LAYER metal3 ;
      RECT 896.105 0.000 896.175 0.070 ;
    END
  END w0_wd_in[103]
  PIN w0_wd_in[104]
    DIRECTION INPUT ;
    USE SIGNAL ;
    SHAPE ABUTMENT ;
    PORT
      LAYER metal3 ;
      RECT 896.245 0.000 896.315 0.070 ;
    END
  END w0_wd_in[104]
  PIN w0_wd_in[105]
    DIRECTION INPUT ;
    USE SIGNAL ;
    SHAPE ABUTMENT ;
    PORT
      LAYER metal3 ;
      RECT 896.385 0.000 896.455 0.070 ;
    END
  END w0_wd_in[105]
  PIN w0_wd_in[106]
    DIRECTION INPUT ;
    USE SIGNAL ;
    SHAPE ABUTMENT ;
    PORT
      LAYER metal3 ;
      RECT 896.525 0.000 896.595 0.070 ;
    END
  END w0_wd_in[106]
  PIN w0_wd_in[107]
    DIRECTION INPUT ;
    USE SIGNAL ;
    SHAPE ABUTMENT ;
    PORT
      LAYER metal3 ;
      RECT 896.665 0.000 896.735 0.070 ;
    END
  END w0_wd_in[107]
  PIN w0_wd_in[108]
    DIRECTION INPUT ;
    USE SIGNAL ;
    SHAPE ABUTMENT ;
    PORT
      LAYER metal3 ;
      RECT 896.805 0.000 896.875 0.070 ;
    END
  END w0_wd_in[108]
  PIN w0_wd_in[109]
    DIRECTION INPUT ;
    USE SIGNAL ;
    SHAPE ABUTMENT ;
    PORT
      LAYER metal3 ;
      RECT 896.945 0.000 897.015 0.070 ;
    END
  END w0_wd_in[109]
  PIN w0_wd_in[110]
    DIRECTION INPUT ;
    USE SIGNAL ;
    SHAPE ABUTMENT ;
    PORT
      LAYER metal3 ;
      RECT 897.085 0.000 897.155 0.070 ;
    END
  END w0_wd_in[110]
  PIN w0_wd_in[111]
    DIRECTION INPUT ;
    USE SIGNAL ;
    SHAPE ABUTMENT ;
    PORT
      LAYER metal3 ;
      RECT 897.225 0.000 897.295 0.070 ;
    END
  END w0_wd_in[111]
  PIN w0_wd_in[112]
    DIRECTION INPUT ;
    USE SIGNAL ;
    SHAPE ABUTMENT ;
    PORT
      LAYER metal3 ;
      RECT 897.365 0.000 897.435 0.070 ;
    END
  END w0_wd_in[112]
  PIN w0_wd_in[113]
    DIRECTION INPUT ;
    USE SIGNAL ;
    SHAPE ABUTMENT ;
    PORT
      LAYER metal3 ;
      RECT 897.505 0.000 897.575 0.070 ;
    END
  END w0_wd_in[113]
  PIN w0_wd_in[114]
    DIRECTION INPUT ;
    USE SIGNAL ;
    SHAPE ABUTMENT ;
    PORT
      LAYER metal3 ;
      RECT 897.645 0.000 897.715 0.070 ;
    END
  END w0_wd_in[114]
  PIN w0_wd_in[115]
    DIRECTION INPUT ;
    USE SIGNAL ;
    SHAPE ABUTMENT ;
    PORT
      LAYER metal3 ;
      RECT 897.785 0.000 897.855 0.070 ;
    END
  END w0_wd_in[115]
  PIN w0_wd_in[116]
    DIRECTION INPUT ;
    USE SIGNAL ;
    SHAPE ABUTMENT ;
    PORT
      LAYER metal3 ;
      RECT 897.925 0.000 897.995 0.070 ;
    END
  END w0_wd_in[116]
  PIN w0_wd_in[117]
    DIRECTION INPUT ;
    USE SIGNAL ;
    SHAPE ABUTMENT ;
    PORT
      LAYER metal3 ;
      RECT 898.065 0.000 898.135 0.070 ;
    END
  END w0_wd_in[117]
  PIN w0_wd_in[118]
    DIRECTION INPUT ;
    USE SIGNAL ;
    SHAPE ABUTMENT ;
    PORT
      LAYER metal3 ;
      RECT 898.205 0.000 898.275 0.070 ;
    END
  END w0_wd_in[118]
  PIN w0_wd_in[119]
    DIRECTION INPUT ;
    USE SIGNAL ;
    SHAPE ABUTMENT ;
    PORT
      LAYER metal3 ;
      RECT 898.345 0.000 898.415 0.070 ;
    END
  END w0_wd_in[119]
  PIN w0_wd_in[120]
    DIRECTION INPUT ;
    USE SIGNAL ;
    SHAPE ABUTMENT ;
    PORT
      LAYER metal3 ;
      RECT 898.485 0.000 898.555 0.070 ;
    END
  END w0_wd_in[120]
  PIN w0_wd_in[121]
    DIRECTION INPUT ;
    USE SIGNAL ;
    SHAPE ABUTMENT ;
    PORT
      LAYER metal3 ;
      RECT 898.625 0.000 898.695 0.070 ;
    END
  END w0_wd_in[121]
  PIN w0_wd_in[122]
    DIRECTION INPUT ;
    USE SIGNAL ;
    SHAPE ABUTMENT ;
    PORT
      LAYER metal3 ;
      RECT 898.765 0.000 898.835 0.070 ;
    END
  END w0_wd_in[122]
  PIN w0_wd_in[123]
    DIRECTION INPUT ;
    USE SIGNAL ;
    SHAPE ABUTMENT ;
    PORT
      LAYER metal3 ;
      RECT 898.905 0.000 898.975 0.070 ;
    END
  END w0_wd_in[123]
  PIN w0_wd_in[124]
    DIRECTION INPUT ;
    USE SIGNAL ;
    SHAPE ABUTMENT ;
    PORT
      LAYER metal3 ;
      RECT 899.045 0.000 899.115 0.070 ;
    END
  END w0_wd_in[124]
  PIN w0_wd_in[125]
    DIRECTION INPUT ;
    USE SIGNAL ;
    SHAPE ABUTMENT ;
    PORT
      LAYER metal3 ;
      RECT 899.185 0.000 899.255 0.070 ;
    END
  END w0_wd_in[125]
  PIN w0_wd_in[126]
    DIRECTION INPUT ;
    USE SIGNAL ;
    SHAPE ABUTMENT ;
    PORT
      LAYER metal3 ;
      RECT 899.325 0.000 899.395 0.070 ;
    END
  END w0_wd_in[126]
  PIN w0_wd_in[127]
    DIRECTION INPUT ;
    USE SIGNAL ;
    SHAPE ABUTMENT ;
    PORT
      LAYER metal3 ;
      RECT 899.465 0.000 899.535 0.070 ;
    END
  END w0_wd_in[127]
  PIN w0_wd_in[128]
    DIRECTION INPUT ;
    USE SIGNAL ;
    SHAPE ABUTMENT ;
    PORT
      LAYER metal3 ;
      RECT 899.605 0.000 899.675 0.070 ;
    END
  END w0_wd_in[128]
  PIN w0_wd_in[129]
    DIRECTION INPUT ;
    USE SIGNAL ;
    SHAPE ABUTMENT ;
    PORT
      LAYER metal3 ;
      RECT 899.745 0.000 899.815 0.070 ;
    END
  END w0_wd_in[129]
  PIN w0_wd_in[130]
    DIRECTION INPUT ;
    USE SIGNAL ;
    SHAPE ABUTMENT ;
    PORT
      LAYER metal3 ;
      RECT 899.885 0.000 899.955 0.070 ;
    END
  END w0_wd_in[130]
  PIN w0_wd_in[131]
    DIRECTION INPUT ;
    USE SIGNAL ;
    SHAPE ABUTMENT ;
    PORT
      LAYER metal3 ;
      RECT 900.025 0.000 900.095 0.070 ;
    END
  END w0_wd_in[131]
  PIN w0_wd_in[132]
    DIRECTION INPUT ;
    USE SIGNAL ;
    SHAPE ABUTMENT ;
    PORT
      LAYER metal3 ;
      RECT 900.165 0.000 900.235 0.070 ;
    END
  END w0_wd_in[132]
  PIN w0_wd_in[133]
    DIRECTION INPUT ;
    USE SIGNAL ;
    SHAPE ABUTMENT ;
    PORT
      LAYER metal3 ;
      RECT 900.305 0.000 900.375 0.070 ;
    END
  END w0_wd_in[133]
  PIN w0_wd_in[134]
    DIRECTION INPUT ;
    USE SIGNAL ;
    SHAPE ABUTMENT ;
    PORT
      LAYER metal3 ;
      RECT 900.445 0.000 900.515 0.070 ;
    END
  END w0_wd_in[134]
  PIN w0_wd_in[135]
    DIRECTION INPUT ;
    USE SIGNAL ;
    SHAPE ABUTMENT ;
    PORT
      LAYER metal3 ;
      RECT 900.585 0.000 900.655 0.070 ;
    END
  END w0_wd_in[135]
  PIN w0_wd_in[136]
    DIRECTION INPUT ;
    USE SIGNAL ;
    SHAPE ABUTMENT ;
    PORT
      LAYER metal3 ;
      RECT 900.725 0.000 900.795 0.070 ;
    END
  END w0_wd_in[136]
  PIN w0_wd_in[137]
    DIRECTION INPUT ;
    USE SIGNAL ;
    SHAPE ABUTMENT ;
    PORT
      LAYER metal3 ;
      RECT 900.865 0.000 900.935 0.070 ;
    END
  END w0_wd_in[137]
  PIN w0_wd_in[138]
    DIRECTION INPUT ;
    USE SIGNAL ;
    SHAPE ABUTMENT ;
    PORT
      LAYER metal3 ;
      RECT 901.005 0.000 901.075 0.070 ;
    END
  END w0_wd_in[138]
  PIN w0_wd_in[139]
    DIRECTION INPUT ;
    USE SIGNAL ;
    SHAPE ABUTMENT ;
    PORT
      LAYER metal3 ;
      RECT 901.145 0.000 901.215 0.070 ;
    END
  END w0_wd_in[139]
  PIN w0_wd_in[140]
    DIRECTION INPUT ;
    USE SIGNAL ;
    SHAPE ABUTMENT ;
    PORT
      LAYER metal3 ;
      RECT 901.285 0.000 901.355 0.070 ;
    END
  END w0_wd_in[140]
  PIN w0_wd_in[141]
    DIRECTION INPUT ;
    USE SIGNAL ;
    SHAPE ABUTMENT ;
    PORT
      LAYER metal3 ;
      RECT 901.425 0.000 901.495 0.070 ;
    END
  END w0_wd_in[141]
  PIN w0_wd_in[142]
    DIRECTION INPUT ;
    USE SIGNAL ;
    SHAPE ABUTMENT ;
    PORT
      LAYER metal3 ;
      RECT 901.565 0.000 901.635 0.070 ;
    END
  END w0_wd_in[142]
  PIN w0_wd_in[143]
    DIRECTION INPUT ;
    USE SIGNAL ;
    SHAPE ABUTMENT ;
    PORT
      LAYER metal3 ;
      RECT 901.705 0.000 901.775 0.070 ;
    END
  END w0_wd_in[143]
  PIN w0_wd_in[144]
    DIRECTION INPUT ;
    USE SIGNAL ;
    SHAPE ABUTMENT ;
    PORT
      LAYER metal3 ;
      RECT 901.845 0.000 901.915 0.070 ;
    END
  END w0_wd_in[144]
  PIN w0_wd_in[145]
    DIRECTION INPUT ;
    USE SIGNAL ;
    SHAPE ABUTMENT ;
    PORT
      LAYER metal3 ;
      RECT 901.985 0.000 902.055 0.070 ;
    END
  END w0_wd_in[145]
  PIN w0_wd_in[146]
    DIRECTION INPUT ;
    USE SIGNAL ;
    SHAPE ABUTMENT ;
    PORT
      LAYER metal3 ;
      RECT 902.125 0.000 902.195 0.070 ;
    END
  END w0_wd_in[146]
  PIN w0_wd_in[147]
    DIRECTION INPUT ;
    USE SIGNAL ;
    SHAPE ABUTMENT ;
    PORT
      LAYER metal3 ;
      RECT 902.265 0.000 902.335 0.070 ;
    END
  END w0_wd_in[147]
  PIN w0_wd_in[148]
    DIRECTION INPUT ;
    USE SIGNAL ;
    SHAPE ABUTMENT ;
    PORT
      LAYER metal3 ;
      RECT 902.405 0.000 902.475 0.070 ;
    END
  END w0_wd_in[148]
  PIN w0_wd_in[149]
    DIRECTION INPUT ;
    USE SIGNAL ;
    SHAPE ABUTMENT ;
    PORT
      LAYER metal3 ;
      RECT 902.545 0.000 902.615 0.070 ;
    END
  END w0_wd_in[149]
  PIN w0_wd_in[150]
    DIRECTION INPUT ;
    USE SIGNAL ;
    SHAPE ABUTMENT ;
    PORT
      LAYER metal3 ;
      RECT 902.685 0.000 902.755 0.070 ;
    END
  END w0_wd_in[150]
  PIN w0_wd_in[151]
    DIRECTION INPUT ;
    USE SIGNAL ;
    SHAPE ABUTMENT ;
    PORT
      LAYER metal3 ;
      RECT 902.825 0.000 902.895 0.070 ;
    END
  END w0_wd_in[151]
  PIN w0_wd_in[152]
    DIRECTION INPUT ;
    USE SIGNAL ;
    SHAPE ABUTMENT ;
    PORT
      LAYER metal3 ;
      RECT 902.965 0.000 903.035 0.070 ;
    END
  END w0_wd_in[152]
  PIN w0_wd_in[153]
    DIRECTION INPUT ;
    USE SIGNAL ;
    SHAPE ABUTMENT ;
    PORT
      LAYER metal3 ;
      RECT 903.105 0.000 903.175 0.070 ;
    END
  END w0_wd_in[153]
  PIN w0_wd_in[154]
    DIRECTION INPUT ;
    USE SIGNAL ;
    SHAPE ABUTMENT ;
    PORT
      LAYER metal3 ;
      RECT 903.245 0.000 903.315 0.070 ;
    END
  END w0_wd_in[154]
  PIN w0_wd_in[155]
    DIRECTION INPUT ;
    USE SIGNAL ;
    SHAPE ABUTMENT ;
    PORT
      LAYER metal3 ;
      RECT 903.385 0.000 903.455 0.070 ;
    END
  END w0_wd_in[155]
  PIN w0_wd_in[156]
    DIRECTION INPUT ;
    USE SIGNAL ;
    SHAPE ABUTMENT ;
    PORT
      LAYER metal3 ;
      RECT 903.525 0.000 903.595 0.070 ;
    END
  END w0_wd_in[156]
  PIN w0_wd_in[157]
    DIRECTION INPUT ;
    USE SIGNAL ;
    SHAPE ABUTMENT ;
    PORT
      LAYER metal3 ;
      RECT 903.665 0.000 903.735 0.070 ;
    END
  END w0_wd_in[157]
  PIN w0_wd_in[158]
    DIRECTION INPUT ;
    USE SIGNAL ;
    SHAPE ABUTMENT ;
    PORT
      LAYER metal3 ;
      RECT 903.805 0.000 903.875 0.070 ;
    END
  END w0_wd_in[158]
  PIN w0_wd_in[159]
    DIRECTION INPUT ;
    USE SIGNAL ;
    SHAPE ABUTMENT ;
    PORT
      LAYER metal3 ;
      RECT 903.945 0.000 904.015 0.070 ;
    END
  END w0_wd_in[159]
  PIN w0_wd_in[160]
    DIRECTION INPUT ;
    USE SIGNAL ;
    SHAPE ABUTMENT ;
    PORT
      LAYER metal3 ;
      RECT 904.085 0.000 904.155 0.070 ;
    END
  END w0_wd_in[160]
  PIN w0_wd_in[161]
    DIRECTION INPUT ;
    USE SIGNAL ;
    SHAPE ABUTMENT ;
    PORT
      LAYER metal3 ;
      RECT 904.225 0.000 904.295 0.070 ;
    END
  END w0_wd_in[161]
  PIN w0_wd_in[162]
    DIRECTION INPUT ;
    USE SIGNAL ;
    SHAPE ABUTMENT ;
    PORT
      LAYER metal3 ;
      RECT 904.365 0.000 904.435 0.070 ;
    END
  END w0_wd_in[162]
  PIN w0_wd_in[163]
    DIRECTION INPUT ;
    USE SIGNAL ;
    SHAPE ABUTMENT ;
    PORT
      LAYER metal3 ;
      RECT 904.505 0.000 904.575 0.070 ;
    END
  END w0_wd_in[163]
  PIN w0_wd_in[164]
    DIRECTION INPUT ;
    USE SIGNAL ;
    SHAPE ABUTMENT ;
    PORT
      LAYER metal3 ;
      RECT 904.645 0.000 904.715 0.070 ;
    END
  END w0_wd_in[164]
  PIN w0_wd_in[165]
    DIRECTION INPUT ;
    USE SIGNAL ;
    SHAPE ABUTMENT ;
    PORT
      LAYER metal3 ;
      RECT 904.785 0.000 904.855 0.070 ;
    END
  END w0_wd_in[165]
  PIN w0_wd_in[166]
    DIRECTION INPUT ;
    USE SIGNAL ;
    SHAPE ABUTMENT ;
    PORT
      LAYER metal3 ;
      RECT 904.925 0.000 904.995 0.070 ;
    END
  END w0_wd_in[166]
  PIN w0_wd_in[167]
    DIRECTION INPUT ;
    USE SIGNAL ;
    SHAPE ABUTMENT ;
    PORT
      LAYER metal3 ;
      RECT 905.065 0.000 905.135 0.070 ;
    END
  END w0_wd_in[167]
  PIN w0_wd_in[168]
    DIRECTION INPUT ;
    USE SIGNAL ;
    SHAPE ABUTMENT ;
    PORT
      LAYER metal3 ;
      RECT 905.205 0.000 905.275 0.070 ;
    END
  END w0_wd_in[168]
  PIN w0_wd_in[169]
    DIRECTION INPUT ;
    USE SIGNAL ;
    SHAPE ABUTMENT ;
    PORT
      LAYER metal3 ;
      RECT 905.345 0.000 905.415 0.070 ;
    END
  END w0_wd_in[169]
  PIN w0_wd_in[170]
    DIRECTION INPUT ;
    USE SIGNAL ;
    SHAPE ABUTMENT ;
    PORT
      LAYER metal3 ;
      RECT 905.485 0.000 905.555 0.070 ;
    END
  END w0_wd_in[170]
  PIN w0_wd_in[171]
    DIRECTION INPUT ;
    USE SIGNAL ;
    SHAPE ABUTMENT ;
    PORT
      LAYER metal3 ;
      RECT 905.625 0.000 905.695 0.070 ;
    END
  END w0_wd_in[171]
  PIN w0_wd_in[172]
    DIRECTION INPUT ;
    USE SIGNAL ;
    SHAPE ABUTMENT ;
    PORT
      LAYER metal3 ;
      RECT 905.765 0.000 905.835 0.070 ;
    END
  END w0_wd_in[172]
  PIN w0_wd_in[173]
    DIRECTION INPUT ;
    USE SIGNAL ;
    SHAPE ABUTMENT ;
    PORT
      LAYER metal3 ;
      RECT 905.905 0.000 905.975 0.070 ;
    END
  END w0_wd_in[173]
  PIN w0_wd_in[174]
    DIRECTION INPUT ;
    USE SIGNAL ;
    SHAPE ABUTMENT ;
    PORT
      LAYER metal3 ;
      RECT 906.045 0.000 906.115 0.070 ;
    END
  END w0_wd_in[174]
  PIN w0_wd_in[175]
    DIRECTION INPUT ;
    USE SIGNAL ;
    SHAPE ABUTMENT ;
    PORT
      LAYER metal3 ;
      RECT 906.185 0.000 906.255 0.070 ;
    END
  END w0_wd_in[175]
  PIN w0_wd_in[176]
    DIRECTION INPUT ;
    USE SIGNAL ;
    SHAPE ABUTMENT ;
    PORT
      LAYER metal3 ;
      RECT 906.325 0.000 906.395 0.070 ;
    END
  END w0_wd_in[176]
  PIN w0_wd_in[177]
    DIRECTION INPUT ;
    USE SIGNAL ;
    SHAPE ABUTMENT ;
    PORT
      LAYER metal3 ;
      RECT 906.465 0.000 906.535 0.070 ;
    END
  END w0_wd_in[177]
  PIN w0_wd_in[178]
    DIRECTION INPUT ;
    USE SIGNAL ;
    SHAPE ABUTMENT ;
    PORT
      LAYER metal3 ;
      RECT 906.605 0.000 906.675 0.070 ;
    END
  END w0_wd_in[178]
  PIN w0_wd_in[179]
    DIRECTION INPUT ;
    USE SIGNAL ;
    SHAPE ABUTMENT ;
    PORT
      LAYER metal3 ;
      RECT 906.745 0.000 906.815 0.070 ;
    END
  END w0_wd_in[179]
  PIN w0_wd_in[180]
    DIRECTION INPUT ;
    USE SIGNAL ;
    SHAPE ABUTMENT ;
    PORT
      LAYER metal3 ;
      RECT 906.885 0.000 906.955 0.070 ;
    END
  END w0_wd_in[180]
  PIN w0_wd_in[181]
    DIRECTION INPUT ;
    USE SIGNAL ;
    SHAPE ABUTMENT ;
    PORT
      LAYER metal3 ;
      RECT 907.025 0.000 907.095 0.070 ;
    END
  END w0_wd_in[181]
  PIN w0_wd_in[182]
    DIRECTION INPUT ;
    USE SIGNAL ;
    SHAPE ABUTMENT ;
    PORT
      LAYER metal3 ;
      RECT 907.165 0.000 907.235 0.070 ;
    END
  END w0_wd_in[182]
  PIN w0_wd_in[183]
    DIRECTION INPUT ;
    USE SIGNAL ;
    SHAPE ABUTMENT ;
    PORT
      LAYER metal3 ;
      RECT 907.305 0.000 907.375 0.070 ;
    END
  END w0_wd_in[183]
  PIN w0_wd_in[184]
    DIRECTION INPUT ;
    USE SIGNAL ;
    SHAPE ABUTMENT ;
    PORT
      LAYER metal3 ;
      RECT 907.445 0.000 907.515 0.070 ;
    END
  END w0_wd_in[184]
  PIN w0_wd_in[185]
    DIRECTION INPUT ;
    USE SIGNAL ;
    SHAPE ABUTMENT ;
    PORT
      LAYER metal3 ;
      RECT 907.585 0.000 907.655 0.070 ;
    END
  END w0_wd_in[185]
  PIN w0_wd_in[186]
    DIRECTION INPUT ;
    USE SIGNAL ;
    SHAPE ABUTMENT ;
    PORT
      LAYER metal3 ;
      RECT 907.725 0.000 907.795 0.070 ;
    END
  END w0_wd_in[186]
  PIN w0_wd_in[187]
    DIRECTION INPUT ;
    USE SIGNAL ;
    SHAPE ABUTMENT ;
    PORT
      LAYER metal3 ;
      RECT 907.865 0.000 907.935 0.070 ;
    END
  END w0_wd_in[187]
  PIN w0_wd_in[188]
    DIRECTION INPUT ;
    USE SIGNAL ;
    SHAPE ABUTMENT ;
    PORT
      LAYER metal3 ;
      RECT 908.005 0.000 908.075 0.070 ;
    END
  END w0_wd_in[188]
  PIN w0_wd_in[189]
    DIRECTION INPUT ;
    USE SIGNAL ;
    SHAPE ABUTMENT ;
    PORT
      LAYER metal3 ;
      RECT 908.145 0.000 908.215 0.070 ;
    END
  END w0_wd_in[189]
  PIN w0_wd_in[190]
    DIRECTION INPUT ;
    USE SIGNAL ;
    SHAPE ABUTMENT ;
    PORT
      LAYER metal3 ;
      RECT 908.285 0.000 908.355 0.070 ;
    END
  END w0_wd_in[190]
  PIN w0_wd_in[191]
    DIRECTION INPUT ;
    USE SIGNAL ;
    SHAPE ABUTMENT ;
    PORT
      LAYER metal3 ;
      RECT 908.425 0.000 908.495 0.070 ;
    END
  END w0_wd_in[191]
  PIN w0_wd_in[192]
    DIRECTION INPUT ;
    USE SIGNAL ;
    SHAPE ABUTMENT ;
    PORT
      LAYER metal3 ;
      RECT 908.565 0.000 908.635 0.070 ;
    END
  END w0_wd_in[192]
  PIN w0_wd_in[193]
    DIRECTION INPUT ;
    USE SIGNAL ;
    SHAPE ABUTMENT ;
    PORT
      LAYER metal3 ;
      RECT 908.705 0.000 908.775 0.070 ;
    END
  END w0_wd_in[193]
  PIN w0_wd_in[194]
    DIRECTION INPUT ;
    USE SIGNAL ;
    SHAPE ABUTMENT ;
    PORT
      LAYER metal3 ;
      RECT 908.845 0.000 908.915 0.070 ;
    END
  END w0_wd_in[194]
  PIN w0_wd_in[195]
    DIRECTION INPUT ;
    USE SIGNAL ;
    SHAPE ABUTMENT ;
    PORT
      LAYER metal3 ;
      RECT 908.985 0.000 909.055 0.070 ;
    END
  END w0_wd_in[195]
  PIN w0_wd_in[196]
    DIRECTION INPUT ;
    USE SIGNAL ;
    SHAPE ABUTMENT ;
    PORT
      LAYER metal3 ;
      RECT 909.125 0.000 909.195 0.070 ;
    END
  END w0_wd_in[196]
  PIN w0_wd_in[197]
    DIRECTION INPUT ;
    USE SIGNAL ;
    SHAPE ABUTMENT ;
    PORT
      LAYER metal3 ;
      RECT 909.265 0.000 909.335 0.070 ;
    END
  END w0_wd_in[197]
  PIN w0_wd_in[198]
    DIRECTION INPUT ;
    USE SIGNAL ;
    SHAPE ABUTMENT ;
    PORT
      LAYER metal3 ;
      RECT 909.405 0.000 909.475 0.070 ;
    END
  END w0_wd_in[198]
  PIN w0_wd_in[199]
    DIRECTION INPUT ;
    USE SIGNAL ;
    SHAPE ABUTMENT ;
    PORT
      LAYER metal3 ;
      RECT 909.545 0.000 909.615 0.070 ;
    END
  END w0_wd_in[199]
  PIN w0_wd_in[200]
    DIRECTION INPUT ;
    USE SIGNAL ;
    SHAPE ABUTMENT ;
    PORT
      LAYER metal3 ;
      RECT 909.685 0.000 909.755 0.070 ;
    END
  END w0_wd_in[200]
  PIN w0_wd_in[201]
    DIRECTION INPUT ;
    USE SIGNAL ;
    SHAPE ABUTMENT ;
    PORT
      LAYER metal3 ;
      RECT 909.825 0.000 909.895 0.070 ;
    END
  END w0_wd_in[201]
  PIN w0_wd_in[202]
    DIRECTION INPUT ;
    USE SIGNAL ;
    SHAPE ABUTMENT ;
    PORT
      LAYER metal3 ;
      RECT 909.965 0.000 910.035 0.070 ;
    END
  END w0_wd_in[202]
  PIN w0_wd_in[203]
    DIRECTION INPUT ;
    USE SIGNAL ;
    SHAPE ABUTMENT ;
    PORT
      LAYER metal3 ;
      RECT 910.105 0.000 910.175 0.070 ;
    END
  END w0_wd_in[203]
  PIN w0_wd_in[204]
    DIRECTION INPUT ;
    USE SIGNAL ;
    SHAPE ABUTMENT ;
    PORT
      LAYER metal3 ;
      RECT 910.245 0.000 910.315 0.070 ;
    END
  END w0_wd_in[204]
  PIN w0_wd_in[205]
    DIRECTION INPUT ;
    USE SIGNAL ;
    SHAPE ABUTMENT ;
    PORT
      LAYER metal3 ;
      RECT 910.385 0.000 910.455 0.070 ;
    END
  END w0_wd_in[205]
  PIN w0_wd_in[206]
    DIRECTION INPUT ;
    USE SIGNAL ;
    SHAPE ABUTMENT ;
    PORT
      LAYER metal3 ;
      RECT 910.525 0.000 910.595 0.070 ;
    END
  END w0_wd_in[206]
  PIN w0_wd_in[207]
    DIRECTION INPUT ;
    USE SIGNAL ;
    SHAPE ABUTMENT ;
    PORT
      LAYER metal3 ;
      RECT 910.665 0.000 910.735 0.070 ;
    END
  END w0_wd_in[207]
  PIN w0_wd_in[208]
    DIRECTION INPUT ;
    USE SIGNAL ;
    SHAPE ABUTMENT ;
    PORT
      LAYER metal3 ;
      RECT 910.805 0.000 910.875 0.070 ;
    END
  END w0_wd_in[208]
  PIN w0_wd_in[209]
    DIRECTION INPUT ;
    USE SIGNAL ;
    SHAPE ABUTMENT ;
    PORT
      LAYER metal3 ;
      RECT 910.945 0.000 911.015 0.070 ;
    END
  END w0_wd_in[209]
  PIN w0_wd_in[210]
    DIRECTION INPUT ;
    USE SIGNAL ;
    SHAPE ABUTMENT ;
    PORT
      LAYER metal3 ;
      RECT 911.085 0.000 911.155 0.070 ;
    END
  END w0_wd_in[210]
  PIN w0_wd_in[211]
    DIRECTION INPUT ;
    USE SIGNAL ;
    SHAPE ABUTMENT ;
    PORT
      LAYER metal3 ;
      RECT 911.225 0.000 911.295 0.070 ;
    END
  END w0_wd_in[211]
  PIN w0_wd_in[212]
    DIRECTION INPUT ;
    USE SIGNAL ;
    SHAPE ABUTMENT ;
    PORT
      LAYER metal3 ;
      RECT 911.365 0.000 911.435 0.070 ;
    END
  END w0_wd_in[212]
  PIN w0_wd_in[213]
    DIRECTION INPUT ;
    USE SIGNAL ;
    SHAPE ABUTMENT ;
    PORT
      LAYER metal3 ;
      RECT 911.505 0.000 911.575 0.070 ;
    END
  END w0_wd_in[213]
  PIN w0_wd_in[214]
    DIRECTION INPUT ;
    USE SIGNAL ;
    SHAPE ABUTMENT ;
    PORT
      LAYER metal3 ;
      RECT 911.645 0.000 911.715 0.070 ;
    END
  END w0_wd_in[214]
  PIN w0_wd_in[215]
    DIRECTION INPUT ;
    USE SIGNAL ;
    SHAPE ABUTMENT ;
    PORT
      LAYER metal3 ;
      RECT 911.785 0.000 911.855 0.070 ;
    END
  END w0_wd_in[215]
  PIN w0_wd_in[216]
    DIRECTION INPUT ;
    USE SIGNAL ;
    SHAPE ABUTMENT ;
    PORT
      LAYER metal3 ;
      RECT 911.925 0.000 911.995 0.070 ;
    END
  END w0_wd_in[216]
  PIN w0_wd_in[217]
    DIRECTION INPUT ;
    USE SIGNAL ;
    SHAPE ABUTMENT ;
    PORT
      LAYER metal3 ;
      RECT 912.065 0.000 912.135 0.070 ;
    END
  END w0_wd_in[217]
  PIN w0_wd_in[218]
    DIRECTION INPUT ;
    USE SIGNAL ;
    SHAPE ABUTMENT ;
    PORT
      LAYER metal3 ;
      RECT 912.205 0.000 912.275 0.070 ;
    END
  END w0_wd_in[218]
  PIN w0_wd_in[219]
    DIRECTION INPUT ;
    USE SIGNAL ;
    SHAPE ABUTMENT ;
    PORT
      LAYER metal3 ;
      RECT 912.345 0.000 912.415 0.070 ;
    END
  END w0_wd_in[219]
  PIN w0_wd_in[220]
    DIRECTION INPUT ;
    USE SIGNAL ;
    SHAPE ABUTMENT ;
    PORT
      LAYER metal3 ;
      RECT 912.485 0.000 912.555 0.070 ;
    END
  END w0_wd_in[220]
  PIN w0_wd_in[221]
    DIRECTION INPUT ;
    USE SIGNAL ;
    SHAPE ABUTMENT ;
    PORT
      LAYER metal3 ;
      RECT 912.625 0.000 912.695 0.070 ;
    END
  END w0_wd_in[221]
  PIN w0_wd_in[222]
    DIRECTION INPUT ;
    USE SIGNAL ;
    SHAPE ABUTMENT ;
    PORT
      LAYER metal3 ;
      RECT 912.765 0.000 912.835 0.070 ;
    END
  END w0_wd_in[222]
  PIN w0_wd_in[223]
    DIRECTION INPUT ;
    USE SIGNAL ;
    SHAPE ABUTMENT ;
    PORT
      LAYER metal3 ;
      RECT 912.905 0.000 912.975 0.070 ;
    END
  END w0_wd_in[223]
  PIN w0_wd_in[224]
    DIRECTION INPUT ;
    USE SIGNAL ;
    SHAPE ABUTMENT ;
    PORT
      LAYER metal3 ;
      RECT 913.045 0.000 913.115 0.070 ;
    END
  END w0_wd_in[224]
  PIN w0_wd_in[225]
    DIRECTION INPUT ;
    USE SIGNAL ;
    SHAPE ABUTMENT ;
    PORT
      LAYER metal3 ;
      RECT 913.185 0.000 913.255 0.070 ;
    END
  END w0_wd_in[225]
  PIN w0_wd_in[226]
    DIRECTION INPUT ;
    USE SIGNAL ;
    SHAPE ABUTMENT ;
    PORT
      LAYER metal3 ;
      RECT 913.325 0.000 913.395 0.070 ;
    END
  END w0_wd_in[226]
  PIN w0_wd_in[227]
    DIRECTION INPUT ;
    USE SIGNAL ;
    SHAPE ABUTMENT ;
    PORT
      LAYER metal3 ;
      RECT 913.465 0.000 913.535 0.070 ;
    END
  END w0_wd_in[227]
  PIN w0_wd_in[228]
    DIRECTION INPUT ;
    USE SIGNAL ;
    SHAPE ABUTMENT ;
    PORT
      LAYER metal3 ;
      RECT 913.605 0.000 913.675 0.070 ;
    END
  END w0_wd_in[228]
  PIN w0_wd_in[229]
    DIRECTION INPUT ;
    USE SIGNAL ;
    SHAPE ABUTMENT ;
    PORT
      LAYER metal3 ;
      RECT 913.745 0.000 913.815 0.070 ;
    END
  END w0_wd_in[229]
  PIN w0_wd_in[230]
    DIRECTION INPUT ;
    USE SIGNAL ;
    SHAPE ABUTMENT ;
    PORT
      LAYER metal3 ;
      RECT 913.885 0.000 913.955 0.070 ;
    END
  END w0_wd_in[230]
  PIN w0_wd_in[231]
    DIRECTION INPUT ;
    USE SIGNAL ;
    SHAPE ABUTMENT ;
    PORT
      LAYER metal3 ;
      RECT 914.025 0.000 914.095 0.070 ;
    END
  END w0_wd_in[231]
  PIN w0_wd_in[232]
    DIRECTION INPUT ;
    USE SIGNAL ;
    SHAPE ABUTMENT ;
    PORT
      LAYER metal3 ;
      RECT 914.165 0.000 914.235 0.070 ;
    END
  END w0_wd_in[232]
  PIN w0_wd_in[233]
    DIRECTION INPUT ;
    USE SIGNAL ;
    SHAPE ABUTMENT ;
    PORT
      LAYER metal3 ;
      RECT 914.305 0.000 914.375 0.070 ;
    END
  END w0_wd_in[233]
  PIN w0_wd_in[234]
    DIRECTION INPUT ;
    USE SIGNAL ;
    SHAPE ABUTMENT ;
    PORT
      LAYER metal3 ;
      RECT 914.445 0.000 914.515 0.070 ;
    END
  END w0_wd_in[234]
  PIN w0_wd_in[235]
    DIRECTION INPUT ;
    USE SIGNAL ;
    SHAPE ABUTMENT ;
    PORT
      LAYER metal3 ;
      RECT 914.585 0.000 914.655 0.070 ;
    END
  END w0_wd_in[235]
  PIN w0_wd_in[236]
    DIRECTION INPUT ;
    USE SIGNAL ;
    SHAPE ABUTMENT ;
    PORT
      LAYER metal3 ;
      RECT 914.725 0.000 914.795 0.070 ;
    END
  END w0_wd_in[236]
  PIN w0_wd_in[237]
    DIRECTION INPUT ;
    USE SIGNAL ;
    SHAPE ABUTMENT ;
    PORT
      LAYER metal3 ;
      RECT 914.865 0.000 914.935 0.070 ;
    END
  END w0_wd_in[237]
  PIN w0_wd_in[238]
    DIRECTION INPUT ;
    USE SIGNAL ;
    SHAPE ABUTMENT ;
    PORT
      LAYER metal3 ;
      RECT 915.005 0.000 915.075 0.070 ;
    END
  END w0_wd_in[238]
  PIN w0_wd_in[239]
    DIRECTION INPUT ;
    USE SIGNAL ;
    SHAPE ABUTMENT ;
    PORT
      LAYER metal3 ;
      RECT 915.145 0.000 915.215 0.070 ;
    END
  END w0_wd_in[239]
  PIN w0_wd_in[240]
    DIRECTION INPUT ;
    USE SIGNAL ;
    SHAPE ABUTMENT ;
    PORT
      LAYER metal3 ;
      RECT 915.285 0.000 915.355 0.070 ;
    END
  END w0_wd_in[240]
  PIN w0_wd_in[241]
    DIRECTION INPUT ;
    USE SIGNAL ;
    SHAPE ABUTMENT ;
    PORT
      LAYER metal3 ;
      RECT 915.425 0.000 915.495 0.070 ;
    END
  END w0_wd_in[241]
  PIN w0_wd_in[242]
    DIRECTION INPUT ;
    USE SIGNAL ;
    SHAPE ABUTMENT ;
    PORT
      LAYER metal3 ;
      RECT 915.565 0.000 915.635 0.070 ;
    END
  END w0_wd_in[242]
  PIN w0_wd_in[243]
    DIRECTION INPUT ;
    USE SIGNAL ;
    SHAPE ABUTMENT ;
    PORT
      LAYER metal3 ;
      RECT 915.705 0.000 915.775 0.070 ;
    END
  END w0_wd_in[243]
  PIN w0_wd_in[244]
    DIRECTION INPUT ;
    USE SIGNAL ;
    SHAPE ABUTMENT ;
    PORT
      LAYER metal3 ;
      RECT 915.845 0.000 915.915 0.070 ;
    END
  END w0_wd_in[244]
  PIN w0_wd_in[245]
    DIRECTION INPUT ;
    USE SIGNAL ;
    SHAPE ABUTMENT ;
    PORT
      LAYER metal3 ;
      RECT 915.985 0.000 916.055 0.070 ;
    END
  END w0_wd_in[245]
  PIN w0_wd_in[246]
    DIRECTION INPUT ;
    USE SIGNAL ;
    SHAPE ABUTMENT ;
    PORT
      LAYER metal3 ;
      RECT 916.125 0.000 916.195 0.070 ;
    END
  END w0_wd_in[246]
  PIN w0_wd_in[247]
    DIRECTION INPUT ;
    USE SIGNAL ;
    SHAPE ABUTMENT ;
    PORT
      LAYER metal3 ;
      RECT 916.265 0.000 916.335 0.070 ;
    END
  END w0_wd_in[247]
  PIN w0_wd_in[248]
    DIRECTION INPUT ;
    USE SIGNAL ;
    SHAPE ABUTMENT ;
    PORT
      LAYER metal3 ;
      RECT 916.405 0.000 916.475 0.070 ;
    END
  END w0_wd_in[248]
  PIN w0_wd_in[249]
    DIRECTION INPUT ;
    USE SIGNAL ;
    SHAPE ABUTMENT ;
    PORT
      LAYER metal3 ;
      RECT 916.545 0.000 916.615 0.070 ;
    END
  END w0_wd_in[249]
  PIN w0_wd_in[250]
    DIRECTION INPUT ;
    USE SIGNAL ;
    SHAPE ABUTMENT ;
    PORT
      LAYER metal3 ;
      RECT 916.685 0.000 916.755 0.070 ;
    END
  END w0_wd_in[250]
  PIN w0_wd_in[251]
    DIRECTION INPUT ;
    USE SIGNAL ;
    SHAPE ABUTMENT ;
    PORT
      LAYER metal3 ;
      RECT 916.825 0.000 916.895 0.070 ;
    END
  END w0_wd_in[251]
  PIN w0_wd_in[252]
    DIRECTION INPUT ;
    USE SIGNAL ;
    SHAPE ABUTMENT ;
    PORT
      LAYER metal3 ;
      RECT 916.965 0.000 917.035 0.070 ;
    END
  END w0_wd_in[252]
  PIN w0_wd_in[253]
    DIRECTION INPUT ;
    USE SIGNAL ;
    SHAPE ABUTMENT ;
    PORT
      LAYER metal3 ;
      RECT 917.105 0.000 917.175 0.070 ;
    END
  END w0_wd_in[253]
  PIN w0_wd_in[254]
    DIRECTION INPUT ;
    USE SIGNAL ;
    SHAPE ABUTMENT ;
    PORT
      LAYER metal3 ;
      RECT 917.245 0.000 917.315 0.070 ;
    END
  END w0_wd_in[254]
  PIN w0_wd_in[255]
    DIRECTION INPUT ;
    USE SIGNAL ;
    SHAPE ABUTMENT ;
    PORT
      LAYER metal3 ;
      RECT 917.385 0.000 917.455 0.070 ;
    END
  END w0_wd_in[255]
  PIN w0_wd_in[256]
    DIRECTION INPUT ;
    USE SIGNAL ;
    SHAPE ABUTMENT ;
    PORT
      LAYER metal3 ;
      RECT 917.525 0.000 917.595 0.070 ;
    END
  END w0_wd_in[256]
  PIN w0_wd_in[257]
    DIRECTION INPUT ;
    USE SIGNAL ;
    SHAPE ABUTMENT ;
    PORT
      LAYER metal3 ;
      RECT 917.665 0.000 917.735 0.070 ;
    END
  END w0_wd_in[257]
  PIN w0_wd_in[258]
    DIRECTION INPUT ;
    USE SIGNAL ;
    SHAPE ABUTMENT ;
    PORT
      LAYER metal3 ;
      RECT 917.805 0.000 917.875 0.070 ;
    END
  END w0_wd_in[258]
  PIN w0_wd_in[259]
    DIRECTION INPUT ;
    USE SIGNAL ;
    SHAPE ABUTMENT ;
    PORT
      LAYER metal3 ;
      RECT 917.945 0.000 918.015 0.070 ;
    END
  END w0_wd_in[259]
  PIN w0_wd_in[260]
    DIRECTION INPUT ;
    USE SIGNAL ;
    SHAPE ABUTMENT ;
    PORT
      LAYER metal3 ;
      RECT 918.085 0.000 918.155 0.070 ;
    END
  END w0_wd_in[260]
  PIN w0_wd_in[261]
    DIRECTION INPUT ;
    USE SIGNAL ;
    SHAPE ABUTMENT ;
    PORT
      LAYER metal3 ;
      RECT 918.225 0.000 918.295 0.070 ;
    END
  END w0_wd_in[261]
  PIN w0_wd_in[262]
    DIRECTION INPUT ;
    USE SIGNAL ;
    SHAPE ABUTMENT ;
    PORT
      LAYER metal3 ;
      RECT 918.365 0.000 918.435 0.070 ;
    END
  END w0_wd_in[262]
  PIN w0_wd_in[263]
    DIRECTION INPUT ;
    USE SIGNAL ;
    SHAPE ABUTMENT ;
    PORT
      LAYER metal3 ;
      RECT 918.505 0.000 918.575 0.070 ;
    END
  END w0_wd_in[263]
  PIN w0_wd_in[264]
    DIRECTION INPUT ;
    USE SIGNAL ;
    SHAPE ABUTMENT ;
    PORT
      LAYER metal3 ;
      RECT 918.645 0.000 918.715 0.070 ;
    END
  END w0_wd_in[264]
  PIN w0_wd_in[265]
    DIRECTION INPUT ;
    USE SIGNAL ;
    SHAPE ABUTMENT ;
    PORT
      LAYER metal3 ;
      RECT 918.785 0.000 918.855 0.070 ;
    END
  END w0_wd_in[265]
  PIN w0_wd_in[266]
    DIRECTION INPUT ;
    USE SIGNAL ;
    SHAPE ABUTMENT ;
    PORT
      LAYER metal3 ;
      RECT 918.925 0.000 918.995 0.070 ;
    END
  END w0_wd_in[266]
  PIN w0_wd_in[267]
    DIRECTION INPUT ;
    USE SIGNAL ;
    SHAPE ABUTMENT ;
    PORT
      LAYER metal3 ;
      RECT 919.065 0.000 919.135 0.070 ;
    END
  END w0_wd_in[267]
  PIN w0_wd_in[268]
    DIRECTION INPUT ;
    USE SIGNAL ;
    SHAPE ABUTMENT ;
    PORT
      LAYER metal3 ;
      RECT 919.205 0.000 919.275 0.070 ;
    END
  END w0_wd_in[268]
  PIN w0_wd_in[269]
    DIRECTION INPUT ;
    USE SIGNAL ;
    SHAPE ABUTMENT ;
    PORT
      LAYER metal3 ;
      RECT 919.345 0.000 919.415 0.070 ;
    END
  END w0_wd_in[269]
  PIN w0_wd_in[270]
    DIRECTION INPUT ;
    USE SIGNAL ;
    SHAPE ABUTMENT ;
    PORT
      LAYER metal3 ;
      RECT 919.485 0.000 919.555 0.070 ;
    END
  END w0_wd_in[270]
  PIN w0_wd_in[271]
    DIRECTION INPUT ;
    USE SIGNAL ;
    SHAPE ABUTMENT ;
    PORT
      LAYER metal3 ;
      RECT 919.625 0.000 919.695 0.070 ;
    END
  END w0_wd_in[271]
  PIN w0_wd_in[272]
    DIRECTION INPUT ;
    USE SIGNAL ;
    SHAPE ABUTMENT ;
    PORT
      LAYER metal3 ;
      RECT 919.765 0.000 919.835 0.070 ;
    END
  END w0_wd_in[272]
  PIN w0_wd_in[273]
    DIRECTION INPUT ;
    USE SIGNAL ;
    SHAPE ABUTMENT ;
    PORT
      LAYER metal3 ;
      RECT 919.905 0.000 919.975 0.070 ;
    END
  END w0_wd_in[273]
  PIN w0_wd_in[274]
    DIRECTION INPUT ;
    USE SIGNAL ;
    SHAPE ABUTMENT ;
    PORT
      LAYER metal3 ;
      RECT 920.045 0.000 920.115 0.070 ;
    END
  END w0_wd_in[274]
  PIN w0_wd_in[275]
    DIRECTION INPUT ;
    USE SIGNAL ;
    SHAPE ABUTMENT ;
    PORT
      LAYER metal3 ;
      RECT 920.185 0.000 920.255 0.070 ;
    END
  END w0_wd_in[275]
  PIN w0_wd_in[276]
    DIRECTION INPUT ;
    USE SIGNAL ;
    SHAPE ABUTMENT ;
    PORT
      LAYER metal3 ;
      RECT 920.325 0.000 920.395 0.070 ;
    END
  END w0_wd_in[276]
  PIN w0_wd_in[277]
    DIRECTION INPUT ;
    USE SIGNAL ;
    SHAPE ABUTMENT ;
    PORT
      LAYER metal3 ;
      RECT 920.465 0.000 920.535 0.070 ;
    END
  END w0_wd_in[277]
  PIN w0_wd_in[278]
    DIRECTION INPUT ;
    USE SIGNAL ;
    SHAPE ABUTMENT ;
    PORT
      LAYER metal3 ;
      RECT 920.605 0.000 920.675 0.070 ;
    END
  END w0_wd_in[278]
  PIN w0_wd_in[279]
    DIRECTION INPUT ;
    USE SIGNAL ;
    SHAPE ABUTMENT ;
    PORT
      LAYER metal3 ;
      RECT 920.745 0.000 920.815 0.070 ;
    END
  END w0_wd_in[279]
  PIN w0_wd_in[280]
    DIRECTION INPUT ;
    USE SIGNAL ;
    SHAPE ABUTMENT ;
    PORT
      LAYER metal3 ;
      RECT 920.885 0.000 920.955 0.070 ;
    END
  END w0_wd_in[280]
  PIN w0_wd_in[281]
    DIRECTION INPUT ;
    USE SIGNAL ;
    SHAPE ABUTMENT ;
    PORT
      LAYER metal3 ;
      RECT 921.025 0.000 921.095 0.070 ;
    END
  END w0_wd_in[281]
  PIN w0_wd_in[282]
    DIRECTION INPUT ;
    USE SIGNAL ;
    SHAPE ABUTMENT ;
    PORT
      LAYER metal3 ;
      RECT 921.165 0.000 921.235 0.070 ;
    END
  END w0_wd_in[282]
  PIN w0_wd_in[283]
    DIRECTION INPUT ;
    USE SIGNAL ;
    SHAPE ABUTMENT ;
    PORT
      LAYER metal3 ;
      RECT 921.305 0.000 921.375 0.070 ;
    END
  END w0_wd_in[283]
  PIN w0_wd_in[284]
    DIRECTION INPUT ;
    USE SIGNAL ;
    SHAPE ABUTMENT ;
    PORT
      LAYER metal3 ;
      RECT 921.445 0.000 921.515 0.070 ;
    END
  END w0_wd_in[284]
  PIN w0_wd_in[285]
    DIRECTION INPUT ;
    USE SIGNAL ;
    SHAPE ABUTMENT ;
    PORT
      LAYER metal3 ;
      RECT 921.585 0.000 921.655 0.070 ;
    END
  END w0_wd_in[285]
  PIN w0_wd_in[286]
    DIRECTION INPUT ;
    USE SIGNAL ;
    SHAPE ABUTMENT ;
    PORT
      LAYER metal3 ;
      RECT 921.725 0.000 921.795 0.070 ;
    END
  END w0_wd_in[286]
  PIN w0_wd_in[287]
    DIRECTION INPUT ;
    USE SIGNAL ;
    SHAPE ABUTMENT ;
    PORT
      LAYER metal3 ;
      RECT 921.865 0.000 921.935 0.070 ;
    END
  END w0_wd_in[287]
  PIN w0_wd_in[288]
    DIRECTION INPUT ;
    USE SIGNAL ;
    SHAPE ABUTMENT ;
    PORT
      LAYER metal3 ;
      RECT 922.005 0.000 922.075 0.070 ;
    END
  END w0_wd_in[288]
  PIN w0_wd_in[289]
    DIRECTION INPUT ;
    USE SIGNAL ;
    SHAPE ABUTMENT ;
    PORT
      LAYER metal3 ;
      RECT 922.145 0.000 922.215 0.070 ;
    END
  END w0_wd_in[289]
  PIN w0_wd_in[290]
    DIRECTION INPUT ;
    USE SIGNAL ;
    SHAPE ABUTMENT ;
    PORT
      LAYER metal3 ;
      RECT 922.285 0.000 922.355 0.070 ;
    END
  END w0_wd_in[290]
  PIN w0_wd_in[291]
    DIRECTION INPUT ;
    USE SIGNAL ;
    SHAPE ABUTMENT ;
    PORT
      LAYER metal3 ;
      RECT 922.425 0.000 922.495 0.070 ;
    END
  END w0_wd_in[291]
  PIN w0_wd_in[292]
    DIRECTION INPUT ;
    USE SIGNAL ;
    SHAPE ABUTMENT ;
    PORT
      LAYER metal3 ;
      RECT 922.565 0.000 922.635 0.070 ;
    END
  END w0_wd_in[292]
  PIN w0_wd_in[293]
    DIRECTION INPUT ;
    USE SIGNAL ;
    SHAPE ABUTMENT ;
    PORT
      LAYER metal3 ;
      RECT 922.705 0.000 922.775 0.070 ;
    END
  END w0_wd_in[293]
  PIN w0_wd_in[294]
    DIRECTION INPUT ;
    USE SIGNAL ;
    SHAPE ABUTMENT ;
    PORT
      LAYER metal3 ;
      RECT 922.845 0.000 922.915 0.070 ;
    END
  END w0_wd_in[294]
  PIN w0_wd_in[295]
    DIRECTION INPUT ;
    USE SIGNAL ;
    SHAPE ABUTMENT ;
    PORT
      LAYER metal3 ;
      RECT 922.985 0.000 923.055 0.070 ;
    END
  END w0_wd_in[295]
  PIN w0_wd_in[296]
    DIRECTION INPUT ;
    USE SIGNAL ;
    SHAPE ABUTMENT ;
    PORT
      LAYER metal3 ;
      RECT 923.125 0.000 923.195 0.070 ;
    END
  END w0_wd_in[296]
  PIN w0_wd_in[297]
    DIRECTION INPUT ;
    USE SIGNAL ;
    SHAPE ABUTMENT ;
    PORT
      LAYER metal3 ;
      RECT 923.265 0.000 923.335 0.070 ;
    END
  END w0_wd_in[297]
  PIN w0_wd_in[298]
    DIRECTION INPUT ;
    USE SIGNAL ;
    SHAPE ABUTMENT ;
    PORT
      LAYER metal3 ;
      RECT 923.405 0.000 923.475 0.070 ;
    END
  END w0_wd_in[298]
  PIN w0_wd_in[299]
    DIRECTION INPUT ;
    USE SIGNAL ;
    SHAPE ABUTMENT ;
    PORT
      LAYER metal3 ;
      RECT 923.545 0.000 923.615 0.070 ;
    END
  END w0_wd_in[299]
  PIN w0_wd_in[300]
    DIRECTION INPUT ;
    USE SIGNAL ;
    SHAPE ABUTMENT ;
    PORT
      LAYER metal3 ;
      RECT 923.685 0.000 923.755 0.070 ;
    END
  END w0_wd_in[300]
  PIN w0_wd_in[301]
    DIRECTION INPUT ;
    USE SIGNAL ;
    SHAPE ABUTMENT ;
    PORT
      LAYER metal3 ;
      RECT 923.825 0.000 923.895 0.070 ;
    END
  END w0_wd_in[301]
  PIN w0_wd_in[302]
    DIRECTION INPUT ;
    USE SIGNAL ;
    SHAPE ABUTMENT ;
    PORT
      LAYER metal3 ;
      RECT 923.965 0.000 924.035 0.070 ;
    END
  END w0_wd_in[302]
  PIN w0_wd_in[303]
    DIRECTION INPUT ;
    USE SIGNAL ;
    SHAPE ABUTMENT ;
    PORT
      LAYER metal3 ;
      RECT 924.105 0.000 924.175 0.070 ;
    END
  END w0_wd_in[303]
  PIN w0_wd_in[304]
    DIRECTION INPUT ;
    USE SIGNAL ;
    SHAPE ABUTMENT ;
    PORT
      LAYER metal3 ;
      RECT 924.245 0.000 924.315 0.070 ;
    END
  END w0_wd_in[304]
  PIN w0_wd_in[305]
    DIRECTION INPUT ;
    USE SIGNAL ;
    SHAPE ABUTMENT ;
    PORT
      LAYER metal3 ;
      RECT 924.385 0.000 924.455 0.070 ;
    END
  END w0_wd_in[305]
  PIN w0_wd_in[306]
    DIRECTION INPUT ;
    USE SIGNAL ;
    SHAPE ABUTMENT ;
    PORT
      LAYER metal3 ;
      RECT 924.525 0.000 924.595 0.070 ;
    END
  END w0_wd_in[306]
  PIN w0_wd_in[307]
    DIRECTION INPUT ;
    USE SIGNAL ;
    SHAPE ABUTMENT ;
    PORT
      LAYER metal3 ;
      RECT 924.665 0.000 924.735 0.070 ;
    END
  END w0_wd_in[307]
  PIN w0_wd_in[308]
    DIRECTION INPUT ;
    USE SIGNAL ;
    SHAPE ABUTMENT ;
    PORT
      LAYER metal3 ;
      RECT 924.805 0.000 924.875 0.070 ;
    END
  END w0_wd_in[308]
  PIN w0_wd_in[309]
    DIRECTION INPUT ;
    USE SIGNAL ;
    SHAPE ABUTMENT ;
    PORT
      LAYER metal3 ;
      RECT 924.945 0.000 925.015 0.070 ;
    END
  END w0_wd_in[309]
  PIN w0_wd_in[310]
    DIRECTION INPUT ;
    USE SIGNAL ;
    SHAPE ABUTMENT ;
    PORT
      LAYER metal3 ;
      RECT 925.085 0.000 925.155 0.070 ;
    END
  END w0_wd_in[310]
  PIN w0_wd_in[311]
    DIRECTION INPUT ;
    USE SIGNAL ;
    SHAPE ABUTMENT ;
    PORT
      LAYER metal3 ;
      RECT 925.225 0.000 925.295 0.070 ;
    END
  END w0_wd_in[311]
  PIN w0_wd_in[312]
    DIRECTION INPUT ;
    USE SIGNAL ;
    SHAPE ABUTMENT ;
    PORT
      LAYER metal3 ;
      RECT 925.365 0.000 925.435 0.070 ;
    END
  END w0_wd_in[312]
  PIN w0_wd_in[313]
    DIRECTION INPUT ;
    USE SIGNAL ;
    SHAPE ABUTMENT ;
    PORT
      LAYER metal3 ;
      RECT 925.505 0.000 925.575 0.070 ;
    END
  END w0_wd_in[313]
  PIN w0_wd_in[314]
    DIRECTION INPUT ;
    USE SIGNAL ;
    SHAPE ABUTMENT ;
    PORT
      LAYER metal3 ;
      RECT 925.645 0.000 925.715 0.070 ;
    END
  END w0_wd_in[314]
  PIN w0_wd_in[315]
    DIRECTION INPUT ;
    USE SIGNAL ;
    SHAPE ABUTMENT ;
    PORT
      LAYER metal3 ;
      RECT 925.785 0.000 925.855 0.070 ;
    END
  END w0_wd_in[315]
  PIN w0_wd_in[316]
    DIRECTION INPUT ;
    USE SIGNAL ;
    SHAPE ABUTMENT ;
    PORT
      LAYER metal3 ;
      RECT 925.925 0.000 925.995 0.070 ;
    END
  END w0_wd_in[316]
  PIN w0_wd_in[317]
    DIRECTION INPUT ;
    USE SIGNAL ;
    SHAPE ABUTMENT ;
    PORT
      LAYER metal3 ;
      RECT 926.065 0.000 926.135 0.070 ;
    END
  END w0_wd_in[317]
  PIN w0_wd_in[318]
    DIRECTION INPUT ;
    USE SIGNAL ;
    SHAPE ABUTMENT ;
    PORT
      LAYER metal3 ;
      RECT 926.205 0.000 926.275 0.070 ;
    END
  END w0_wd_in[318]
  PIN w0_wd_in[319]
    DIRECTION INPUT ;
    USE SIGNAL ;
    SHAPE ABUTMENT ;
    PORT
      LAYER metal3 ;
      RECT 926.345 0.000 926.415 0.070 ;
    END
  END w0_wd_in[319]
  PIN w0_wd_in[320]
    DIRECTION INPUT ;
    USE SIGNAL ;
    SHAPE ABUTMENT ;
    PORT
      LAYER metal3 ;
      RECT 926.485 0.000 926.555 0.070 ;
    END
  END w0_wd_in[320]
  PIN w0_wd_in[321]
    DIRECTION INPUT ;
    USE SIGNAL ;
    SHAPE ABUTMENT ;
    PORT
      LAYER metal3 ;
      RECT 926.625 0.000 926.695 0.070 ;
    END
  END w0_wd_in[321]
  PIN w0_wd_in[322]
    DIRECTION INPUT ;
    USE SIGNAL ;
    SHAPE ABUTMENT ;
    PORT
      LAYER metal3 ;
      RECT 926.765 0.000 926.835 0.070 ;
    END
  END w0_wd_in[322]
  PIN w0_wd_in[323]
    DIRECTION INPUT ;
    USE SIGNAL ;
    SHAPE ABUTMENT ;
    PORT
      LAYER metal3 ;
      RECT 926.905 0.000 926.975 0.070 ;
    END
  END w0_wd_in[323]
  PIN w0_wd_in[324]
    DIRECTION INPUT ;
    USE SIGNAL ;
    SHAPE ABUTMENT ;
    PORT
      LAYER metal3 ;
      RECT 927.045 0.000 927.115 0.070 ;
    END
  END w0_wd_in[324]
  PIN w0_wd_in[325]
    DIRECTION INPUT ;
    USE SIGNAL ;
    SHAPE ABUTMENT ;
    PORT
      LAYER metal3 ;
      RECT 927.185 0.000 927.255 0.070 ;
    END
  END w0_wd_in[325]
  PIN w0_wd_in[326]
    DIRECTION INPUT ;
    USE SIGNAL ;
    SHAPE ABUTMENT ;
    PORT
      LAYER metal3 ;
      RECT 927.325 0.000 927.395 0.070 ;
    END
  END w0_wd_in[326]
  PIN w0_wd_in[327]
    DIRECTION INPUT ;
    USE SIGNAL ;
    SHAPE ABUTMENT ;
    PORT
      LAYER metal3 ;
      RECT 927.465 0.000 927.535 0.070 ;
    END
  END w0_wd_in[327]
  PIN w0_wd_in[328]
    DIRECTION INPUT ;
    USE SIGNAL ;
    SHAPE ABUTMENT ;
    PORT
      LAYER metal3 ;
      RECT 927.605 0.000 927.675 0.070 ;
    END
  END w0_wd_in[328]
  PIN w0_wd_in[329]
    DIRECTION INPUT ;
    USE SIGNAL ;
    SHAPE ABUTMENT ;
    PORT
      LAYER metal3 ;
      RECT 927.745 0.000 927.815 0.070 ;
    END
  END w0_wd_in[329]
  PIN w0_wd_in[330]
    DIRECTION INPUT ;
    USE SIGNAL ;
    SHAPE ABUTMENT ;
    PORT
      LAYER metal3 ;
      RECT 927.885 0.000 927.955 0.070 ;
    END
  END w0_wd_in[330]
  PIN w0_wd_in[331]
    DIRECTION INPUT ;
    USE SIGNAL ;
    SHAPE ABUTMENT ;
    PORT
      LAYER metal3 ;
      RECT 928.025 0.000 928.095 0.070 ;
    END
  END w0_wd_in[331]
  PIN w0_wd_in[332]
    DIRECTION INPUT ;
    USE SIGNAL ;
    SHAPE ABUTMENT ;
    PORT
      LAYER metal3 ;
      RECT 928.165 0.000 928.235 0.070 ;
    END
  END w0_wd_in[332]
  PIN w0_wd_in[333]
    DIRECTION INPUT ;
    USE SIGNAL ;
    SHAPE ABUTMENT ;
    PORT
      LAYER metal3 ;
      RECT 928.305 0.000 928.375 0.070 ;
    END
  END w0_wd_in[333]
  PIN w0_wd_in[334]
    DIRECTION INPUT ;
    USE SIGNAL ;
    SHAPE ABUTMENT ;
    PORT
      LAYER metal3 ;
      RECT 928.445 0.000 928.515 0.070 ;
    END
  END w0_wd_in[334]
  PIN w0_wd_in[335]
    DIRECTION INPUT ;
    USE SIGNAL ;
    SHAPE ABUTMENT ;
    PORT
      LAYER metal3 ;
      RECT 928.585 0.000 928.655 0.070 ;
    END
  END w0_wd_in[335]
  PIN w0_wd_in[336]
    DIRECTION INPUT ;
    USE SIGNAL ;
    SHAPE ABUTMENT ;
    PORT
      LAYER metal3 ;
      RECT 928.725 0.000 928.795 0.070 ;
    END
  END w0_wd_in[336]
  PIN w0_wd_in[337]
    DIRECTION INPUT ;
    USE SIGNAL ;
    SHAPE ABUTMENT ;
    PORT
      LAYER metal3 ;
      RECT 928.865 0.000 928.935 0.070 ;
    END
  END w0_wd_in[337]
  PIN w0_wd_in[338]
    DIRECTION INPUT ;
    USE SIGNAL ;
    SHAPE ABUTMENT ;
    PORT
      LAYER metal3 ;
      RECT 929.005 0.000 929.075 0.070 ;
    END
  END w0_wd_in[338]
  PIN w0_wd_in[339]
    DIRECTION INPUT ;
    USE SIGNAL ;
    SHAPE ABUTMENT ;
    PORT
      LAYER metal3 ;
      RECT 929.145 0.000 929.215 0.070 ;
    END
  END w0_wd_in[339]
  PIN w0_wd_in[340]
    DIRECTION INPUT ;
    USE SIGNAL ;
    SHAPE ABUTMENT ;
    PORT
      LAYER metal3 ;
      RECT 929.285 0.000 929.355 0.070 ;
    END
  END w0_wd_in[340]
  PIN w0_wd_in[341]
    DIRECTION INPUT ;
    USE SIGNAL ;
    SHAPE ABUTMENT ;
    PORT
      LAYER metal3 ;
      RECT 929.425 0.000 929.495 0.070 ;
    END
  END w0_wd_in[341]
  PIN w0_wd_in[342]
    DIRECTION INPUT ;
    USE SIGNAL ;
    SHAPE ABUTMENT ;
    PORT
      LAYER metal3 ;
      RECT 929.565 0.000 929.635 0.070 ;
    END
  END w0_wd_in[342]
  PIN w0_wd_in[343]
    DIRECTION INPUT ;
    USE SIGNAL ;
    SHAPE ABUTMENT ;
    PORT
      LAYER metal3 ;
      RECT 929.705 0.000 929.775 0.070 ;
    END
  END w0_wd_in[343]
  PIN w0_wd_in[344]
    DIRECTION INPUT ;
    USE SIGNAL ;
    SHAPE ABUTMENT ;
    PORT
      LAYER metal3 ;
      RECT 929.845 0.000 929.915 0.070 ;
    END
  END w0_wd_in[344]
  PIN w0_wd_in[345]
    DIRECTION INPUT ;
    USE SIGNAL ;
    SHAPE ABUTMENT ;
    PORT
      LAYER metal3 ;
      RECT 929.985 0.000 930.055 0.070 ;
    END
  END w0_wd_in[345]
  PIN w0_wd_in[346]
    DIRECTION INPUT ;
    USE SIGNAL ;
    SHAPE ABUTMENT ;
    PORT
      LAYER metal3 ;
      RECT 930.125 0.000 930.195 0.070 ;
    END
  END w0_wd_in[346]
  PIN w0_wd_in[347]
    DIRECTION INPUT ;
    USE SIGNAL ;
    SHAPE ABUTMENT ;
    PORT
      LAYER metal3 ;
      RECT 930.265 0.000 930.335 0.070 ;
    END
  END w0_wd_in[347]
  PIN w0_wd_in[348]
    DIRECTION INPUT ;
    USE SIGNAL ;
    SHAPE ABUTMENT ;
    PORT
      LAYER metal3 ;
      RECT 930.405 0.000 930.475 0.070 ;
    END
  END w0_wd_in[348]
  PIN w0_wd_in[349]
    DIRECTION INPUT ;
    USE SIGNAL ;
    SHAPE ABUTMENT ;
    PORT
      LAYER metal3 ;
      RECT 930.545 0.000 930.615 0.070 ;
    END
  END w0_wd_in[349]
  PIN w0_wd_in[350]
    DIRECTION INPUT ;
    USE SIGNAL ;
    SHAPE ABUTMENT ;
    PORT
      LAYER metal3 ;
      RECT 930.685 0.000 930.755 0.070 ;
    END
  END w0_wd_in[350]
  PIN w0_wd_in[351]
    DIRECTION INPUT ;
    USE SIGNAL ;
    SHAPE ABUTMENT ;
    PORT
      LAYER metal3 ;
      RECT 930.825 0.000 930.895 0.070 ;
    END
  END w0_wd_in[351]
  PIN w0_wd_in[352]
    DIRECTION INPUT ;
    USE SIGNAL ;
    SHAPE ABUTMENT ;
    PORT
      LAYER metal3 ;
      RECT 930.965 0.000 931.035 0.070 ;
    END
  END w0_wd_in[352]
  PIN w0_wd_in[353]
    DIRECTION INPUT ;
    USE SIGNAL ;
    SHAPE ABUTMENT ;
    PORT
      LAYER metal3 ;
      RECT 931.105 0.000 931.175 0.070 ;
    END
  END w0_wd_in[353]
  PIN w0_wd_in[354]
    DIRECTION INPUT ;
    USE SIGNAL ;
    SHAPE ABUTMENT ;
    PORT
      LAYER metal3 ;
      RECT 931.245 0.000 931.315 0.070 ;
    END
  END w0_wd_in[354]
  PIN w0_wd_in[355]
    DIRECTION INPUT ;
    USE SIGNAL ;
    SHAPE ABUTMENT ;
    PORT
      LAYER metal3 ;
      RECT 931.385 0.000 931.455 0.070 ;
    END
  END w0_wd_in[355]
  PIN w0_wd_in[356]
    DIRECTION INPUT ;
    USE SIGNAL ;
    SHAPE ABUTMENT ;
    PORT
      LAYER metal3 ;
      RECT 931.525 0.000 931.595 0.070 ;
    END
  END w0_wd_in[356]
  PIN w0_wd_in[357]
    DIRECTION INPUT ;
    USE SIGNAL ;
    SHAPE ABUTMENT ;
    PORT
      LAYER metal3 ;
      RECT 931.665 0.000 931.735 0.070 ;
    END
  END w0_wd_in[357]
  PIN w0_wd_in[358]
    DIRECTION INPUT ;
    USE SIGNAL ;
    SHAPE ABUTMENT ;
    PORT
      LAYER metal3 ;
      RECT 931.805 0.000 931.875 0.070 ;
    END
  END w0_wd_in[358]
  PIN w0_wd_in[359]
    DIRECTION INPUT ;
    USE SIGNAL ;
    SHAPE ABUTMENT ;
    PORT
      LAYER metal3 ;
      RECT 931.945 0.000 932.015 0.070 ;
    END
  END w0_wd_in[359]
  PIN w0_wd_in[360]
    DIRECTION INPUT ;
    USE SIGNAL ;
    SHAPE ABUTMENT ;
    PORT
      LAYER metal3 ;
      RECT 932.085 0.000 932.155 0.070 ;
    END
  END w0_wd_in[360]
  PIN w0_wd_in[361]
    DIRECTION INPUT ;
    USE SIGNAL ;
    SHAPE ABUTMENT ;
    PORT
      LAYER metal3 ;
      RECT 932.225 0.000 932.295 0.070 ;
    END
  END w0_wd_in[361]
  PIN w0_wd_in[362]
    DIRECTION INPUT ;
    USE SIGNAL ;
    SHAPE ABUTMENT ;
    PORT
      LAYER metal3 ;
      RECT 932.365 0.000 932.435 0.070 ;
    END
  END w0_wd_in[362]
  PIN w0_wd_in[363]
    DIRECTION INPUT ;
    USE SIGNAL ;
    SHAPE ABUTMENT ;
    PORT
      LAYER metal3 ;
      RECT 932.505 0.000 932.575 0.070 ;
    END
  END w0_wd_in[363]
  PIN w0_wd_in[364]
    DIRECTION INPUT ;
    USE SIGNAL ;
    SHAPE ABUTMENT ;
    PORT
      LAYER metal3 ;
      RECT 932.645 0.000 932.715 0.070 ;
    END
  END w0_wd_in[364]
  PIN w0_wd_in[365]
    DIRECTION INPUT ;
    USE SIGNAL ;
    SHAPE ABUTMENT ;
    PORT
      LAYER metal3 ;
      RECT 932.785 0.000 932.855 0.070 ;
    END
  END w0_wd_in[365]
  PIN w0_wd_in[366]
    DIRECTION INPUT ;
    USE SIGNAL ;
    SHAPE ABUTMENT ;
    PORT
      LAYER metal3 ;
      RECT 932.925 0.000 932.995 0.070 ;
    END
  END w0_wd_in[366]
  PIN w0_wd_in[367]
    DIRECTION INPUT ;
    USE SIGNAL ;
    SHAPE ABUTMENT ;
    PORT
      LAYER metal3 ;
      RECT 933.065 0.000 933.135 0.070 ;
    END
  END w0_wd_in[367]
  PIN w0_wd_in[368]
    DIRECTION INPUT ;
    USE SIGNAL ;
    SHAPE ABUTMENT ;
    PORT
      LAYER metal3 ;
      RECT 933.205 0.000 933.275 0.070 ;
    END
  END w0_wd_in[368]
  PIN w0_wd_in[369]
    DIRECTION INPUT ;
    USE SIGNAL ;
    SHAPE ABUTMENT ;
    PORT
      LAYER metal3 ;
      RECT 933.345 0.000 933.415 0.070 ;
    END
  END w0_wd_in[369]
  PIN w0_wd_in[370]
    DIRECTION INPUT ;
    USE SIGNAL ;
    SHAPE ABUTMENT ;
    PORT
      LAYER metal3 ;
      RECT 933.485 0.000 933.555 0.070 ;
    END
  END w0_wd_in[370]
  PIN w0_wd_in[371]
    DIRECTION INPUT ;
    USE SIGNAL ;
    SHAPE ABUTMENT ;
    PORT
      LAYER metal3 ;
      RECT 933.625 0.000 933.695 0.070 ;
    END
  END w0_wd_in[371]
  PIN w0_wd_in[372]
    DIRECTION INPUT ;
    USE SIGNAL ;
    SHAPE ABUTMENT ;
    PORT
      LAYER metal3 ;
      RECT 933.765 0.000 933.835 0.070 ;
    END
  END w0_wd_in[372]
  PIN w0_wd_in[373]
    DIRECTION INPUT ;
    USE SIGNAL ;
    SHAPE ABUTMENT ;
    PORT
      LAYER metal3 ;
      RECT 933.905 0.000 933.975 0.070 ;
    END
  END w0_wd_in[373]
  PIN w0_wd_in[374]
    DIRECTION INPUT ;
    USE SIGNAL ;
    SHAPE ABUTMENT ;
    PORT
      LAYER metal3 ;
      RECT 934.045 0.000 934.115 0.070 ;
    END
  END w0_wd_in[374]
  PIN w0_wd_in[375]
    DIRECTION INPUT ;
    USE SIGNAL ;
    SHAPE ABUTMENT ;
    PORT
      LAYER metal3 ;
      RECT 934.185 0.000 934.255 0.070 ;
    END
  END w0_wd_in[375]
  PIN w0_wd_in[376]
    DIRECTION INPUT ;
    USE SIGNAL ;
    SHAPE ABUTMENT ;
    PORT
      LAYER metal3 ;
      RECT 934.325 0.000 934.395 0.070 ;
    END
  END w0_wd_in[376]
  PIN w0_wd_in[377]
    DIRECTION INPUT ;
    USE SIGNAL ;
    SHAPE ABUTMENT ;
    PORT
      LAYER metal3 ;
      RECT 934.465 0.000 934.535 0.070 ;
    END
  END w0_wd_in[377]
  PIN w0_wd_in[378]
    DIRECTION INPUT ;
    USE SIGNAL ;
    SHAPE ABUTMENT ;
    PORT
      LAYER metal3 ;
      RECT 934.605 0.000 934.675 0.070 ;
    END
  END w0_wd_in[378]
  PIN w0_wd_in[379]
    DIRECTION INPUT ;
    USE SIGNAL ;
    SHAPE ABUTMENT ;
    PORT
      LAYER metal3 ;
      RECT 934.745 0.000 934.815 0.070 ;
    END
  END w0_wd_in[379]
  PIN w0_wd_in[380]
    DIRECTION INPUT ;
    USE SIGNAL ;
    SHAPE ABUTMENT ;
    PORT
      LAYER metal3 ;
      RECT 934.885 0.000 934.955 0.070 ;
    END
  END w0_wd_in[380]
  PIN w0_wd_in[381]
    DIRECTION INPUT ;
    USE SIGNAL ;
    SHAPE ABUTMENT ;
    PORT
      LAYER metal3 ;
      RECT 935.025 0.000 935.095 0.070 ;
    END
  END w0_wd_in[381]
  PIN w0_wd_in[382]
    DIRECTION INPUT ;
    USE SIGNAL ;
    SHAPE ABUTMENT ;
    PORT
      LAYER metal3 ;
      RECT 935.165 0.000 935.235 0.070 ;
    END
  END w0_wd_in[382]
  PIN w0_wd_in[383]
    DIRECTION INPUT ;
    USE SIGNAL ;
    SHAPE ABUTMENT ;
    PORT
      LAYER metal3 ;
      RECT 935.305 0.000 935.375 0.070 ;
    END
  END w0_wd_in[383]
  PIN w0_wd_in[384]
    DIRECTION INPUT ;
    USE SIGNAL ;
    SHAPE ABUTMENT ;
    PORT
      LAYER metal3 ;
      RECT 935.445 0.000 935.515 0.070 ;
    END
  END w0_wd_in[384]
  PIN w0_wd_in[385]
    DIRECTION INPUT ;
    USE SIGNAL ;
    SHAPE ABUTMENT ;
    PORT
      LAYER metal3 ;
      RECT 935.585 0.000 935.655 0.070 ;
    END
  END w0_wd_in[385]
  PIN w0_wd_in[386]
    DIRECTION INPUT ;
    USE SIGNAL ;
    SHAPE ABUTMENT ;
    PORT
      LAYER metal3 ;
      RECT 935.725 0.000 935.795 0.070 ;
    END
  END w0_wd_in[386]
  PIN w0_wd_in[387]
    DIRECTION INPUT ;
    USE SIGNAL ;
    SHAPE ABUTMENT ;
    PORT
      LAYER metal3 ;
      RECT 935.865 0.000 935.935 0.070 ;
    END
  END w0_wd_in[387]
  PIN w0_wd_in[388]
    DIRECTION INPUT ;
    USE SIGNAL ;
    SHAPE ABUTMENT ;
    PORT
      LAYER metal3 ;
      RECT 936.005 0.000 936.075 0.070 ;
    END
  END w0_wd_in[388]
  PIN w0_wd_in[389]
    DIRECTION INPUT ;
    USE SIGNAL ;
    SHAPE ABUTMENT ;
    PORT
      LAYER metal3 ;
      RECT 936.145 0.000 936.215 0.070 ;
    END
  END w0_wd_in[389]
  PIN w0_wd_in[390]
    DIRECTION INPUT ;
    USE SIGNAL ;
    SHAPE ABUTMENT ;
    PORT
      LAYER metal3 ;
      RECT 936.285 0.000 936.355 0.070 ;
    END
  END w0_wd_in[390]
  PIN w0_wd_in[391]
    DIRECTION INPUT ;
    USE SIGNAL ;
    SHAPE ABUTMENT ;
    PORT
      LAYER metal3 ;
      RECT 936.425 0.000 936.495 0.070 ;
    END
  END w0_wd_in[391]
  PIN w0_wd_in[392]
    DIRECTION INPUT ;
    USE SIGNAL ;
    SHAPE ABUTMENT ;
    PORT
      LAYER metal3 ;
      RECT 936.565 0.000 936.635 0.070 ;
    END
  END w0_wd_in[392]
  PIN w0_wd_in[393]
    DIRECTION INPUT ;
    USE SIGNAL ;
    SHAPE ABUTMENT ;
    PORT
      LAYER metal3 ;
      RECT 936.705 0.000 936.775 0.070 ;
    END
  END w0_wd_in[393]
  PIN w0_wd_in[394]
    DIRECTION INPUT ;
    USE SIGNAL ;
    SHAPE ABUTMENT ;
    PORT
      LAYER metal3 ;
      RECT 936.845 0.000 936.915 0.070 ;
    END
  END w0_wd_in[394]
  PIN w0_wd_in[395]
    DIRECTION INPUT ;
    USE SIGNAL ;
    SHAPE ABUTMENT ;
    PORT
      LAYER metal3 ;
      RECT 936.985 0.000 937.055 0.070 ;
    END
  END w0_wd_in[395]
  PIN w0_wd_in[396]
    DIRECTION INPUT ;
    USE SIGNAL ;
    SHAPE ABUTMENT ;
    PORT
      LAYER metal3 ;
      RECT 937.125 0.000 937.195 0.070 ;
    END
  END w0_wd_in[396]
  PIN w0_wd_in[397]
    DIRECTION INPUT ;
    USE SIGNAL ;
    SHAPE ABUTMENT ;
    PORT
      LAYER metal3 ;
      RECT 937.265 0.000 937.335 0.070 ;
    END
  END w0_wd_in[397]
  PIN w0_wd_in[398]
    DIRECTION INPUT ;
    USE SIGNAL ;
    SHAPE ABUTMENT ;
    PORT
      LAYER metal3 ;
      RECT 937.405 0.000 937.475 0.070 ;
    END
  END w0_wd_in[398]
  PIN w0_wd_in[399]
    DIRECTION INPUT ;
    USE SIGNAL ;
    SHAPE ABUTMENT ;
    PORT
      LAYER metal3 ;
      RECT 937.545 0.000 937.615 0.070 ;
    END
  END w0_wd_in[399]
  PIN w0_wd_in[400]
    DIRECTION INPUT ;
    USE SIGNAL ;
    SHAPE ABUTMENT ;
    PORT
      LAYER metal3 ;
      RECT 937.685 0.000 937.755 0.070 ;
    END
  END w0_wd_in[400]
  PIN w0_wd_in[401]
    DIRECTION INPUT ;
    USE SIGNAL ;
    SHAPE ABUTMENT ;
    PORT
      LAYER metal3 ;
      RECT 937.825 0.000 937.895 0.070 ;
    END
  END w0_wd_in[401]
  PIN w0_wd_in[402]
    DIRECTION INPUT ;
    USE SIGNAL ;
    SHAPE ABUTMENT ;
    PORT
      LAYER metal3 ;
      RECT 937.965 0.000 938.035 0.070 ;
    END
  END w0_wd_in[402]
  PIN w0_wd_in[403]
    DIRECTION INPUT ;
    USE SIGNAL ;
    SHAPE ABUTMENT ;
    PORT
      LAYER metal3 ;
      RECT 938.105 0.000 938.175 0.070 ;
    END
  END w0_wd_in[403]
  PIN w0_wd_in[404]
    DIRECTION INPUT ;
    USE SIGNAL ;
    SHAPE ABUTMENT ;
    PORT
      LAYER metal3 ;
      RECT 938.245 0.000 938.315 0.070 ;
    END
  END w0_wd_in[404]
  PIN w0_wd_in[405]
    DIRECTION INPUT ;
    USE SIGNAL ;
    SHAPE ABUTMENT ;
    PORT
      LAYER metal3 ;
      RECT 938.385 0.000 938.455 0.070 ;
    END
  END w0_wd_in[405]
  PIN w0_wd_in[406]
    DIRECTION INPUT ;
    USE SIGNAL ;
    SHAPE ABUTMENT ;
    PORT
      LAYER metal3 ;
      RECT 938.525 0.000 938.595 0.070 ;
    END
  END w0_wd_in[406]
  PIN w0_wd_in[407]
    DIRECTION INPUT ;
    USE SIGNAL ;
    SHAPE ABUTMENT ;
    PORT
      LAYER metal3 ;
      RECT 938.665 0.000 938.735 0.070 ;
    END
  END w0_wd_in[407]
  PIN w0_wd_in[408]
    DIRECTION INPUT ;
    USE SIGNAL ;
    SHAPE ABUTMENT ;
    PORT
      LAYER metal3 ;
      RECT 938.805 0.000 938.875 0.070 ;
    END
  END w0_wd_in[408]
  PIN w0_wd_in[409]
    DIRECTION INPUT ;
    USE SIGNAL ;
    SHAPE ABUTMENT ;
    PORT
      LAYER metal3 ;
      RECT 938.945 0.000 939.015 0.070 ;
    END
  END w0_wd_in[409]
  PIN w0_wd_in[410]
    DIRECTION INPUT ;
    USE SIGNAL ;
    SHAPE ABUTMENT ;
    PORT
      LAYER metal3 ;
      RECT 939.085 0.000 939.155 0.070 ;
    END
  END w0_wd_in[410]
  PIN w0_wd_in[411]
    DIRECTION INPUT ;
    USE SIGNAL ;
    SHAPE ABUTMENT ;
    PORT
      LAYER metal3 ;
      RECT 939.225 0.000 939.295 0.070 ;
    END
  END w0_wd_in[411]
  PIN w0_wd_in[412]
    DIRECTION INPUT ;
    USE SIGNAL ;
    SHAPE ABUTMENT ;
    PORT
      LAYER metal3 ;
      RECT 939.365 0.000 939.435 0.070 ;
    END
  END w0_wd_in[412]
  PIN w0_wd_in[413]
    DIRECTION INPUT ;
    USE SIGNAL ;
    SHAPE ABUTMENT ;
    PORT
      LAYER metal3 ;
      RECT 939.505 0.000 939.575 0.070 ;
    END
  END w0_wd_in[413]
  PIN w0_wd_in[414]
    DIRECTION INPUT ;
    USE SIGNAL ;
    SHAPE ABUTMENT ;
    PORT
      LAYER metal3 ;
      RECT 939.645 0.000 939.715 0.070 ;
    END
  END w0_wd_in[414]
  PIN w0_wd_in[415]
    DIRECTION INPUT ;
    USE SIGNAL ;
    SHAPE ABUTMENT ;
    PORT
      LAYER metal3 ;
      RECT 939.785 0.000 939.855 0.070 ;
    END
  END w0_wd_in[415]
  PIN w0_wd_in[416]
    DIRECTION INPUT ;
    USE SIGNAL ;
    SHAPE ABUTMENT ;
    PORT
      LAYER metal3 ;
      RECT 939.925 0.000 939.995 0.070 ;
    END
  END w0_wd_in[416]
  PIN w0_wd_in[417]
    DIRECTION INPUT ;
    USE SIGNAL ;
    SHAPE ABUTMENT ;
    PORT
      LAYER metal3 ;
      RECT 940.065 0.000 940.135 0.070 ;
    END
  END w0_wd_in[417]
  PIN w0_wd_in[418]
    DIRECTION INPUT ;
    USE SIGNAL ;
    SHAPE ABUTMENT ;
    PORT
      LAYER metal3 ;
      RECT 940.205 0.000 940.275 0.070 ;
    END
  END w0_wd_in[418]
  PIN w0_wd_in[419]
    DIRECTION INPUT ;
    USE SIGNAL ;
    SHAPE ABUTMENT ;
    PORT
      LAYER metal3 ;
      RECT 940.345 0.000 940.415 0.070 ;
    END
  END w0_wd_in[419]
  PIN w0_wd_in[420]
    DIRECTION INPUT ;
    USE SIGNAL ;
    SHAPE ABUTMENT ;
    PORT
      LAYER metal3 ;
      RECT 940.485 0.000 940.555 0.070 ;
    END
  END w0_wd_in[420]
  PIN w0_wd_in[421]
    DIRECTION INPUT ;
    USE SIGNAL ;
    SHAPE ABUTMENT ;
    PORT
      LAYER metal3 ;
      RECT 940.625 0.000 940.695 0.070 ;
    END
  END w0_wd_in[421]
  PIN w0_wd_in[422]
    DIRECTION INPUT ;
    USE SIGNAL ;
    SHAPE ABUTMENT ;
    PORT
      LAYER metal3 ;
      RECT 940.765 0.000 940.835 0.070 ;
    END
  END w0_wd_in[422]
  PIN w0_wd_in[423]
    DIRECTION INPUT ;
    USE SIGNAL ;
    SHAPE ABUTMENT ;
    PORT
      LAYER metal3 ;
      RECT 940.905 0.000 940.975 0.070 ;
    END
  END w0_wd_in[423]
  PIN w0_wd_in[424]
    DIRECTION INPUT ;
    USE SIGNAL ;
    SHAPE ABUTMENT ;
    PORT
      LAYER metal3 ;
      RECT 941.045 0.000 941.115 0.070 ;
    END
  END w0_wd_in[424]
  PIN w0_wd_in[425]
    DIRECTION INPUT ;
    USE SIGNAL ;
    SHAPE ABUTMENT ;
    PORT
      LAYER metal3 ;
      RECT 941.185 0.000 941.255 0.070 ;
    END
  END w0_wd_in[425]
  PIN w0_wd_in[426]
    DIRECTION INPUT ;
    USE SIGNAL ;
    SHAPE ABUTMENT ;
    PORT
      LAYER metal3 ;
      RECT 941.325 0.000 941.395 0.070 ;
    END
  END w0_wd_in[426]
  PIN w0_wd_in[427]
    DIRECTION INPUT ;
    USE SIGNAL ;
    SHAPE ABUTMENT ;
    PORT
      LAYER metal3 ;
      RECT 941.465 0.000 941.535 0.070 ;
    END
  END w0_wd_in[427]
  PIN w0_wd_in[428]
    DIRECTION INPUT ;
    USE SIGNAL ;
    SHAPE ABUTMENT ;
    PORT
      LAYER metal3 ;
      RECT 941.605 0.000 941.675 0.070 ;
    END
  END w0_wd_in[428]
  PIN w0_wd_in[429]
    DIRECTION INPUT ;
    USE SIGNAL ;
    SHAPE ABUTMENT ;
    PORT
      LAYER metal3 ;
      RECT 941.745 0.000 941.815 0.070 ;
    END
  END w0_wd_in[429]
  PIN w0_wd_in[430]
    DIRECTION INPUT ;
    USE SIGNAL ;
    SHAPE ABUTMENT ;
    PORT
      LAYER metal3 ;
      RECT 941.885 0.000 941.955 0.070 ;
    END
  END w0_wd_in[430]
  PIN w0_wd_in[431]
    DIRECTION INPUT ;
    USE SIGNAL ;
    SHAPE ABUTMENT ;
    PORT
      LAYER metal3 ;
      RECT 942.025 0.000 942.095 0.070 ;
    END
  END w0_wd_in[431]
  PIN w0_wd_in[432]
    DIRECTION INPUT ;
    USE SIGNAL ;
    SHAPE ABUTMENT ;
    PORT
      LAYER metal3 ;
      RECT 942.165 0.000 942.235 0.070 ;
    END
  END w0_wd_in[432]
  PIN w0_wd_in[433]
    DIRECTION INPUT ;
    USE SIGNAL ;
    SHAPE ABUTMENT ;
    PORT
      LAYER metal3 ;
      RECT 942.305 0.000 942.375 0.070 ;
    END
  END w0_wd_in[433]
  PIN w0_wd_in[434]
    DIRECTION INPUT ;
    USE SIGNAL ;
    SHAPE ABUTMENT ;
    PORT
      LAYER metal3 ;
      RECT 942.445 0.000 942.515 0.070 ;
    END
  END w0_wd_in[434]
  PIN w0_wd_in[435]
    DIRECTION INPUT ;
    USE SIGNAL ;
    SHAPE ABUTMENT ;
    PORT
      LAYER metal3 ;
      RECT 942.585 0.000 942.655 0.070 ;
    END
  END w0_wd_in[435]
  PIN w0_wd_in[436]
    DIRECTION INPUT ;
    USE SIGNAL ;
    SHAPE ABUTMENT ;
    PORT
      LAYER metal3 ;
      RECT 942.725 0.000 942.795 0.070 ;
    END
  END w0_wd_in[436]
  PIN w0_wd_in[437]
    DIRECTION INPUT ;
    USE SIGNAL ;
    SHAPE ABUTMENT ;
    PORT
      LAYER metal3 ;
      RECT 942.865 0.000 942.935 0.070 ;
    END
  END w0_wd_in[437]
  PIN w0_wd_in[438]
    DIRECTION INPUT ;
    USE SIGNAL ;
    SHAPE ABUTMENT ;
    PORT
      LAYER metal3 ;
      RECT 943.005 0.000 943.075 0.070 ;
    END
  END w0_wd_in[438]
  PIN w0_wd_in[439]
    DIRECTION INPUT ;
    USE SIGNAL ;
    SHAPE ABUTMENT ;
    PORT
      LAYER metal3 ;
      RECT 943.145 0.000 943.215 0.070 ;
    END
  END w0_wd_in[439]
  PIN w0_wd_in[440]
    DIRECTION INPUT ;
    USE SIGNAL ;
    SHAPE ABUTMENT ;
    PORT
      LAYER metal3 ;
      RECT 943.285 0.000 943.355 0.070 ;
    END
  END w0_wd_in[440]
  PIN w0_wd_in[441]
    DIRECTION INPUT ;
    USE SIGNAL ;
    SHAPE ABUTMENT ;
    PORT
      LAYER metal3 ;
      RECT 943.425 0.000 943.495 0.070 ;
    END
  END w0_wd_in[441]
  PIN w0_wd_in[442]
    DIRECTION INPUT ;
    USE SIGNAL ;
    SHAPE ABUTMENT ;
    PORT
      LAYER metal3 ;
      RECT 943.565 0.000 943.635 0.070 ;
    END
  END w0_wd_in[442]
  PIN w0_wd_in[443]
    DIRECTION INPUT ;
    USE SIGNAL ;
    SHAPE ABUTMENT ;
    PORT
      LAYER metal3 ;
      RECT 943.705 0.000 943.775 0.070 ;
    END
  END w0_wd_in[443]
  PIN w0_wd_in[444]
    DIRECTION INPUT ;
    USE SIGNAL ;
    SHAPE ABUTMENT ;
    PORT
      LAYER metal3 ;
      RECT 943.845 0.000 943.915 0.070 ;
    END
  END w0_wd_in[444]
  PIN w0_wd_in[445]
    DIRECTION INPUT ;
    USE SIGNAL ;
    SHAPE ABUTMENT ;
    PORT
      LAYER metal3 ;
      RECT 943.985 0.000 944.055 0.070 ;
    END
  END w0_wd_in[445]
  PIN w0_wd_in[446]
    DIRECTION INPUT ;
    USE SIGNAL ;
    SHAPE ABUTMENT ;
    PORT
      LAYER metal3 ;
      RECT 944.125 0.000 944.195 0.070 ;
    END
  END w0_wd_in[446]
  PIN w0_wd_in[447]
    DIRECTION INPUT ;
    USE SIGNAL ;
    SHAPE ABUTMENT ;
    PORT
      LAYER metal3 ;
      RECT 944.265 0.000 944.335 0.070 ;
    END
  END w0_wd_in[447]
  PIN w0_wd_in[448]
    DIRECTION INPUT ;
    USE SIGNAL ;
    SHAPE ABUTMENT ;
    PORT
      LAYER metal3 ;
      RECT 944.405 0.000 944.475 0.070 ;
    END
  END w0_wd_in[448]
  PIN w0_wd_in[449]
    DIRECTION INPUT ;
    USE SIGNAL ;
    SHAPE ABUTMENT ;
    PORT
      LAYER metal3 ;
      RECT 944.545 0.000 944.615 0.070 ;
    END
  END w0_wd_in[449]
  PIN w0_wd_in[450]
    DIRECTION INPUT ;
    USE SIGNAL ;
    SHAPE ABUTMENT ;
    PORT
      LAYER metal3 ;
      RECT 944.685 0.000 944.755 0.070 ;
    END
  END w0_wd_in[450]
  PIN w0_wd_in[451]
    DIRECTION INPUT ;
    USE SIGNAL ;
    SHAPE ABUTMENT ;
    PORT
      LAYER metal3 ;
      RECT 944.825 0.000 944.895 0.070 ;
    END
  END w0_wd_in[451]
  PIN w0_wd_in[452]
    DIRECTION INPUT ;
    USE SIGNAL ;
    SHAPE ABUTMENT ;
    PORT
      LAYER metal3 ;
      RECT 944.965 0.000 945.035 0.070 ;
    END
  END w0_wd_in[452]
  PIN w0_wd_in[453]
    DIRECTION INPUT ;
    USE SIGNAL ;
    SHAPE ABUTMENT ;
    PORT
      LAYER metal3 ;
      RECT 945.105 0.000 945.175 0.070 ;
    END
  END w0_wd_in[453]
  PIN w0_wd_in[454]
    DIRECTION INPUT ;
    USE SIGNAL ;
    SHAPE ABUTMENT ;
    PORT
      LAYER metal3 ;
      RECT 945.245 0.000 945.315 0.070 ;
    END
  END w0_wd_in[454]
  PIN w0_wd_in[455]
    DIRECTION INPUT ;
    USE SIGNAL ;
    SHAPE ABUTMENT ;
    PORT
      LAYER metal3 ;
      RECT 945.385 0.000 945.455 0.070 ;
    END
  END w0_wd_in[455]
  PIN w0_wd_in[456]
    DIRECTION INPUT ;
    USE SIGNAL ;
    SHAPE ABUTMENT ;
    PORT
      LAYER metal3 ;
      RECT 945.525 0.000 945.595 0.070 ;
    END
  END w0_wd_in[456]
  PIN w0_wd_in[457]
    DIRECTION INPUT ;
    USE SIGNAL ;
    SHAPE ABUTMENT ;
    PORT
      LAYER metal3 ;
      RECT 945.665 0.000 945.735 0.070 ;
    END
  END w0_wd_in[457]
  PIN w0_wd_in[458]
    DIRECTION INPUT ;
    USE SIGNAL ;
    SHAPE ABUTMENT ;
    PORT
      LAYER metal3 ;
      RECT 945.805 0.000 945.875 0.070 ;
    END
  END w0_wd_in[458]
  PIN w0_wd_in[459]
    DIRECTION INPUT ;
    USE SIGNAL ;
    SHAPE ABUTMENT ;
    PORT
      LAYER metal3 ;
      RECT 945.945 0.000 946.015 0.070 ;
    END
  END w0_wd_in[459]
  PIN w0_wd_in[460]
    DIRECTION INPUT ;
    USE SIGNAL ;
    SHAPE ABUTMENT ;
    PORT
      LAYER metal3 ;
      RECT 946.085 0.000 946.155 0.070 ;
    END
  END w0_wd_in[460]
  PIN w0_wd_in[461]
    DIRECTION INPUT ;
    USE SIGNAL ;
    SHAPE ABUTMENT ;
    PORT
      LAYER metal3 ;
      RECT 946.225 0.000 946.295 0.070 ;
    END
  END w0_wd_in[461]
  PIN w0_wd_in[462]
    DIRECTION INPUT ;
    USE SIGNAL ;
    SHAPE ABUTMENT ;
    PORT
      LAYER metal3 ;
      RECT 946.365 0.000 946.435 0.070 ;
    END
  END w0_wd_in[462]
  PIN w0_wd_in[463]
    DIRECTION INPUT ;
    USE SIGNAL ;
    SHAPE ABUTMENT ;
    PORT
      LAYER metal3 ;
      RECT 946.505 0.000 946.575 0.070 ;
    END
  END w0_wd_in[463]
  PIN w0_wd_in[464]
    DIRECTION INPUT ;
    USE SIGNAL ;
    SHAPE ABUTMENT ;
    PORT
      LAYER metal3 ;
      RECT 946.645 0.000 946.715 0.070 ;
    END
  END w0_wd_in[464]
  PIN w0_wd_in[465]
    DIRECTION INPUT ;
    USE SIGNAL ;
    SHAPE ABUTMENT ;
    PORT
      LAYER metal3 ;
      RECT 946.785 0.000 946.855 0.070 ;
    END
  END w0_wd_in[465]
  PIN w0_wd_in[466]
    DIRECTION INPUT ;
    USE SIGNAL ;
    SHAPE ABUTMENT ;
    PORT
      LAYER metal3 ;
      RECT 946.925 0.000 946.995 0.070 ;
    END
  END w0_wd_in[466]
  PIN w0_wd_in[467]
    DIRECTION INPUT ;
    USE SIGNAL ;
    SHAPE ABUTMENT ;
    PORT
      LAYER metal3 ;
      RECT 947.065 0.000 947.135 0.070 ;
    END
  END w0_wd_in[467]
  PIN w0_wd_in[468]
    DIRECTION INPUT ;
    USE SIGNAL ;
    SHAPE ABUTMENT ;
    PORT
      LAYER metal3 ;
      RECT 947.205 0.000 947.275 0.070 ;
    END
  END w0_wd_in[468]
  PIN w0_wd_in[469]
    DIRECTION INPUT ;
    USE SIGNAL ;
    SHAPE ABUTMENT ;
    PORT
      LAYER metal3 ;
      RECT 947.345 0.000 947.415 0.070 ;
    END
  END w0_wd_in[469]
  PIN w0_wd_in[470]
    DIRECTION INPUT ;
    USE SIGNAL ;
    SHAPE ABUTMENT ;
    PORT
      LAYER metal3 ;
      RECT 947.485 0.000 947.555 0.070 ;
    END
  END w0_wd_in[470]
  PIN w0_wd_in[471]
    DIRECTION INPUT ;
    USE SIGNAL ;
    SHAPE ABUTMENT ;
    PORT
      LAYER metal3 ;
      RECT 947.625 0.000 947.695 0.070 ;
    END
  END w0_wd_in[471]
  PIN w0_wd_in[472]
    DIRECTION INPUT ;
    USE SIGNAL ;
    SHAPE ABUTMENT ;
    PORT
      LAYER metal3 ;
      RECT 947.765 0.000 947.835 0.070 ;
    END
  END w0_wd_in[472]
  PIN w0_wd_in[473]
    DIRECTION INPUT ;
    USE SIGNAL ;
    SHAPE ABUTMENT ;
    PORT
      LAYER metal3 ;
      RECT 947.905 0.000 947.975 0.070 ;
    END
  END w0_wd_in[473]
  PIN w0_wd_in[474]
    DIRECTION INPUT ;
    USE SIGNAL ;
    SHAPE ABUTMENT ;
    PORT
      LAYER metal3 ;
      RECT 948.045 0.000 948.115 0.070 ;
    END
  END w0_wd_in[474]
  PIN w0_wd_in[475]
    DIRECTION INPUT ;
    USE SIGNAL ;
    SHAPE ABUTMENT ;
    PORT
      LAYER metal3 ;
      RECT 948.185 0.000 948.255 0.070 ;
    END
  END w0_wd_in[475]
  PIN w0_wd_in[476]
    DIRECTION INPUT ;
    USE SIGNAL ;
    SHAPE ABUTMENT ;
    PORT
      LAYER metal3 ;
      RECT 948.325 0.000 948.395 0.070 ;
    END
  END w0_wd_in[476]
  PIN w0_wd_in[477]
    DIRECTION INPUT ;
    USE SIGNAL ;
    SHAPE ABUTMENT ;
    PORT
      LAYER metal3 ;
      RECT 948.465 0.000 948.535 0.070 ;
    END
  END w0_wd_in[477]
  PIN w0_wd_in[478]
    DIRECTION INPUT ;
    USE SIGNAL ;
    SHAPE ABUTMENT ;
    PORT
      LAYER metal3 ;
      RECT 948.605 0.000 948.675 0.070 ;
    END
  END w0_wd_in[478]
  PIN w0_wd_in[479]
    DIRECTION INPUT ;
    USE SIGNAL ;
    SHAPE ABUTMENT ;
    PORT
      LAYER metal3 ;
      RECT 948.745 0.000 948.815 0.070 ;
    END
  END w0_wd_in[479]
  PIN w0_wd_in[480]
    DIRECTION INPUT ;
    USE SIGNAL ;
    SHAPE ABUTMENT ;
    PORT
      LAYER metal3 ;
      RECT 948.885 0.000 948.955 0.070 ;
    END
  END w0_wd_in[480]
  PIN w0_wd_in[481]
    DIRECTION INPUT ;
    USE SIGNAL ;
    SHAPE ABUTMENT ;
    PORT
      LAYER metal3 ;
      RECT 949.025 0.000 949.095 0.070 ;
    END
  END w0_wd_in[481]
  PIN w0_wd_in[482]
    DIRECTION INPUT ;
    USE SIGNAL ;
    SHAPE ABUTMENT ;
    PORT
      LAYER metal3 ;
      RECT 949.165 0.000 949.235 0.070 ;
    END
  END w0_wd_in[482]
  PIN w0_wd_in[483]
    DIRECTION INPUT ;
    USE SIGNAL ;
    SHAPE ABUTMENT ;
    PORT
      LAYER metal3 ;
      RECT 949.305 0.000 949.375 0.070 ;
    END
  END w0_wd_in[483]
  PIN w0_wd_in[484]
    DIRECTION INPUT ;
    USE SIGNAL ;
    SHAPE ABUTMENT ;
    PORT
      LAYER metal3 ;
      RECT 949.445 0.000 949.515 0.070 ;
    END
  END w0_wd_in[484]
  PIN w0_wd_in[485]
    DIRECTION INPUT ;
    USE SIGNAL ;
    SHAPE ABUTMENT ;
    PORT
      LAYER metal3 ;
      RECT 949.585 0.000 949.655 0.070 ;
    END
  END w0_wd_in[485]
  PIN w0_wd_in[486]
    DIRECTION INPUT ;
    USE SIGNAL ;
    SHAPE ABUTMENT ;
    PORT
      LAYER metal3 ;
      RECT 949.725 0.000 949.795 0.070 ;
    END
  END w0_wd_in[486]
  PIN w0_wd_in[487]
    DIRECTION INPUT ;
    USE SIGNAL ;
    SHAPE ABUTMENT ;
    PORT
      LAYER metal3 ;
      RECT 949.865 0.000 949.935 0.070 ;
    END
  END w0_wd_in[487]
  PIN w0_wd_in[488]
    DIRECTION INPUT ;
    USE SIGNAL ;
    SHAPE ABUTMENT ;
    PORT
      LAYER metal3 ;
      RECT 950.005 0.000 950.075 0.070 ;
    END
  END w0_wd_in[488]
  PIN w0_wd_in[489]
    DIRECTION INPUT ;
    USE SIGNAL ;
    SHAPE ABUTMENT ;
    PORT
      LAYER metal3 ;
      RECT 950.145 0.000 950.215 0.070 ;
    END
  END w0_wd_in[489]
  PIN w0_wd_in[490]
    DIRECTION INPUT ;
    USE SIGNAL ;
    SHAPE ABUTMENT ;
    PORT
      LAYER metal3 ;
      RECT 950.285 0.000 950.355 0.070 ;
    END
  END w0_wd_in[490]
  PIN w0_wd_in[491]
    DIRECTION INPUT ;
    USE SIGNAL ;
    SHAPE ABUTMENT ;
    PORT
      LAYER metal3 ;
      RECT 950.425 0.000 950.495 0.070 ;
    END
  END w0_wd_in[491]
  PIN w0_wd_in[492]
    DIRECTION INPUT ;
    USE SIGNAL ;
    SHAPE ABUTMENT ;
    PORT
      LAYER metal3 ;
      RECT 950.565 0.000 950.635 0.070 ;
    END
  END w0_wd_in[492]
  PIN w0_wd_in[493]
    DIRECTION INPUT ;
    USE SIGNAL ;
    SHAPE ABUTMENT ;
    PORT
      LAYER metal3 ;
      RECT 950.705 0.000 950.775 0.070 ;
    END
  END w0_wd_in[493]
  PIN w0_wd_in[494]
    DIRECTION INPUT ;
    USE SIGNAL ;
    SHAPE ABUTMENT ;
    PORT
      LAYER metal3 ;
      RECT 950.845 0.000 950.915 0.070 ;
    END
  END w0_wd_in[494]
  PIN w0_wd_in[495]
    DIRECTION INPUT ;
    USE SIGNAL ;
    SHAPE ABUTMENT ;
    PORT
      LAYER metal3 ;
      RECT 950.985 0.000 951.055 0.070 ;
    END
  END w0_wd_in[495]
  PIN w0_wd_in[496]
    DIRECTION INPUT ;
    USE SIGNAL ;
    SHAPE ABUTMENT ;
    PORT
      LAYER metal3 ;
      RECT 951.125 0.000 951.195 0.070 ;
    END
  END w0_wd_in[496]
  PIN w0_wd_in[497]
    DIRECTION INPUT ;
    USE SIGNAL ;
    SHAPE ABUTMENT ;
    PORT
      LAYER metal3 ;
      RECT 951.265 0.000 951.335 0.070 ;
    END
  END w0_wd_in[497]
  PIN w0_wd_in[498]
    DIRECTION INPUT ;
    USE SIGNAL ;
    SHAPE ABUTMENT ;
    PORT
      LAYER metal3 ;
      RECT 951.405 0.000 951.475 0.070 ;
    END
  END w0_wd_in[498]
  PIN w0_wd_in[499]
    DIRECTION INPUT ;
    USE SIGNAL ;
    SHAPE ABUTMENT ;
    PORT
      LAYER metal3 ;
      RECT 951.545 0.000 951.615 0.070 ;
    END
  END w0_wd_in[499]
  PIN w0_wd_in[500]
    DIRECTION INPUT ;
    USE SIGNAL ;
    SHAPE ABUTMENT ;
    PORT
      LAYER metal3 ;
      RECT 951.685 0.000 951.755 0.070 ;
    END
  END w0_wd_in[500]
  PIN w0_wd_in[501]
    DIRECTION INPUT ;
    USE SIGNAL ;
    SHAPE ABUTMENT ;
    PORT
      LAYER metal3 ;
      RECT 951.825 0.000 951.895 0.070 ;
    END
  END w0_wd_in[501]
  PIN w0_wd_in[502]
    DIRECTION INPUT ;
    USE SIGNAL ;
    SHAPE ABUTMENT ;
    PORT
      LAYER metal3 ;
      RECT 951.965 0.000 952.035 0.070 ;
    END
  END w0_wd_in[502]
  PIN w0_wd_in[503]
    DIRECTION INPUT ;
    USE SIGNAL ;
    SHAPE ABUTMENT ;
    PORT
      LAYER metal3 ;
      RECT 952.105 0.000 952.175 0.070 ;
    END
  END w0_wd_in[503]
  PIN w0_wd_in[504]
    DIRECTION INPUT ;
    USE SIGNAL ;
    SHAPE ABUTMENT ;
    PORT
      LAYER metal3 ;
      RECT 952.245 0.000 952.315 0.070 ;
    END
  END w0_wd_in[504]
  PIN w0_wd_in[505]
    DIRECTION INPUT ;
    USE SIGNAL ;
    SHAPE ABUTMENT ;
    PORT
      LAYER metal3 ;
      RECT 952.385 0.000 952.455 0.070 ;
    END
  END w0_wd_in[505]
  PIN w0_wd_in[506]
    DIRECTION INPUT ;
    USE SIGNAL ;
    SHAPE ABUTMENT ;
    PORT
      LAYER metal3 ;
      RECT 952.525 0.000 952.595 0.070 ;
    END
  END w0_wd_in[506]
  PIN w0_wd_in[507]
    DIRECTION INPUT ;
    USE SIGNAL ;
    SHAPE ABUTMENT ;
    PORT
      LAYER metal3 ;
      RECT 952.665 0.000 952.735 0.070 ;
    END
  END w0_wd_in[507]
  PIN w0_wd_in[508]
    DIRECTION INPUT ;
    USE SIGNAL ;
    SHAPE ABUTMENT ;
    PORT
      LAYER metal3 ;
      RECT 952.805 0.000 952.875 0.070 ;
    END
  END w0_wd_in[508]
  PIN w0_wd_in[509]
    DIRECTION INPUT ;
    USE SIGNAL ;
    SHAPE ABUTMENT ;
    PORT
      LAYER metal3 ;
      RECT 952.945 0.000 953.015 0.070 ;
    END
  END w0_wd_in[509]
  PIN w0_wd_in[510]
    DIRECTION INPUT ;
    USE SIGNAL ;
    SHAPE ABUTMENT ;
    PORT
      LAYER metal3 ;
      RECT 953.085 0.000 953.155 0.070 ;
    END
  END w0_wd_in[510]
  PIN w0_wd_in[511]
    DIRECTION INPUT ;
    USE SIGNAL ;
    SHAPE ABUTMENT ;
    PORT
      LAYER metal3 ;
      RECT 953.225 0.000 953.295 0.070 ;
    END
  END w0_wd_in[511]
  PIN VSS
    DIRECTION INOUT ;
    USE GROUND ;
    PORT
      LAYER metal4 ;
      RECT 2.450 0.140 2.730 985.530 ;
      RECT 4.690 0.140 4.970 985.530 ;
      RECT 6.930 0.140 7.210 985.530 ;
      RECT 9.170 0.140 9.450 985.530 ;
      RECT 11.410 0.140 11.690 985.530 ;
      RECT 13.650 0.140 13.930 985.530 ;
      RECT 15.890 0.140 16.170 985.530 ;
      RECT 18.130 0.140 18.410 985.530 ;
      RECT 20.370 0.140 20.650 985.530 ;
      RECT 22.610 0.140 22.890 985.530 ;
      RECT 24.850 0.140 25.130 985.530 ;
      RECT 27.090 0.140 27.370 985.530 ;
      RECT 29.330 0.140 29.610 985.530 ;
      RECT 31.570 0.140 31.850 985.530 ;
      RECT 33.810 0.140 34.090 985.530 ;
      RECT 36.050 0.140 36.330 985.530 ;
      RECT 38.290 0.140 38.570 985.530 ;
      RECT 40.530 0.140 40.810 985.530 ;
      RECT 42.770 0.140 43.050 985.530 ;
      RECT 45.010 0.140 45.290 985.530 ;
      RECT 47.250 0.140 47.530 985.530 ;
      RECT 49.490 0.140 49.770 985.530 ;
      RECT 51.730 0.140 52.010 985.530 ;
      RECT 53.970 0.140 54.250 985.530 ;
      RECT 56.210 0.140 56.490 985.530 ;
      RECT 58.450 0.140 58.730 985.530 ;
      RECT 60.690 0.140 60.970 985.530 ;
      RECT 62.930 0.140 63.210 985.530 ;
      RECT 65.170 0.140 65.450 985.530 ;
      RECT 67.410 0.140 67.690 985.530 ;
      RECT 69.650 0.140 69.930 985.530 ;
      RECT 71.890 0.140 72.170 985.530 ;
      RECT 74.130 0.140 74.410 985.530 ;
      RECT 76.370 0.140 76.650 985.530 ;
      RECT 78.610 0.140 78.890 985.530 ;
      RECT 80.850 0.140 81.130 985.530 ;
      RECT 83.090 0.140 83.370 985.530 ;
      RECT 85.330 0.140 85.610 985.530 ;
      RECT 87.570 0.140 87.850 985.530 ;
      RECT 89.810 0.140 90.090 985.530 ;
      RECT 92.050 0.140 92.330 985.530 ;
      RECT 94.290 0.140 94.570 985.530 ;
      RECT 96.530 0.140 96.810 985.530 ;
      RECT 98.770 0.140 99.050 985.530 ;
      RECT 101.010 0.140 101.290 985.530 ;
      RECT 103.250 0.140 103.530 985.530 ;
      RECT 105.490 0.140 105.770 985.530 ;
      RECT 107.730 0.140 108.010 985.530 ;
      RECT 109.970 0.140 110.250 985.530 ;
      RECT 112.210 0.140 112.490 985.530 ;
      RECT 114.450 0.140 114.730 985.530 ;
      RECT 116.690 0.140 116.970 985.530 ;
      RECT 118.930 0.140 119.210 985.530 ;
      RECT 121.170 0.140 121.450 985.530 ;
      RECT 123.410 0.140 123.690 985.530 ;
      RECT 125.650 0.140 125.930 985.530 ;
      RECT 127.890 0.140 128.170 985.530 ;
      RECT 130.130 0.140 130.410 985.530 ;
      RECT 132.370 0.140 132.650 985.530 ;
      RECT 134.610 0.140 134.890 985.530 ;
      RECT 136.850 0.140 137.130 985.530 ;
      RECT 139.090 0.140 139.370 985.530 ;
      RECT 141.330 0.140 141.610 985.530 ;
      RECT 143.570 0.140 143.850 985.530 ;
      RECT 145.810 0.140 146.090 985.530 ;
      RECT 148.050 0.140 148.330 985.530 ;
      RECT 150.290 0.140 150.570 985.530 ;
      RECT 152.530 0.140 152.810 985.530 ;
      RECT 154.770 0.140 155.050 985.530 ;
      RECT 157.010 0.140 157.290 985.530 ;
      RECT 159.250 0.140 159.530 985.530 ;
      RECT 161.490 0.140 161.770 985.530 ;
      RECT 163.730 0.140 164.010 985.530 ;
      RECT 165.970 0.140 166.250 985.530 ;
      RECT 168.210 0.140 168.490 985.530 ;
      RECT 170.450 0.140 170.730 985.530 ;
      RECT 172.690 0.140 172.970 985.530 ;
      RECT 174.930 0.140 175.210 985.530 ;
      RECT 177.170 0.140 177.450 985.530 ;
      RECT 179.410 0.140 179.690 985.530 ;
      RECT 181.650 0.140 181.930 985.530 ;
      RECT 183.890 0.140 184.170 985.530 ;
      RECT 186.130 0.140 186.410 985.530 ;
      RECT 188.370 0.140 188.650 985.530 ;
      RECT 190.610 0.140 190.890 985.530 ;
      RECT 192.850 0.140 193.130 985.530 ;
      RECT 195.090 0.140 195.370 985.530 ;
      RECT 197.330 0.140 197.610 985.530 ;
      RECT 199.570 0.140 199.850 985.530 ;
      RECT 201.810 0.140 202.090 985.530 ;
      RECT 204.050 0.140 204.330 985.530 ;
      RECT 206.290 0.140 206.570 985.530 ;
      RECT 208.530 0.140 208.810 985.530 ;
      RECT 210.770 0.140 211.050 985.530 ;
      RECT 213.010 0.140 213.290 985.530 ;
      RECT 215.250 0.140 215.530 985.530 ;
      RECT 217.490 0.140 217.770 985.530 ;
      RECT 219.730 0.140 220.010 985.530 ;
      RECT 221.970 0.140 222.250 985.530 ;
      RECT 224.210 0.140 224.490 985.530 ;
      RECT 226.450 0.140 226.730 985.530 ;
      RECT 228.690 0.140 228.970 985.530 ;
      RECT 230.930 0.140 231.210 985.530 ;
      RECT 233.170 0.140 233.450 985.530 ;
      RECT 235.410 0.140 235.690 985.530 ;
      RECT 237.650 0.140 237.930 985.530 ;
      RECT 239.890 0.140 240.170 985.530 ;
      RECT 242.130 0.140 242.410 985.530 ;
      RECT 244.370 0.140 244.650 985.530 ;
      RECT 246.610 0.140 246.890 985.530 ;
      RECT 248.850 0.140 249.130 985.530 ;
      RECT 251.090 0.140 251.370 985.530 ;
      RECT 253.330 0.140 253.610 985.530 ;
      RECT 255.570 0.140 255.850 985.530 ;
      RECT 257.810 0.140 258.090 985.530 ;
      RECT 260.050 0.140 260.330 985.530 ;
      RECT 262.290 0.140 262.570 985.530 ;
      RECT 264.530 0.140 264.810 985.530 ;
      RECT 266.770 0.140 267.050 985.530 ;
      RECT 269.010 0.140 269.290 985.530 ;
      RECT 271.250 0.140 271.530 985.530 ;
      RECT 273.490 0.140 273.770 985.530 ;
      RECT 275.730 0.140 276.010 985.530 ;
      RECT 277.970 0.140 278.250 985.530 ;
      RECT 280.210 0.140 280.490 985.530 ;
      RECT 282.450 0.140 282.730 985.530 ;
      RECT 284.690 0.140 284.970 985.530 ;
      RECT 286.930 0.140 287.210 985.530 ;
      RECT 289.170 0.140 289.450 985.530 ;
      RECT 291.410 0.140 291.690 985.530 ;
      RECT 293.650 0.140 293.930 985.530 ;
      RECT 295.890 0.140 296.170 985.530 ;
      RECT 298.130 0.140 298.410 985.530 ;
      RECT 300.370 0.140 300.650 985.530 ;
      RECT 302.610 0.140 302.890 985.530 ;
      RECT 304.850 0.140 305.130 985.530 ;
      RECT 307.090 0.140 307.370 985.530 ;
      RECT 309.330 0.140 309.610 985.530 ;
      RECT 311.570 0.140 311.850 985.530 ;
      RECT 313.810 0.140 314.090 985.530 ;
      RECT 316.050 0.140 316.330 985.530 ;
      RECT 318.290 0.140 318.570 985.530 ;
      RECT 320.530 0.140 320.810 985.530 ;
      RECT 322.770 0.140 323.050 985.530 ;
      RECT 325.010 0.140 325.290 985.530 ;
      RECT 327.250 0.140 327.530 985.530 ;
      RECT 329.490 0.140 329.770 985.530 ;
      RECT 331.730 0.140 332.010 985.530 ;
      RECT 333.970 0.140 334.250 985.530 ;
      RECT 336.210 0.140 336.490 985.530 ;
      RECT 338.450 0.140 338.730 985.530 ;
      RECT 340.690 0.140 340.970 985.530 ;
      RECT 342.930 0.140 343.210 985.530 ;
      RECT 345.170 0.140 345.450 985.530 ;
      RECT 347.410 0.140 347.690 985.530 ;
      RECT 349.650 0.140 349.930 985.530 ;
      RECT 351.890 0.140 352.170 985.530 ;
      RECT 354.130 0.140 354.410 985.530 ;
      RECT 356.370 0.140 356.650 985.530 ;
      RECT 358.610 0.140 358.890 985.530 ;
      RECT 360.850 0.140 361.130 985.530 ;
      RECT 363.090 0.140 363.370 985.530 ;
      RECT 365.330 0.140 365.610 985.530 ;
      RECT 367.570 0.140 367.850 985.530 ;
      RECT 369.810 0.140 370.090 985.530 ;
      RECT 372.050 0.140 372.330 985.530 ;
      RECT 374.290 0.140 374.570 985.530 ;
      RECT 376.530 0.140 376.810 985.530 ;
      RECT 378.770 0.140 379.050 985.530 ;
      RECT 381.010 0.140 381.290 985.530 ;
      RECT 383.250 0.140 383.530 985.530 ;
      RECT 385.490 0.140 385.770 985.530 ;
      RECT 387.730 0.140 388.010 985.530 ;
      RECT 389.970 0.140 390.250 985.530 ;
      RECT 392.210 0.140 392.490 985.530 ;
      RECT 394.450 0.140 394.730 985.530 ;
      RECT 396.690 0.140 396.970 985.530 ;
      RECT 398.930 0.140 399.210 985.530 ;
      RECT 401.170 0.140 401.450 985.530 ;
      RECT 403.410 0.140 403.690 985.530 ;
      RECT 405.650 0.140 405.930 985.530 ;
      RECT 407.890 0.140 408.170 985.530 ;
      RECT 410.130 0.140 410.410 985.530 ;
      RECT 412.370 0.140 412.650 985.530 ;
      RECT 414.610 0.140 414.890 985.530 ;
      RECT 416.850 0.140 417.130 985.530 ;
      RECT 419.090 0.140 419.370 985.530 ;
      RECT 421.330 0.140 421.610 985.530 ;
      RECT 423.570 0.140 423.850 985.530 ;
      RECT 425.810 0.140 426.090 985.530 ;
      RECT 428.050 0.140 428.330 985.530 ;
      RECT 430.290 0.140 430.570 985.530 ;
      RECT 432.530 0.140 432.810 985.530 ;
      RECT 434.770 0.140 435.050 985.530 ;
      RECT 437.010 0.140 437.290 985.530 ;
      RECT 439.250 0.140 439.530 985.530 ;
      RECT 441.490 0.140 441.770 985.530 ;
      RECT 443.730 0.140 444.010 985.530 ;
      RECT 445.970 0.140 446.250 985.530 ;
      RECT 448.210 0.140 448.490 985.530 ;
      RECT 450.450 0.140 450.730 985.530 ;
      RECT 452.690 0.140 452.970 985.530 ;
      RECT 454.930 0.140 455.210 985.530 ;
      RECT 457.170 0.140 457.450 985.530 ;
      RECT 459.410 0.140 459.690 985.530 ;
      RECT 461.650 0.140 461.930 985.530 ;
      RECT 463.890 0.140 464.170 985.530 ;
      RECT 466.130 0.140 466.410 985.530 ;
      RECT 468.370 0.140 468.650 985.530 ;
      RECT 470.610 0.140 470.890 985.530 ;
      RECT 472.850 0.140 473.130 985.530 ;
      RECT 475.090 0.140 475.370 985.530 ;
      RECT 477.330 0.140 477.610 985.530 ;
      RECT 479.570 0.140 479.850 985.530 ;
      RECT 481.810 0.140 482.090 985.530 ;
      RECT 484.050 0.140 484.330 985.530 ;
      RECT 486.290 0.140 486.570 985.530 ;
      RECT 488.530 0.140 488.810 985.530 ;
      RECT 490.770 0.140 491.050 985.530 ;
      RECT 493.010 0.140 493.290 985.530 ;
      RECT 495.250 0.140 495.530 985.530 ;
      RECT 497.490 0.140 497.770 985.530 ;
      RECT 499.730 0.140 500.010 985.530 ;
      RECT 501.970 0.140 502.250 985.530 ;
      RECT 504.210 0.140 504.490 985.530 ;
      RECT 506.450 0.140 506.730 985.530 ;
      RECT 508.690 0.140 508.970 985.530 ;
      RECT 510.930 0.140 511.210 985.530 ;
      RECT 513.170 0.140 513.450 985.530 ;
      RECT 515.410 0.140 515.690 985.530 ;
      RECT 517.650 0.140 517.930 985.530 ;
      RECT 519.890 0.140 520.170 985.530 ;
      RECT 522.130 0.140 522.410 985.530 ;
      RECT 524.370 0.140 524.650 985.530 ;
      RECT 526.610 0.140 526.890 985.530 ;
      RECT 528.850 0.140 529.130 985.530 ;
      RECT 531.090 0.140 531.370 985.530 ;
      RECT 533.330 0.140 533.610 985.530 ;
      RECT 535.570 0.140 535.850 985.530 ;
      RECT 537.810 0.140 538.090 985.530 ;
      RECT 540.050 0.140 540.330 985.530 ;
      RECT 542.290 0.140 542.570 985.530 ;
      RECT 544.530 0.140 544.810 985.530 ;
      RECT 546.770 0.140 547.050 985.530 ;
      RECT 549.010 0.140 549.290 985.530 ;
      RECT 551.250 0.140 551.530 985.530 ;
      RECT 553.490 0.140 553.770 985.530 ;
      RECT 555.730 0.140 556.010 985.530 ;
      RECT 557.970 0.140 558.250 985.530 ;
      RECT 560.210 0.140 560.490 985.530 ;
      RECT 562.450 0.140 562.730 985.530 ;
      RECT 564.690 0.140 564.970 985.530 ;
      RECT 566.930 0.140 567.210 985.530 ;
      RECT 569.170 0.140 569.450 985.530 ;
      RECT 571.410 0.140 571.690 985.530 ;
      RECT 573.650 0.140 573.930 985.530 ;
      RECT 575.890 0.140 576.170 985.530 ;
      RECT 578.130 0.140 578.410 985.530 ;
      RECT 580.370 0.140 580.650 985.530 ;
      RECT 582.610 0.140 582.890 985.530 ;
      RECT 584.850 0.140 585.130 985.530 ;
      RECT 587.090 0.140 587.370 985.530 ;
      RECT 589.330 0.140 589.610 985.530 ;
      RECT 591.570 0.140 591.850 985.530 ;
      RECT 593.810 0.140 594.090 985.530 ;
      RECT 596.050 0.140 596.330 985.530 ;
      RECT 598.290 0.140 598.570 985.530 ;
      RECT 600.530 0.140 600.810 985.530 ;
      RECT 602.770 0.140 603.050 985.530 ;
      RECT 605.010 0.140 605.290 985.530 ;
      RECT 607.250 0.140 607.530 985.530 ;
      RECT 609.490 0.140 609.770 985.530 ;
      RECT 611.730 0.140 612.010 985.530 ;
      RECT 613.970 0.140 614.250 985.530 ;
      RECT 616.210 0.140 616.490 985.530 ;
      RECT 618.450 0.140 618.730 985.530 ;
      RECT 620.690 0.140 620.970 985.530 ;
      RECT 622.930 0.140 623.210 985.530 ;
      RECT 625.170 0.140 625.450 985.530 ;
      RECT 627.410 0.140 627.690 985.530 ;
      RECT 629.650 0.140 629.930 985.530 ;
      RECT 631.890 0.140 632.170 985.530 ;
      RECT 634.130 0.140 634.410 985.530 ;
      RECT 636.370 0.140 636.650 985.530 ;
      RECT 638.610 0.140 638.890 985.530 ;
      RECT 640.850 0.140 641.130 985.530 ;
      RECT 643.090 0.140 643.370 985.530 ;
      RECT 645.330 0.140 645.610 985.530 ;
      RECT 647.570 0.140 647.850 985.530 ;
      RECT 649.810 0.140 650.090 985.530 ;
      RECT 652.050 0.140 652.330 985.530 ;
      RECT 654.290 0.140 654.570 985.530 ;
      RECT 656.530 0.140 656.810 985.530 ;
      RECT 658.770 0.140 659.050 985.530 ;
      RECT 661.010 0.140 661.290 985.530 ;
      RECT 663.250 0.140 663.530 985.530 ;
      RECT 665.490 0.140 665.770 985.530 ;
      RECT 667.730 0.140 668.010 985.530 ;
      RECT 669.970 0.140 670.250 985.530 ;
      RECT 672.210 0.140 672.490 985.530 ;
      RECT 674.450 0.140 674.730 985.530 ;
      RECT 676.690 0.140 676.970 985.530 ;
      RECT 678.930 0.140 679.210 985.530 ;
      RECT 681.170 0.140 681.450 985.530 ;
      RECT 683.410 0.140 683.690 985.530 ;
      RECT 685.650 0.140 685.930 985.530 ;
      RECT 687.890 0.140 688.170 985.530 ;
      RECT 690.130 0.140 690.410 985.530 ;
      RECT 692.370 0.140 692.650 985.530 ;
      RECT 694.610 0.140 694.890 985.530 ;
      RECT 696.850 0.140 697.130 985.530 ;
      RECT 699.090 0.140 699.370 985.530 ;
      RECT 701.330 0.140 701.610 985.530 ;
      RECT 703.570 0.140 703.850 985.530 ;
      RECT 705.810 0.140 706.090 985.530 ;
      RECT 708.050 0.140 708.330 985.530 ;
      RECT 710.290 0.140 710.570 985.530 ;
      RECT 712.530 0.140 712.810 985.530 ;
      RECT 714.770 0.140 715.050 985.530 ;
      RECT 717.010 0.140 717.290 985.530 ;
      RECT 719.250 0.140 719.530 985.530 ;
      RECT 721.490 0.140 721.770 985.530 ;
      RECT 723.730 0.140 724.010 985.530 ;
      RECT 725.970 0.140 726.250 985.530 ;
      RECT 728.210 0.140 728.490 985.530 ;
      RECT 730.450 0.140 730.730 985.530 ;
      RECT 732.690 0.140 732.970 985.530 ;
      RECT 734.930 0.140 735.210 985.530 ;
      RECT 737.170 0.140 737.450 985.530 ;
      RECT 739.410 0.140 739.690 985.530 ;
      RECT 741.650 0.140 741.930 985.530 ;
      RECT 743.890 0.140 744.170 985.530 ;
      RECT 746.130 0.140 746.410 985.530 ;
      RECT 748.370 0.140 748.650 985.530 ;
      RECT 750.610 0.140 750.890 985.530 ;
      RECT 752.850 0.140 753.130 985.530 ;
      RECT 755.090 0.140 755.370 985.530 ;
      RECT 757.330 0.140 757.610 985.530 ;
      RECT 759.570 0.140 759.850 985.530 ;
      RECT 761.810 0.140 762.090 985.530 ;
      RECT 764.050 0.140 764.330 985.530 ;
      RECT 766.290 0.140 766.570 985.530 ;
      RECT 768.530 0.140 768.810 985.530 ;
      RECT 770.770 0.140 771.050 985.530 ;
      RECT 773.010 0.140 773.290 985.530 ;
      RECT 775.250 0.140 775.530 985.530 ;
      RECT 777.490 0.140 777.770 985.530 ;
      RECT 779.730 0.140 780.010 985.530 ;
      RECT 781.970 0.140 782.250 985.530 ;
      RECT 784.210 0.140 784.490 985.530 ;
      RECT 786.450 0.140 786.730 985.530 ;
      RECT 788.690 0.140 788.970 985.530 ;
      RECT 790.930 0.140 791.210 985.530 ;
      RECT 793.170 0.140 793.450 985.530 ;
      RECT 795.410 0.140 795.690 985.530 ;
      RECT 797.650 0.140 797.930 985.530 ;
      RECT 799.890 0.140 800.170 985.530 ;
      RECT 802.130 0.140 802.410 985.530 ;
      RECT 804.370 0.140 804.650 985.530 ;
      RECT 806.610 0.140 806.890 985.530 ;
      RECT 808.850 0.140 809.130 985.530 ;
      RECT 811.090 0.140 811.370 985.530 ;
      RECT 813.330 0.140 813.610 985.530 ;
      RECT 815.570 0.140 815.850 985.530 ;
      RECT 817.810 0.140 818.090 985.530 ;
      RECT 820.050 0.140 820.330 985.530 ;
      RECT 822.290 0.140 822.570 985.530 ;
      RECT 824.530 0.140 824.810 985.530 ;
      RECT 826.770 0.140 827.050 985.530 ;
      RECT 829.010 0.140 829.290 985.530 ;
      RECT 831.250 0.140 831.530 985.530 ;
      RECT 833.490 0.140 833.770 985.530 ;
      RECT 835.730 0.140 836.010 985.530 ;
      RECT 837.970 0.140 838.250 985.530 ;
      RECT 840.210 0.140 840.490 985.530 ;
      RECT 842.450 0.140 842.730 985.530 ;
      RECT 844.690 0.140 844.970 985.530 ;
      RECT 846.930 0.140 847.210 985.530 ;
      RECT 849.170 0.140 849.450 985.530 ;
      RECT 851.410 0.140 851.690 985.530 ;
      RECT 853.650 0.140 853.930 985.530 ;
      RECT 855.890 0.140 856.170 985.530 ;
      RECT 858.130 0.140 858.410 985.530 ;
      RECT 860.370 0.140 860.650 985.530 ;
      RECT 862.610 0.140 862.890 985.530 ;
      RECT 864.850 0.140 865.130 985.530 ;
      RECT 867.090 0.140 867.370 985.530 ;
      RECT 869.330 0.140 869.610 985.530 ;
      RECT 871.570 0.140 871.850 985.530 ;
      RECT 873.810 0.140 874.090 985.530 ;
      RECT 876.050 0.140 876.330 985.530 ;
      RECT 878.290 0.140 878.570 985.530 ;
      RECT 880.530 0.140 880.810 985.530 ;
      RECT 882.770 0.140 883.050 985.530 ;
      RECT 885.010 0.140 885.290 985.530 ;
      RECT 887.250 0.140 887.530 985.530 ;
      RECT 889.490 0.140 889.770 985.530 ;
      RECT 891.730 0.140 892.010 985.530 ;
      RECT 893.970 0.140 894.250 985.530 ;
      RECT 896.210 0.140 896.490 985.530 ;
      RECT 898.450 0.140 898.730 985.530 ;
      RECT 900.690 0.140 900.970 985.530 ;
      RECT 902.930 0.140 903.210 985.530 ;
      RECT 905.170 0.140 905.450 985.530 ;
      RECT 907.410 0.140 907.690 985.530 ;
      RECT 909.650 0.140 909.930 985.530 ;
      RECT 911.890 0.140 912.170 985.530 ;
      RECT 914.130 0.140 914.410 985.530 ;
      RECT 916.370 0.140 916.650 985.530 ;
      RECT 918.610 0.140 918.890 985.530 ;
      RECT 920.850 0.140 921.130 985.530 ;
      RECT 923.090 0.140 923.370 985.530 ;
      RECT 925.330 0.140 925.610 985.530 ;
      RECT 927.570 0.140 927.850 985.530 ;
      RECT 929.810 0.140 930.090 985.530 ;
      RECT 932.050 0.140 932.330 985.530 ;
      RECT 934.290 0.140 934.570 985.530 ;
      RECT 936.530 0.140 936.810 985.530 ;
      RECT 938.770 0.140 939.050 985.530 ;
      RECT 941.010 0.140 941.290 985.530 ;
      RECT 943.250 0.140 943.530 985.530 ;
      RECT 945.490 0.140 945.770 985.530 ;
      RECT 947.730 0.140 948.010 985.530 ;
      RECT 949.970 0.140 950.250 985.530 ;
      RECT 952.210 0.140 952.490 985.530 ;
      RECT 954.450 0.140 954.730 985.530 ;
      RECT 956.690 0.140 956.970 985.530 ;
      RECT 958.930 0.140 959.210 985.530 ;
      RECT 961.170 0.140 961.450 985.530 ;
      RECT 963.410 0.140 963.690 985.530 ;
      RECT 965.650 0.140 965.930 985.530 ;
      RECT 967.890 0.140 968.170 985.530 ;
      RECT 970.130 0.140 970.410 985.530 ;
      RECT 972.370 0.140 972.650 985.530 ;
      RECT 974.610 0.140 974.890 985.530 ;
      RECT 976.850 0.140 977.130 985.530 ;
      RECT 979.090 0.140 979.370 985.530 ;
      RECT 981.330 0.140 981.610 985.530 ;
      RECT 983.570 0.140 983.850 985.530 ;
      RECT 985.810 0.140 986.090 985.530 ;
      RECT 988.050 0.140 988.330 985.530 ;
      RECT 990.290 0.140 990.570 985.530 ;
      RECT 992.530 0.140 992.810 985.530 ;
      RECT 994.770 0.140 995.050 985.530 ;
      RECT 997.010 0.140 997.290 985.530 ;
      RECT 999.250 0.140 999.530 985.530 ;
      RECT 1001.490 0.140 1001.770 985.530 ;
      RECT 1003.730 0.140 1004.010 985.530 ;
      RECT 1005.970 0.140 1006.250 985.530 ;
      RECT 1008.210 0.140 1008.490 985.530 ;
      RECT 1010.450 0.140 1010.730 985.530 ;
      RECT 1012.690 0.140 1012.970 985.530 ;
      RECT 1014.930 0.140 1015.210 985.530 ;
      RECT 1017.170 0.140 1017.450 985.530 ;
      RECT 1019.410 0.140 1019.690 985.530 ;
      RECT 1021.650 0.140 1021.930 985.530 ;
      RECT 1023.890 0.140 1024.170 985.530 ;
      RECT 1026.130 0.140 1026.410 985.530 ;
      RECT 1028.370 0.140 1028.650 985.530 ;
      RECT 1030.610 0.140 1030.890 985.530 ;
      RECT 1032.850 0.140 1033.130 985.530 ;
      RECT 1035.090 0.140 1035.370 985.530 ;
      RECT 1037.330 0.140 1037.610 985.530 ;
      RECT 1039.570 0.140 1039.850 985.530 ;
      RECT 1041.810 0.140 1042.090 985.530 ;
      RECT 1044.050 0.140 1044.330 985.530 ;
      RECT 1046.290 0.140 1046.570 985.530 ;
      RECT 1048.530 0.140 1048.810 985.530 ;
      RECT 1050.770 0.140 1051.050 985.530 ;
      RECT 1053.010 0.140 1053.290 985.530 ;
      RECT 1055.250 0.140 1055.530 985.530 ;
      RECT 1057.490 0.140 1057.770 985.530 ;
      RECT 1059.730 0.140 1060.010 985.530 ;
      RECT 1061.970 0.140 1062.250 985.530 ;
      RECT 1064.210 0.140 1064.490 985.530 ;
      RECT 1066.450 0.140 1066.730 985.530 ;
      RECT 1068.690 0.140 1068.970 985.530 ;
      RECT 1070.930 0.140 1071.210 985.530 ;
      RECT 1073.170 0.140 1073.450 985.530 ;
      RECT 1075.410 0.140 1075.690 985.530 ;
      RECT 1077.650 0.140 1077.930 985.530 ;
      RECT 1079.890 0.140 1080.170 985.530 ;
      RECT 1082.130 0.140 1082.410 985.530 ;
      RECT 1084.370 0.140 1084.650 985.530 ;
      RECT 1086.610 0.140 1086.890 985.530 ;
      RECT 1088.850 0.140 1089.130 985.530 ;
      RECT 1091.090 0.140 1091.370 985.530 ;
      RECT 1093.330 0.140 1093.610 985.530 ;
      RECT 1095.570 0.140 1095.850 985.530 ;
      RECT 1097.810 0.140 1098.090 985.530 ;
      RECT 1100.050 0.140 1100.330 985.530 ;
      RECT 1102.290 0.140 1102.570 985.530 ;
      RECT 1104.530 0.140 1104.810 985.530 ;
      RECT 1106.770 0.140 1107.050 985.530 ;
      RECT 1109.010 0.140 1109.290 985.530 ;
      RECT 1111.250 0.140 1111.530 985.530 ;
      RECT 1113.490 0.140 1113.770 985.530 ;
      RECT 1115.730 0.140 1116.010 985.530 ;
      RECT 1117.970 0.140 1118.250 985.530 ;
      RECT 1120.210 0.140 1120.490 985.530 ;
      RECT 1122.450 0.140 1122.730 985.530 ;
      RECT 1124.690 0.140 1124.970 985.530 ;
      RECT 1126.930 0.140 1127.210 985.530 ;
      RECT 1129.170 0.140 1129.450 985.530 ;
      RECT 1131.410 0.140 1131.690 985.530 ;
      RECT 1133.650 0.140 1133.930 985.530 ;
      RECT 1135.890 0.140 1136.170 985.530 ;
      RECT 1138.130 0.140 1138.410 985.530 ;
      RECT 1140.370 0.140 1140.650 985.530 ;
      RECT 1142.610 0.140 1142.890 985.530 ;
      RECT 1144.850 0.140 1145.130 985.530 ;
      RECT 1147.090 0.140 1147.370 985.530 ;
      RECT 1149.330 0.140 1149.610 985.530 ;
      RECT 1151.570 0.140 1151.850 985.530 ;
      RECT 1153.810 0.140 1154.090 985.530 ;
      RECT 1156.050 0.140 1156.330 985.530 ;
      RECT 1158.290 0.140 1158.570 985.530 ;
      RECT 1160.530 0.140 1160.810 985.530 ;
      RECT 1162.770 0.140 1163.050 985.530 ;
      RECT 1165.010 0.140 1165.290 985.530 ;
      RECT 1167.250 0.140 1167.530 985.530 ;
      RECT 1169.490 0.140 1169.770 985.530 ;
      RECT 1171.730 0.140 1172.010 985.530 ;
      RECT 1173.970 0.140 1174.250 985.530 ;
      RECT 1176.210 0.140 1176.490 985.530 ;
      RECT 1178.450 0.140 1178.730 985.530 ;
      RECT 1180.690 0.140 1180.970 985.530 ;
      RECT 1182.930 0.140 1183.210 985.530 ;
      RECT 1185.170 0.140 1185.450 985.530 ;
      RECT 1187.410 0.140 1187.690 985.530 ;
      RECT 1189.650 0.140 1189.930 985.530 ;
      RECT 1191.890 0.140 1192.170 985.530 ;
      RECT 1194.130 0.140 1194.410 985.530 ;
      RECT 1196.370 0.140 1196.650 985.530 ;
      RECT 1198.610 0.140 1198.890 985.530 ;
      RECT 1200.850 0.140 1201.130 985.530 ;
      RECT 1203.090 0.140 1203.370 985.530 ;
      RECT 1205.330 0.140 1205.610 985.530 ;
      RECT 1207.570 0.140 1207.850 985.530 ;
      RECT 1209.810 0.140 1210.090 985.530 ;
      RECT 1212.050 0.140 1212.330 985.530 ;
      RECT 1214.290 0.140 1214.570 985.530 ;
      RECT 1216.530 0.140 1216.810 985.530 ;
      RECT 1218.770 0.140 1219.050 985.530 ;
      RECT 1221.010 0.140 1221.290 985.530 ;
      RECT 1223.250 0.140 1223.530 985.530 ;
      RECT 1225.490 0.140 1225.770 985.530 ;
      RECT 1227.730 0.140 1228.010 985.530 ;
      RECT 1229.970 0.140 1230.250 985.530 ;
      RECT 1232.210 0.140 1232.490 985.530 ;
      RECT 1234.450 0.140 1234.730 985.530 ;
      RECT 1236.690 0.140 1236.970 985.530 ;
      RECT 1238.930 0.140 1239.210 985.530 ;
      RECT 1241.170 0.140 1241.450 985.530 ;
      RECT 1243.410 0.140 1243.690 985.530 ;
      RECT 1245.650 0.140 1245.930 985.530 ;
      RECT 1247.890 0.140 1248.170 985.530 ;
      RECT 1250.130 0.140 1250.410 985.530 ;
      RECT 1252.370 0.140 1252.650 985.530 ;
      RECT 1254.610 0.140 1254.890 985.530 ;
      RECT 1256.850 0.140 1257.130 985.530 ;
      RECT 1259.090 0.140 1259.370 985.530 ;
      RECT 1261.330 0.140 1261.610 985.530 ;
      RECT 1263.570 0.140 1263.850 985.530 ;
      RECT 1265.810 0.140 1266.090 985.530 ;
      RECT 1268.050 0.140 1268.330 985.530 ;
      RECT 1270.290 0.140 1270.570 985.530 ;
      RECT 1272.530 0.140 1272.810 985.530 ;
      RECT 1274.770 0.140 1275.050 985.530 ;
      RECT 1277.010 0.140 1277.290 985.530 ;
      RECT 1279.250 0.140 1279.530 985.530 ;
      RECT 1281.490 0.140 1281.770 985.530 ;
      RECT 1283.730 0.140 1284.010 985.530 ;
      RECT 1285.970 0.140 1286.250 985.530 ;
      RECT 1288.210 0.140 1288.490 985.530 ;
      RECT 1290.450 0.140 1290.730 985.530 ;
      RECT 1292.690 0.140 1292.970 985.530 ;
      RECT 1294.930 0.140 1295.210 985.530 ;
      RECT 1297.170 0.140 1297.450 985.530 ;
      RECT 1299.410 0.140 1299.690 985.530 ;
      RECT 1301.650 0.140 1301.930 985.530 ;
      RECT 1303.890 0.140 1304.170 985.530 ;
      RECT 1306.130 0.140 1306.410 985.530 ;
      RECT 1308.370 0.140 1308.650 985.530 ;
      RECT 1310.610 0.140 1310.890 985.530 ;
      RECT 1312.850 0.140 1313.130 985.530 ;
      RECT 1315.090 0.140 1315.370 985.530 ;
      RECT 1317.330 0.140 1317.610 985.530 ;
      RECT 1319.570 0.140 1319.850 985.530 ;
      RECT 1321.810 0.140 1322.090 985.530 ;
      RECT 1324.050 0.140 1324.330 985.530 ;
      RECT 1326.290 0.140 1326.570 985.530 ;
      RECT 1328.530 0.140 1328.810 985.530 ;
      RECT 1330.770 0.140 1331.050 985.530 ;
      RECT 1333.010 0.140 1333.290 985.530 ;
      RECT 1335.250 0.140 1335.530 985.530 ;
      RECT 1337.490 0.140 1337.770 985.530 ;
      RECT 1339.730 0.140 1340.010 985.530 ;
      RECT 1341.970 0.140 1342.250 985.530 ;
      RECT 1344.210 0.140 1344.490 985.530 ;
      RECT 1346.450 0.140 1346.730 985.530 ;
      RECT 1348.690 0.140 1348.970 985.530 ;
      RECT 1350.930 0.140 1351.210 985.530 ;
      RECT 1353.170 0.140 1353.450 985.530 ;
      RECT 1355.410 0.140 1355.690 985.530 ;
      RECT 1357.650 0.140 1357.930 985.530 ;
      RECT 1359.890 0.140 1360.170 985.530 ;
      RECT 1362.130 0.140 1362.410 985.530 ;
      RECT 1364.370 0.140 1364.650 985.530 ;
      RECT 1366.610 0.140 1366.890 985.530 ;
      RECT 1368.850 0.140 1369.130 985.530 ;
      RECT 1371.090 0.140 1371.370 985.530 ;
      RECT 1373.330 0.140 1373.610 985.530 ;
      RECT 1375.570 0.140 1375.850 985.530 ;
      RECT 1377.810 0.140 1378.090 985.530 ;
      RECT 1380.050 0.140 1380.330 985.530 ;
      RECT 1382.290 0.140 1382.570 985.530 ;
      RECT 1384.530 0.140 1384.810 985.530 ;
      RECT 1386.770 0.140 1387.050 985.530 ;
      RECT 1389.010 0.140 1389.290 985.530 ;
      RECT 1391.250 0.140 1391.530 985.530 ;
      RECT 1393.490 0.140 1393.770 985.530 ;
      RECT 1395.730 0.140 1396.010 985.530 ;
      RECT 1397.970 0.140 1398.250 985.530 ;
      RECT 1400.210 0.140 1400.490 985.530 ;
      RECT 1402.450 0.140 1402.730 985.530 ;
      RECT 1404.690 0.140 1404.970 985.530 ;
      RECT 1406.930 0.140 1407.210 985.530 ;
      RECT 1409.170 0.140 1409.450 985.530 ;
      RECT 1411.410 0.140 1411.690 985.530 ;
      RECT 1413.650 0.140 1413.930 985.530 ;
      RECT 1415.890 0.140 1416.170 985.530 ;
      RECT 1418.130 0.140 1418.410 985.530 ;
      RECT 1420.370 0.140 1420.650 985.530 ;
      RECT 1422.610 0.140 1422.890 985.530 ;
      RECT 1424.850 0.140 1425.130 985.530 ;
      RECT 1427.090 0.140 1427.370 985.530 ;
      RECT 1429.330 0.140 1429.610 985.530 ;
      RECT 1431.570 0.140 1431.850 985.530 ;
      RECT 1433.810 0.140 1434.090 985.530 ;
      RECT 1436.050 0.140 1436.330 985.530 ;
      RECT 1438.290 0.140 1438.570 985.530 ;
      RECT 1440.530 0.140 1440.810 985.530 ;
      RECT 1442.770 0.140 1443.050 985.530 ;
      RECT 1445.010 0.140 1445.290 985.530 ;
      RECT 1447.250 0.140 1447.530 985.530 ;
      RECT 1449.490 0.140 1449.770 985.530 ;
      RECT 1451.730 0.140 1452.010 985.530 ;
      RECT 1453.970 0.140 1454.250 985.530 ;
      RECT 1456.210 0.140 1456.490 985.530 ;
      RECT 1458.450 0.140 1458.730 985.530 ;
      RECT 1460.690 0.140 1460.970 985.530 ;
      RECT 1462.930 0.140 1463.210 985.530 ;
      RECT 1465.170 0.140 1465.450 985.530 ;
      RECT 1467.410 0.140 1467.690 985.530 ;
      RECT 1469.650 0.140 1469.930 985.530 ;
      RECT 1471.890 0.140 1472.170 985.530 ;
      RECT 1474.130 0.140 1474.410 985.530 ;
      RECT 1476.370 0.140 1476.650 985.530 ;
      RECT 1478.610 0.140 1478.890 985.530 ;
      RECT 1480.850 0.140 1481.130 985.530 ;
      RECT 1483.090 0.140 1483.370 985.530 ;
      RECT 1485.330 0.140 1485.610 985.530 ;
      RECT 1487.570 0.140 1487.850 985.530 ;
      RECT 1489.810 0.140 1490.090 985.530 ;
      RECT 1492.050 0.140 1492.330 985.530 ;
      RECT 1494.290 0.140 1494.570 985.530 ;
      RECT 1496.530 0.140 1496.810 985.530 ;
      RECT 1498.770 0.140 1499.050 985.530 ;
      RECT 1501.010 0.140 1501.290 985.530 ;
      RECT 1503.250 0.140 1503.530 985.530 ;
      RECT 1505.490 0.140 1505.770 985.530 ;
      RECT 1507.730 0.140 1508.010 985.530 ;
      RECT 1509.970 0.140 1510.250 985.530 ;
      RECT 1512.210 0.140 1512.490 985.530 ;
      RECT 1514.450 0.140 1514.730 985.530 ;
      RECT 1516.690 0.140 1516.970 985.530 ;
      RECT 1518.930 0.140 1519.210 985.530 ;
      RECT 1521.170 0.140 1521.450 985.530 ;
      RECT 1523.410 0.140 1523.690 985.530 ;
      RECT 1525.650 0.140 1525.930 985.530 ;
      RECT 1527.890 0.140 1528.170 985.530 ;
      RECT 1530.130 0.140 1530.410 985.530 ;
      RECT 1532.370 0.140 1532.650 985.530 ;
      RECT 1534.610 0.140 1534.890 985.530 ;
      RECT 1536.850 0.140 1537.130 985.530 ;
      RECT 1539.090 0.140 1539.370 985.530 ;
      RECT 1541.330 0.140 1541.610 985.530 ;
      RECT 1543.570 0.140 1543.850 985.530 ;
      RECT 1545.810 0.140 1546.090 985.530 ;
      RECT 1548.050 0.140 1548.330 985.530 ;
      RECT 1550.290 0.140 1550.570 985.530 ;
      RECT 1552.530 0.140 1552.810 985.530 ;
      RECT 1554.770 0.140 1555.050 985.530 ;
      RECT 1557.010 0.140 1557.290 985.530 ;
      RECT 1559.250 0.140 1559.530 985.530 ;
      RECT 1561.490 0.140 1561.770 985.530 ;
      RECT 1563.730 0.140 1564.010 985.530 ;
      RECT 1565.970 0.140 1566.250 985.530 ;
      RECT 1568.210 0.140 1568.490 985.530 ;
      RECT 1570.450 0.140 1570.730 985.530 ;
      RECT 1572.690 0.140 1572.970 985.530 ;
      RECT 1574.930 0.140 1575.210 985.530 ;
      RECT 1577.170 0.140 1577.450 985.530 ;
      RECT 1579.410 0.140 1579.690 985.530 ;
      RECT 1581.650 0.140 1581.930 985.530 ;
      RECT 1583.890 0.140 1584.170 985.530 ;
      RECT 1586.130 0.140 1586.410 985.530 ;
      RECT 1588.370 0.140 1588.650 985.530 ;
      RECT 1590.610 0.140 1590.890 985.530 ;
      RECT 1592.850 0.140 1593.130 985.530 ;
      RECT 1595.090 0.140 1595.370 985.530 ;
      RECT 1597.330 0.140 1597.610 985.530 ;
      RECT 1599.570 0.140 1599.850 985.530 ;
      RECT 1601.810 0.140 1602.090 985.530 ;
      RECT 1604.050 0.140 1604.330 985.530 ;
      RECT 1606.290 0.140 1606.570 985.530 ;
      RECT 1608.530 0.140 1608.810 985.530 ;
      RECT 1610.770 0.140 1611.050 985.530 ;
      RECT 1613.010 0.140 1613.290 985.530 ;
      RECT 1615.250 0.140 1615.530 985.530 ;
      RECT 1617.490 0.140 1617.770 985.530 ;
      RECT 1619.730 0.140 1620.010 985.530 ;
      RECT 1621.970 0.140 1622.250 985.530 ;
      RECT 1624.210 0.140 1624.490 985.530 ;
      RECT 1626.450 0.140 1626.730 985.530 ;
      RECT 1628.690 0.140 1628.970 985.530 ;
      RECT 1630.930 0.140 1631.210 985.530 ;
      RECT 1633.170 0.140 1633.450 985.530 ;
      RECT 1635.410 0.140 1635.690 985.530 ;
      RECT 1637.650 0.140 1637.930 985.530 ;
      RECT 1639.890 0.140 1640.170 985.530 ;
      RECT 1642.130 0.140 1642.410 985.530 ;
      RECT 1644.370 0.140 1644.650 985.530 ;
      RECT 1646.610 0.140 1646.890 985.530 ;
      RECT 1648.850 0.140 1649.130 985.530 ;
      RECT 1651.090 0.140 1651.370 985.530 ;
      RECT 1653.330 0.140 1653.610 985.530 ;
      RECT 1655.570 0.140 1655.850 985.530 ;
      RECT 1657.810 0.140 1658.090 985.530 ;
      RECT 1660.050 0.140 1660.330 985.530 ;
      RECT 1662.290 0.140 1662.570 985.530 ;
      RECT 1664.530 0.140 1664.810 985.530 ;
      RECT 1666.770 0.140 1667.050 985.530 ;
      RECT 1669.010 0.140 1669.290 985.530 ;
      RECT 1671.250 0.140 1671.530 985.530 ;
      RECT 1673.490 0.140 1673.770 985.530 ;
      RECT 1675.730 0.140 1676.010 985.530 ;
      RECT 1677.970 0.140 1678.250 985.530 ;
      RECT 1680.210 0.140 1680.490 985.530 ;
      RECT 1682.450 0.140 1682.730 985.530 ;
      RECT 1684.690 0.140 1684.970 985.530 ;
      RECT 1686.930 0.140 1687.210 985.530 ;
      RECT 1689.170 0.140 1689.450 985.530 ;
      RECT 1691.410 0.140 1691.690 985.530 ;
      RECT 1693.650 0.140 1693.930 985.530 ;
      RECT 1695.890 0.140 1696.170 985.530 ;
      RECT 1698.130 0.140 1698.410 985.530 ;
      RECT 1700.370 0.140 1700.650 985.530 ;
      RECT 1702.610 0.140 1702.890 985.530 ;
      RECT 1704.850 0.140 1705.130 985.530 ;
      RECT 1707.090 0.140 1707.370 985.530 ;
      RECT 1709.330 0.140 1709.610 985.530 ;
      RECT 1711.570 0.140 1711.850 985.530 ;
      RECT 1713.810 0.140 1714.090 985.530 ;
      RECT 1716.050 0.140 1716.330 985.530 ;
      RECT 1718.290 0.140 1718.570 985.530 ;
      RECT 1720.530 0.140 1720.810 985.530 ;
      RECT 1722.770 0.140 1723.050 985.530 ;
      RECT 1725.010 0.140 1725.290 985.530 ;
      RECT 1727.250 0.140 1727.530 985.530 ;
      RECT 1729.490 0.140 1729.770 985.530 ;
      RECT 1731.730 0.140 1732.010 985.530 ;
      RECT 1733.970 0.140 1734.250 985.530 ;
      RECT 1736.210 0.140 1736.490 985.530 ;
      RECT 1738.450 0.140 1738.730 985.530 ;
      RECT 1740.690 0.140 1740.970 985.530 ;
      RECT 1742.930 0.140 1743.210 985.530 ;
      RECT 1745.170 0.140 1745.450 985.530 ;
      RECT 1747.410 0.140 1747.690 985.530 ;
      RECT 1749.650 0.140 1749.930 985.530 ;
      RECT 1751.890 0.140 1752.170 985.530 ;
      RECT 1754.130 0.140 1754.410 985.530 ;
      RECT 1756.370 0.140 1756.650 985.530 ;
      RECT 1758.610 0.140 1758.890 985.530 ;
      RECT 1760.850 0.140 1761.130 985.530 ;
      RECT 1763.090 0.140 1763.370 985.530 ;
      RECT 1765.330 0.140 1765.610 985.530 ;
      RECT 1767.570 0.140 1767.850 985.530 ;
      RECT 1769.810 0.140 1770.090 985.530 ;
      RECT 1772.050 0.140 1772.330 985.530 ;
      RECT 1774.290 0.140 1774.570 985.530 ;
      RECT 1776.530 0.140 1776.810 985.530 ;
      RECT 1778.770 0.140 1779.050 985.530 ;
      RECT 1781.010 0.140 1781.290 985.530 ;
      RECT 1783.250 0.140 1783.530 985.530 ;
      RECT 1785.490 0.140 1785.770 985.530 ;
      RECT 1787.730 0.140 1788.010 985.530 ;
      RECT 1789.970 0.140 1790.250 985.530 ;
      RECT 1792.210 0.140 1792.490 985.530 ;
      RECT 1794.450 0.140 1794.730 985.530 ;
      RECT 1796.690 0.140 1796.970 985.530 ;
      RECT 1798.930 0.140 1799.210 985.530 ;
      RECT 1801.170 0.140 1801.450 985.530 ;
      RECT 1803.410 0.140 1803.690 985.530 ;
      RECT 1805.650 0.140 1805.930 985.530 ;
      RECT 1807.890 0.140 1808.170 985.530 ;
      RECT 1810.130 0.140 1810.410 985.530 ;
      RECT 1812.370 0.140 1812.650 985.530 ;
      RECT 1814.610 0.140 1814.890 985.530 ;
      RECT 1816.850 0.140 1817.130 985.530 ;
      RECT 1819.090 0.140 1819.370 985.530 ;
      RECT 1821.330 0.140 1821.610 985.530 ;
      RECT 1823.570 0.140 1823.850 985.530 ;
      RECT 1825.810 0.140 1826.090 985.530 ;
      RECT 1828.050 0.140 1828.330 985.530 ;
      RECT 1830.290 0.140 1830.570 985.530 ;
      RECT 1832.530 0.140 1832.810 985.530 ;
      RECT 1834.770 0.140 1835.050 985.530 ;
    END
  END VSS
  PIN VDD
    DIRECTION INOUT ;
    USE POWER ;
    PORT
      LAYER metal4 ;
      RECT 1.330 0.140 1.610 985.530 ;
      RECT 3.570 0.140 3.850 985.530 ;
      RECT 5.810 0.140 6.090 985.530 ;
      RECT 8.050 0.140 8.330 985.530 ;
      RECT 10.290 0.140 10.570 985.530 ;
      RECT 12.530 0.140 12.810 985.530 ;
      RECT 14.770 0.140 15.050 985.530 ;
      RECT 17.010 0.140 17.290 985.530 ;
      RECT 19.250 0.140 19.530 985.530 ;
      RECT 21.490 0.140 21.770 985.530 ;
      RECT 23.730 0.140 24.010 985.530 ;
      RECT 25.970 0.140 26.250 985.530 ;
      RECT 28.210 0.140 28.490 985.530 ;
      RECT 30.450 0.140 30.730 985.530 ;
      RECT 32.690 0.140 32.970 985.530 ;
      RECT 34.930 0.140 35.210 985.530 ;
      RECT 37.170 0.140 37.450 985.530 ;
      RECT 39.410 0.140 39.690 985.530 ;
      RECT 41.650 0.140 41.930 985.530 ;
      RECT 43.890 0.140 44.170 985.530 ;
      RECT 46.130 0.140 46.410 985.530 ;
      RECT 48.370 0.140 48.650 985.530 ;
      RECT 50.610 0.140 50.890 985.530 ;
      RECT 52.850 0.140 53.130 985.530 ;
      RECT 55.090 0.140 55.370 985.530 ;
      RECT 57.330 0.140 57.610 985.530 ;
      RECT 59.570 0.140 59.850 985.530 ;
      RECT 61.810 0.140 62.090 985.530 ;
      RECT 64.050 0.140 64.330 985.530 ;
      RECT 66.290 0.140 66.570 985.530 ;
      RECT 68.530 0.140 68.810 985.530 ;
      RECT 70.770 0.140 71.050 985.530 ;
      RECT 73.010 0.140 73.290 985.530 ;
      RECT 75.250 0.140 75.530 985.530 ;
      RECT 77.490 0.140 77.770 985.530 ;
      RECT 79.730 0.140 80.010 985.530 ;
      RECT 81.970 0.140 82.250 985.530 ;
      RECT 84.210 0.140 84.490 985.530 ;
      RECT 86.450 0.140 86.730 985.530 ;
      RECT 88.690 0.140 88.970 985.530 ;
      RECT 90.930 0.140 91.210 985.530 ;
      RECT 93.170 0.140 93.450 985.530 ;
      RECT 95.410 0.140 95.690 985.530 ;
      RECT 97.650 0.140 97.930 985.530 ;
      RECT 99.890 0.140 100.170 985.530 ;
      RECT 102.130 0.140 102.410 985.530 ;
      RECT 104.370 0.140 104.650 985.530 ;
      RECT 106.610 0.140 106.890 985.530 ;
      RECT 108.850 0.140 109.130 985.530 ;
      RECT 111.090 0.140 111.370 985.530 ;
      RECT 113.330 0.140 113.610 985.530 ;
      RECT 115.570 0.140 115.850 985.530 ;
      RECT 117.810 0.140 118.090 985.530 ;
      RECT 120.050 0.140 120.330 985.530 ;
      RECT 122.290 0.140 122.570 985.530 ;
      RECT 124.530 0.140 124.810 985.530 ;
      RECT 126.770 0.140 127.050 985.530 ;
      RECT 129.010 0.140 129.290 985.530 ;
      RECT 131.250 0.140 131.530 985.530 ;
      RECT 133.490 0.140 133.770 985.530 ;
      RECT 135.730 0.140 136.010 985.530 ;
      RECT 137.970 0.140 138.250 985.530 ;
      RECT 140.210 0.140 140.490 985.530 ;
      RECT 142.450 0.140 142.730 985.530 ;
      RECT 144.690 0.140 144.970 985.530 ;
      RECT 146.930 0.140 147.210 985.530 ;
      RECT 149.170 0.140 149.450 985.530 ;
      RECT 151.410 0.140 151.690 985.530 ;
      RECT 153.650 0.140 153.930 985.530 ;
      RECT 155.890 0.140 156.170 985.530 ;
      RECT 158.130 0.140 158.410 985.530 ;
      RECT 160.370 0.140 160.650 985.530 ;
      RECT 162.610 0.140 162.890 985.530 ;
      RECT 164.850 0.140 165.130 985.530 ;
      RECT 167.090 0.140 167.370 985.530 ;
      RECT 169.330 0.140 169.610 985.530 ;
      RECT 171.570 0.140 171.850 985.530 ;
      RECT 173.810 0.140 174.090 985.530 ;
      RECT 176.050 0.140 176.330 985.530 ;
      RECT 178.290 0.140 178.570 985.530 ;
      RECT 180.530 0.140 180.810 985.530 ;
      RECT 182.770 0.140 183.050 985.530 ;
      RECT 185.010 0.140 185.290 985.530 ;
      RECT 187.250 0.140 187.530 985.530 ;
      RECT 189.490 0.140 189.770 985.530 ;
      RECT 191.730 0.140 192.010 985.530 ;
      RECT 193.970 0.140 194.250 985.530 ;
      RECT 196.210 0.140 196.490 985.530 ;
      RECT 198.450 0.140 198.730 985.530 ;
      RECT 200.690 0.140 200.970 985.530 ;
      RECT 202.930 0.140 203.210 985.530 ;
      RECT 205.170 0.140 205.450 985.530 ;
      RECT 207.410 0.140 207.690 985.530 ;
      RECT 209.650 0.140 209.930 985.530 ;
      RECT 211.890 0.140 212.170 985.530 ;
      RECT 214.130 0.140 214.410 985.530 ;
      RECT 216.370 0.140 216.650 985.530 ;
      RECT 218.610 0.140 218.890 985.530 ;
      RECT 220.850 0.140 221.130 985.530 ;
      RECT 223.090 0.140 223.370 985.530 ;
      RECT 225.330 0.140 225.610 985.530 ;
      RECT 227.570 0.140 227.850 985.530 ;
      RECT 229.810 0.140 230.090 985.530 ;
      RECT 232.050 0.140 232.330 985.530 ;
      RECT 234.290 0.140 234.570 985.530 ;
      RECT 236.530 0.140 236.810 985.530 ;
      RECT 238.770 0.140 239.050 985.530 ;
      RECT 241.010 0.140 241.290 985.530 ;
      RECT 243.250 0.140 243.530 985.530 ;
      RECT 245.490 0.140 245.770 985.530 ;
      RECT 247.730 0.140 248.010 985.530 ;
      RECT 249.970 0.140 250.250 985.530 ;
      RECT 252.210 0.140 252.490 985.530 ;
      RECT 254.450 0.140 254.730 985.530 ;
      RECT 256.690 0.140 256.970 985.530 ;
      RECT 258.930 0.140 259.210 985.530 ;
      RECT 261.170 0.140 261.450 985.530 ;
      RECT 263.410 0.140 263.690 985.530 ;
      RECT 265.650 0.140 265.930 985.530 ;
      RECT 267.890 0.140 268.170 985.530 ;
      RECT 270.130 0.140 270.410 985.530 ;
      RECT 272.370 0.140 272.650 985.530 ;
      RECT 274.610 0.140 274.890 985.530 ;
      RECT 276.850 0.140 277.130 985.530 ;
      RECT 279.090 0.140 279.370 985.530 ;
      RECT 281.330 0.140 281.610 985.530 ;
      RECT 283.570 0.140 283.850 985.530 ;
      RECT 285.810 0.140 286.090 985.530 ;
      RECT 288.050 0.140 288.330 985.530 ;
      RECT 290.290 0.140 290.570 985.530 ;
      RECT 292.530 0.140 292.810 985.530 ;
      RECT 294.770 0.140 295.050 985.530 ;
      RECT 297.010 0.140 297.290 985.530 ;
      RECT 299.250 0.140 299.530 985.530 ;
      RECT 301.490 0.140 301.770 985.530 ;
      RECT 303.730 0.140 304.010 985.530 ;
      RECT 305.970 0.140 306.250 985.530 ;
      RECT 308.210 0.140 308.490 985.530 ;
      RECT 310.450 0.140 310.730 985.530 ;
      RECT 312.690 0.140 312.970 985.530 ;
      RECT 314.930 0.140 315.210 985.530 ;
      RECT 317.170 0.140 317.450 985.530 ;
      RECT 319.410 0.140 319.690 985.530 ;
      RECT 321.650 0.140 321.930 985.530 ;
      RECT 323.890 0.140 324.170 985.530 ;
      RECT 326.130 0.140 326.410 985.530 ;
      RECT 328.370 0.140 328.650 985.530 ;
      RECT 330.610 0.140 330.890 985.530 ;
      RECT 332.850 0.140 333.130 985.530 ;
      RECT 335.090 0.140 335.370 985.530 ;
      RECT 337.330 0.140 337.610 985.530 ;
      RECT 339.570 0.140 339.850 985.530 ;
      RECT 341.810 0.140 342.090 985.530 ;
      RECT 344.050 0.140 344.330 985.530 ;
      RECT 346.290 0.140 346.570 985.530 ;
      RECT 348.530 0.140 348.810 985.530 ;
      RECT 350.770 0.140 351.050 985.530 ;
      RECT 353.010 0.140 353.290 985.530 ;
      RECT 355.250 0.140 355.530 985.530 ;
      RECT 357.490 0.140 357.770 985.530 ;
      RECT 359.730 0.140 360.010 985.530 ;
      RECT 361.970 0.140 362.250 985.530 ;
      RECT 364.210 0.140 364.490 985.530 ;
      RECT 366.450 0.140 366.730 985.530 ;
      RECT 368.690 0.140 368.970 985.530 ;
      RECT 370.930 0.140 371.210 985.530 ;
      RECT 373.170 0.140 373.450 985.530 ;
      RECT 375.410 0.140 375.690 985.530 ;
      RECT 377.650 0.140 377.930 985.530 ;
      RECT 379.890 0.140 380.170 985.530 ;
      RECT 382.130 0.140 382.410 985.530 ;
      RECT 384.370 0.140 384.650 985.530 ;
      RECT 386.610 0.140 386.890 985.530 ;
      RECT 388.850 0.140 389.130 985.530 ;
      RECT 391.090 0.140 391.370 985.530 ;
      RECT 393.330 0.140 393.610 985.530 ;
      RECT 395.570 0.140 395.850 985.530 ;
      RECT 397.810 0.140 398.090 985.530 ;
      RECT 400.050 0.140 400.330 985.530 ;
      RECT 402.290 0.140 402.570 985.530 ;
      RECT 404.530 0.140 404.810 985.530 ;
      RECT 406.770 0.140 407.050 985.530 ;
      RECT 409.010 0.140 409.290 985.530 ;
      RECT 411.250 0.140 411.530 985.530 ;
      RECT 413.490 0.140 413.770 985.530 ;
      RECT 415.730 0.140 416.010 985.530 ;
      RECT 417.970 0.140 418.250 985.530 ;
      RECT 420.210 0.140 420.490 985.530 ;
      RECT 422.450 0.140 422.730 985.530 ;
      RECT 424.690 0.140 424.970 985.530 ;
      RECT 426.930 0.140 427.210 985.530 ;
      RECT 429.170 0.140 429.450 985.530 ;
      RECT 431.410 0.140 431.690 985.530 ;
      RECT 433.650 0.140 433.930 985.530 ;
      RECT 435.890 0.140 436.170 985.530 ;
      RECT 438.130 0.140 438.410 985.530 ;
      RECT 440.370 0.140 440.650 985.530 ;
      RECT 442.610 0.140 442.890 985.530 ;
      RECT 444.850 0.140 445.130 985.530 ;
      RECT 447.090 0.140 447.370 985.530 ;
      RECT 449.330 0.140 449.610 985.530 ;
      RECT 451.570 0.140 451.850 985.530 ;
      RECT 453.810 0.140 454.090 985.530 ;
      RECT 456.050 0.140 456.330 985.530 ;
      RECT 458.290 0.140 458.570 985.530 ;
      RECT 460.530 0.140 460.810 985.530 ;
      RECT 462.770 0.140 463.050 985.530 ;
      RECT 465.010 0.140 465.290 985.530 ;
      RECT 467.250 0.140 467.530 985.530 ;
      RECT 469.490 0.140 469.770 985.530 ;
      RECT 471.730 0.140 472.010 985.530 ;
      RECT 473.970 0.140 474.250 985.530 ;
      RECT 476.210 0.140 476.490 985.530 ;
      RECT 478.450 0.140 478.730 985.530 ;
      RECT 480.690 0.140 480.970 985.530 ;
      RECT 482.930 0.140 483.210 985.530 ;
      RECT 485.170 0.140 485.450 985.530 ;
      RECT 487.410 0.140 487.690 985.530 ;
      RECT 489.650 0.140 489.930 985.530 ;
      RECT 491.890 0.140 492.170 985.530 ;
      RECT 494.130 0.140 494.410 985.530 ;
      RECT 496.370 0.140 496.650 985.530 ;
      RECT 498.610 0.140 498.890 985.530 ;
      RECT 500.850 0.140 501.130 985.530 ;
      RECT 503.090 0.140 503.370 985.530 ;
      RECT 505.330 0.140 505.610 985.530 ;
      RECT 507.570 0.140 507.850 985.530 ;
      RECT 509.810 0.140 510.090 985.530 ;
      RECT 512.050 0.140 512.330 985.530 ;
      RECT 514.290 0.140 514.570 985.530 ;
      RECT 516.530 0.140 516.810 985.530 ;
      RECT 518.770 0.140 519.050 985.530 ;
      RECT 521.010 0.140 521.290 985.530 ;
      RECT 523.250 0.140 523.530 985.530 ;
      RECT 525.490 0.140 525.770 985.530 ;
      RECT 527.730 0.140 528.010 985.530 ;
      RECT 529.970 0.140 530.250 985.530 ;
      RECT 532.210 0.140 532.490 985.530 ;
      RECT 534.450 0.140 534.730 985.530 ;
      RECT 536.690 0.140 536.970 985.530 ;
      RECT 538.930 0.140 539.210 985.530 ;
      RECT 541.170 0.140 541.450 985.530 ;
      RECT 543.410 0.140 543.690 985.530 ;
      RECT 545.650 0.140 545.930 985.530 ;
      RECT 547.890 0.140 548.170 985.530 ;
      RECT 550.130 0.140 550.410 985.530 ;
      RECT 552.370 0.140 552.650 985.530 ;
      RECT 554.610 0.140 554.890 985.530 ;
      RECT 556.850 0.140 557.130 985.530 ;
      RECT 559.090 0.140 559.370 985.530 ;
      RECT 561.330 0.140 561.610 985.530 ;
      RECT 563.570 0.140 563.850 985.530 ;
      RECT 565.810 0.140 566.090 985.530 ;
      RECT 568.050 0.140 568.330 985.530 ;
      RECT 570.290 0.140 570.570 985.530 ;
      RECT 572.530 0.140 572.810 985.530 ;
      RECT 574.770 0.140 575.050 985.530 ;
      RECT 577.010 0.140 577.290 985.530 ;
      RECT 579.250 0.140 579.530 985.530 ;
      RECT 581.490 0.140 581.770 985.530 ;
      RECT 583.730 0.140 584.010 985.530 ;
      RECT 585.970 0.140 586.250 985.530 ;
      RECT 588.210 0.140 588.490 985.530 ;
      RECT 590.450 0.140 590.730 985.530 ;
      RECT 592.690 0.140 592.970 985.530 ;
      RECT 594.930 0.140 595.210 985.530 ;
      RECT 597.170 0.140 597.450 985.530 ;
      RECT 599.410 0.140 599.690 985.530 ;
      RECT 601.650 0.140 601.930 985.530 ;
      RECT 603.890 0.140 604.170 985.530 ;
      RECT 606.130 0.140 606.410 985.530 ;
      RECT 608.370 0.140 608.650 985.530 ;
      RECT 610.610 0.140 610.890 985.530 ;
      RECT 612.850 0.140 613.130 985.530 ;
      RECT 615.090 0.140 615.370 985.530 ;
      RECT 617.330 0.140 617.610 985.530 ;
      RECT 619.570 0.140 619.850 985.530 ;
      RECT 621.810 0.140 622.090 985.530 ;
      RECT 624.050 0.140 624.330 985.530 ;
      RECT 626.290 0.140 626.570 985.530 ;
      RECT 628.530 0.140 628.810 985.530 ;
      RECT 630.770 0.140 631.050 985.530 ;
      RECT 633.010 0.140 633.290 985.530 ;
      RECT 635.250 0.140 635.530 985.530 ;
      RECT 637.490 0.140 637.770 985.530 ;
      RECT 639.730 0.140 640.010 985.530 ;
      RECT 641.970 0.140 642.250 985.530 ;
      RECT 644.210 0.140 644.490 985.530 ;
      RECT 646.450 0.140 646.730 985.530 ;
      RECT 648.690 0.140 648.970 985.530 ;
      RECT 650.930 0.140 651.210 985.530 ;
      RECT 653.170 0.140 653.450 985.530 ;
      RECT 655.410 0.140 655.690 985.530 ;
      RECT 657.650 0.140 657.930 985.530 ;
      RECT 659.890 0.140 660.170 985.530 ;
      RECT 662.130 0.140 662.410 985.530 ;
      RECT 664.370 0.140 664.650 985.530 ;
      RECT 666.610 0.140 666.890 985.530 ;
      RECT 668.850 0.140 669.130 985.530 ;
      RECT 671.090 0.140 671.370 985.530 ;
      RECT 673.330 0.140 673.610 985.530 ;
      RECT 675.570 0.140 675.850 985.530 ;
      RECT 677.810 0.140 678.090 985.530 ;
      RECT 680.050 0.140 680.330 985.530 ;
      RECT 682.290 0.140 682.570 985.530 ;
      RECT 684.530 0.140 684.810 985.530 ;
      RECT 686.770 0.140 687.050 985.530 ;
      RECT 689.010 0.140 689.290 985.530 ;
      RECT 691.250 0.140 691.530 985.530 ;
      RECT 693.490 0.140 693.770 985.530 ;
      RECT 695.730 0.140 696.010 985.530 ;
      RECT 697.970 0.140 698.250 985.530 ;
      RECT 700.210 0.140 700.490 985.530 ;
      RECT 702.450 0.140 702.730 985.530 ;
      RECT 704.690 0.140 704.970 985.530 ;
      RECT 706.930 0.140 707.210 985.530 ;
      RECT 709.170 0.140 709.450 985.530 ;
      RECT 711.410 0.140 711.690 985.530 ;
      RECT 713.650 0.140 713.930 985.530 ;
      RECT 715.890 0.140 716.170 985.530 ;
      RECT 718.130 0.140 718.410 985.530 ;
      RECT 720.370 0.140 720.650 985.530 ;
      RECT 722.610 0.140 722.890 985.530 ;
      RECT 724.850 0.140 725.130 985.530 ;
      RECT 727.090 0.140 727.370 985.530 ;
      RECT 729.330 0.140 729.610 985.530 ;
      RECT 731.570 0.140 731.850 985.530 ;
      RECT 733.810 0.140 734.090 985.530 ;
      RECT 736.050 0.140 736.330 985.530 ;
      RECT 738.290 0.140 738.570 985.530 ;
      RECT 740.530 0.140 740.810 985.530 ;
      RECT 742.770 0.140 743.050 985.530 ;
      RECT 745.010 0.140 745.290 985.530 ;
      RECT 747.250 0.140 747.530 985.530 ;
      RECT 749.490 0.140 749.770 985.530 ;
      RECT 751.730 0.140 752.010 985.530 ;
      RECT 753.970 0.140 754.250 985.530 ;
      RECT 756.210 0.140 756.490 985.530 ;
      RECT 758.450 0.140 758.730 985.530 ;
      RECT 760.690 0.140 760.970 985.530 ;
      RECT 762.930 0.140 763.210 985.530 ;
      RECT 765.170 0.140 765.450 985.530 ;
      RECT 767.410 0.140 767.690 985.530 ;
      RECT 769.650 0.140 769.930 985.530 ;
      RECT 771.890 0.140 772.170 985.530 ;
      RECT 774.130 0.140 774.410 985.530 ;
      RECT 776.370 0.140 776.650 985.530 ;
      RECT 778.610 0.140 778.890 985.530 ;
      RECT 780.850 0.140 781.130 985.530 ;
      RECT 783.090 0.140 783.370 985.530 ;
      RECT 785.330 0.140 785.610 985.530 ;
      RECT 787.570 0.140 787.850 985.530 ;
      RECT 789.810 0.140 790.090 985.530 ;
      RECT 792.050 0.140 792.330 985.530 ;
      RECT 794.290 0.140 794.570 985.530 ;
      RECT 796.530 0.140 796.810 985.530 ;
      RECT 798.770 0.140 799.050 985.530 ;
      RECT 801.010 0.140 801.290 985.530 ;
      RECT 803.250 0.140 803.530 985.530 ;
      RECT 805.490 0.140 805.770 985.530 ;
      RECT 807.730 0.140 808.010 985.530 ;
      RECT 809.970 0.140 810.250 985.530 ;
      RECT 812.210 0.140 812.490 985.530 ;
      RECT 814.450 0.140 814.730 985.530 ;
      RECT 816.690 0.140 816.970 985.530 ;
      RECT 818.930 0.140 819.210 985.530 ;
      RECT 821.170 0.140 821.450 985.530 ;
      RECT 823.410 0.140 823.690 985.530 ;
      RECT 825.650 0.140 825.930 985.530 ;
      RECT 827.890 0.140 828.170 985.530 ;
      RECT 830.130 0.140 830.410 985.530 ;
      RECT 832.370 0.140 832.650 985.530 ;
      RECT 834.610 0.140 834.890 985.530 ;
      RECT 836.850 0.140 837.130 985.530 ;
      RECT 839.090 0.140 839.370 985.530 ;
      RECT 841.330 0.140 841.610 985.530 ;
      RECT 843.570 0.140 843.850 985.530 ;
      RECT 845.810 0.140 846.090 985.530 ;
      RECT 848.050 0.140 848.330 985.530 ;
      RECT 850.290 0.140 850.570 985.530 ;
      RECT 852.530 0.140 852.810 985.530 ;
      RECT 854.770 0.140 855.050 985.530 ;
      RECT 857.010 0.140 857.290 985.530 ;
      RECT 859.250 0.140 859.530 985.530 ;
      RECT 861.490 0.140 861.770 985.530 ;
      RECT 863.730 0.140 864.010 985.530 ;
      RECT 865.970 0.140 866.250 985.530 ;
      RECT 868.210 0.140 868.490 985.530 ;
      RECT 870.450 0.140 870.730 985.530 ;
      RECT 872.690 0.140 872.970 985.530 ;
      RECT 874.930 0.140 875.210 985.530 ;
      RECT 877.170 0.140 877.450 985.530 ;
      RECT 879.410 0.140 879.690 985.530 ;
      RECT 881.650 0.140 881.930 985.530 ;
      RECT 883.890 0.140 884.170 985.530 ;
      RECT 886.130 0.140 886.410 985.530 ;
      RECT 888.370 0.140 888.650 985.530 ;
      RECT 890.610 0.140 890.890 985.530 ;
      RECT 892.850 0.140 893.130 985.530 ;
      RECT 895.090 0.140 895.370 985.530 ;
      RECT 897.330 0.140 897.610 985.530 ;
      RECT 899.570 0.140 899.850 985.530 ;
      RECT 901.810 0.140 902.090 985.530 ;
      RECT 904.050 0.140 904.330 985.530 ;
      RECT 906.290 0.140 906.570 985.530 ;
      RECT 908.530 0.140 908.810 985.530 ;
      RECT 910.770 0.140 911.050 985.530 ;
      RECT 913.010 0.140 913.290 985.530 ;
      RECT 915.250 0.140 915.530 985.530 ;
      RECT 917.490 0.140 917.770 985.530 ;
      RECT 919.730 0.140 920.010 985.530 ;
      RECT 921.970 0.140 922.250 985.530 ;
      RECT 924.210 0.140 924.490 985.530 ;
      RECT 926.450 0.140 926.730 985.530 ;
      RECT 928.690 0.140 928.970 985.530 ;
      RECT 930.930 0.140 931.210 985.530 ;
      RECT 933.170 0.140 933.450 985.530 ;
      RECT 935.410 0.140 935.690 985.530 ;
      RECT 937.650 0.140 937.930 985.530 ;
      RECT 939.890 0.140 940.170 985.530 ;
      RECT 942.130 0.140 942.410 985.530 ;
      RECT 944.370 0.140 944.650 985.530 ;
      RECT 946.610 0.140 946.890 985.530 ;
      RECT 948.850 0.140 949.130 985.530 ;
      RECT 951.090 0.140 951.370 985.530 ;
      RECT 953.330 0.140 953.610 985.530 ;
      RECT 955.570 0.140 955.850 985.530 ;
      RECT 957.810 0.140 958.090 985.530 ;
      RECT 960.050 0.140 960.330 985.530 ;
      RECT 962.290 0.140 962.570 985.530 ;
      RECT 964.530 0.140 964.810 985.530 ;
      RECT 966.770 0.140 967.050 985.530 ;
      RECT 969.010 0.140 969.290 985.530 ;
      RECT 971.250 0.140 971.530 985.530 ;
      RECT 973.490 0.140 973.770 985.530 ;
      RECT 975.730 0.140 976.010 985.530 ;
      RECT 977.970 0.140 978.250 985.530 ;
      RECT 980.210 0.140 980.490 985.530 ;
      RECT 982.450 0.140 982.730 985.530 ;
      RECT 984.690 0.140 984.970 985.530 ;
      RECT 986.930 0.140 987.210 985.530 ;
      RECT 989.170 0.140 989.450 985.530 ;
      RECT 991.410 0.140 991.690 985.530 ;
      RECT 993.650 0.140 993.930 985.530 ;
      RECT 995.890 0.140 996.170 985.530 ;
      RECT 998.130 0.140 998.410 985.530 ;
      RECT 1000.370 0.140 1000.650 985.530 ;
      RECT 1002.610 0.140 1002.890 985.530 ;
      RECT 1004.850 0.140 1005.130 985.530 ;
      RECT 1007.090 0.140 1007.370 985.530 ;
      RECT 1009.330 0.140 1009.610 985.530 ;
      RECT 1011.570 0.140 1011.850 985.530 ;
      RECT 1013.810 0.140 1014.090 985.530 ;
      RECT 1016.050 0.140 1016.330 985.530 ;
      RECT 1018.290 0.140 1018.570 985.530 ;
      RECT 1020.530 0.140 1020.810 985.530 ;
      RECT 1022.770 0.140 1023.050 985.530 ;
      RECT 1025.010 0.140 1025.290 985.530 ;
      RECT 1027.250 0.140 1027.530 985.530 ;
      RECT 1029.490 0.140 1029.770 985.530 ;
      RECT 1031.730 0.140 1032.010 985.530 ;
      RECT 1033.970 0.140 1034.250 985.530 ;
      RECT 1036.210 0.140 1036.490 985.530 ;
      RECT 1038.450 0.140 1038.730 985.530 ;
      RECT 1040.690 0.140 1040.970 985.530 ;
      RECT 1042.930 0.140 1043.210 985.530 ;
      RECT 1045.170 0.140 1045.450 985.530 ;
      RECT 1047.410 0.140 1047.690 985.530 ;
      RECT 1049.650 0.140 1049.930 985.530 ;
      RECT 1051.890 0.140 1052.170 985.530 ;
      RECT 1054.130 0.140 1054.410 985.530 ;
      RECT 1056.370 0.140 1056.650 985.530 ;
      RECT 1058.610 0.140 1058.890 985.530 ;
      RECT 1060.850 0.140 1061.130 985.530 ;
      RECT 1063.090 0.140 1063.370 985.530 ;
      RECT 1065.330 0.140 1065.610 985.530 ;
      RECT 1067.570 0.140 1067.850 985.530 ;
      RECT 1069.810 0.140 1070.090 985.530 ;
      RECT 1072.050 0.140 1072.330 985.530 ;
      RECT 1074.290 0.140 1074.570 985.530 ;
      RECT 1076.530 0.140 1076.810 985.530 ;
      RECT 1078.770 0.140 1079.050 985.530 ;
      RECT 1081.010 0.140 1081.290 985.530 ;
      RECT 1083.250 0.140 1083.530 985.530 ;
      RECT 1085.490 0.140 1085.770 985.530 ;
      RECT 1087.730 0.140 1088.010 985.530 ;
      RECT 1089.970 0.140 1090.250 985.530 ;
      RECT 1092.210 0.140 1092.490 985.530 ;
      RECT 1094.450 0.140 1094.730 985.530 ;
      RECT 1096.690 0.140 1096.970 985.530 ;
      RECT 1098.930 0.140 1099.210 985.530 ;
      RECT 1101.170 0.140 1101.450 985.530 ;
      RECT 1103.410 0.140 1103.690 985.530 ;
      RECT 1105.650 0.140 1105.930 985.530 ;
      RECT 1107.890 0.140 1108.170 985.530 ;
      RECT 1110.130 0.140 1110.410 985.530 ;
      RECT 1112.370 0.140 1112.650 985.530 ;
      RECT 1114.610 0.140 1114.890 985.530 ;
      RECT 1116.850 0.140 1117.130 985.530 ;
      RECT 1119.090 0.140 1119.370 985.530 ;
      RECT 1121.330 0.140 1121.610 985.530 ;
      RECT 1123.570 0.140 1123.850 985.530 ;
      RECT 1125.810 0.140 1126.090 985.530 ;
      RECT 1128.050 0.140 1128.330 985.530 ;
      RECT 1130.290 0.140 1130.570 985.530 ;
      RECT 1132.530 0.140 1132.810 985.530 ;
      RECT 1134.770 0.140 1135.050 985.530 ;
      RECT 1137.010 0.140 1137.290 985.530 ;
      RECT 1139.250 0.140 1139.530 985.530 ;
      RECT 1141.490 0.140 1141.770 985.530 ;
      RECT 1143.730 0.140 1144.010 985.530 ;
      RECT 1145.970 0.140 1146.250 985.530 ;
      RECT 1148.210 0.140 1148.490 985.530 ;
      RECT 1150.450 0.140 1150.730 985.530 ;
      RECT 1152.690 0.140 1152.970 985.530 ;
      RECT 1154.930 0.140 1155.210 985.530 ;
      RECT 1157.170 0.140 1157.450 985.530 ;
      RECT 1159.410 0.140 1159.690 985.530 ;
      RECT 1161.650 0.140 1161.930 985.530 ;
      RECT 1163.890 0.140 1164.170 985.530 ;
      RECT 1166.130 0.140 1166.410 985.530 ;
      RECT 1168.370 0.140 1168.650 985.530 ;
      RECT 1170.610 0.140 1170.890 985.530 ;
      RECT 1172.850 0.140 1173.130 985.530 ;
      RECT 1175.090 0.140 1175.370 985.530 ;
      RECT 1177.330 0.140 1177.610 985.530 ;
      RECT 1179.570 0.140 1179.850 985.530 ;
      RECT 1181.810 0.140 1182.090 985.530 ;
      RECT 1184.050 0.140 1184.330 985.530 ;
      RECT 1186.290 0.140 1186.570 985.530 ;
      RECT 1188.530 0.140 1188.810 985.530 ;
      RECT 1190.770 0.140 1191.050 985.530 ;
      RECT 1193.010 0.140 1193.290 985.530 ;
      RECT 1195.250 0.140 1195.530 985.530 ;
      RECT 1197.490 0.140 1197.770 985.530 ;
      RECT 1199.730 0.140 1200.010 985.530 ;
      RECT 1201.970 0.140 1202.250 985.530 ;
      RECT 1204.210 0.140 1204.490 985.530 ;
      RECT 1206.450 0.140 1206.730 985.530 ;
      RECT 1208.690 0.140 1208.970 985.530 ;
      RECT 1210.930 0.140 1211.210 985.530 ;
      RECT 1213.170 0.140 1213.450 985.530 ;
      RECT 1215.410 0.140 1215.690 985.530 ;
      RECT 1217.650 0.140 1217.930 985.530 ;
      RECT 1219.890 0.140 1220.170 985.530 ;
      RECT 1222.130 0.140 1222.410 985.530 ;
      RECT 1224.370 0.140 1224.650 985.530 ;
      RECT 1226.610 0.140 1226.890 985.530 ;
      RECT 1228.850 0.140 1229.130 985.530 ;
      RECT 1231.090 0.140 1231.370 985.530 ;
      RECT 1233.330 0.140 1233.610 985.530 ;
      RECT 1235.570 0.140 1235.850 985.530 ;
      RECT 1237.810 0.140 1238.090 985.530 ;
      RECT 1240.050 0.140 1240.330 985.530 ;
      RECT 1242.290 0.140 1242.570 985.530 ;
      RECT 1244.530 0.140 1244.810 985.530 ;
      RECT 1246.770 0.140 1247.050 985.530 ;
      RECT 1249.010 0.140 1249.290 985.530 ;
      RECT 1251.250 0.140 1251.530 985.530 ;
      RECT 1253.490 0.140 1253.770 985.530 ;
      RECT 1255.730 0.140 1256.010 985.530 ;
      RECT 1257.970 0.140 1258.250 985.530 ;
      RECT 1260.210 0.140 1260.490 985.530 ;
      RECT 1262.450 0.140 1262.730 985.530 ;
      RECT 1264.690 0.140 1264.970 985.530 ;
      RECT 1266.930 0.140 1267.210 985.530 ;
      RECT 1269.170 0.140 1269.450 985.530 ;
      RECT 1271.410 0.140 1271.690 985.530 ;
      RECT 1273.650 0.140 1273.930 985.530 ;
      RECT 1275.890 0.140 1276.170 985.530 ;
      RECT 1278.130 0.140 1278.410 985.530 ;
      RECT 1280.370 0.140 1280.650 985.530 ;
      RECT 1282.610 0.140 1282.890 985.530 ;
      RECT 1284.850 0.140 1285.130 985.530 ;
      RECT 1287.090 0.140 1287.370 985.530 ;
      RECT 1289.330 0.140 1289.610 985.530 ;
      RECT 1291.570 0.140 1291.850 985.530 ;
      RECT 1293.810 0.140 1294.090 985.530 ;
      RECT 1296.050 0.140 1296.330 985.530 ;
      RECT 1298.290 0.140 1298.570 985.530 ;
      RECT 1300.530 0.140 1300.810 985.530 ;
      RECT 1302.770 0.140 1303.050 985.530 ;
      RECT 1305.010 0.140 1305.290 985.530 ;
      RECT 1307.250 0.140 1307.530 985.530 ;
      RECT 1309.490 0.140 1309.770 985.530 ;
      RECT 1311.730 0.140 1312.010 985.530 ;
      RECT 1313.970 0.140 1314.250 985.530 ;
      RECT 1316.210 0.140 1316.490 985.530 ;
      RECT 1318.450 0.140 1318.730 985.530 ;
      RECT 1320.690 0.140 1320.970 985.530 ;
      RECT 1322.930 0.140 1323.210 985.530 ;
      RECT 1325.170 0.140 1325.450 985.530 ;
      RECT 1327.410 0.140 1327.690 985.530 ;
      RECT 1329.650 0.140 1329.930 985.530 ;
      RECT 1331.890 0.140 1332.170 985.530 ;
      RECT 1334.130 0.140 1334.410 985.530 ;
      RECT 1336.370 0.140 1336.650 985.530 ;
      RECT 1338.610 0.140 1338.890 985.530 ;
      RECT 1340.850 0.140 1341.130 985.530 ;
      RECT 1343.090 0.140 1343.370 985.530 ;
      RECT 1345.330 0.140 1345.610 985.530 ;
      RECT 1347.570 0.140 1347.850 985.530 ;
      RECT 1349.810 0.140 1350.090 985.530 ;
      RECT 1352.050 0.140 1352.330 985.530 ;
      RECT 1354.290 0.140 1354.570 985.530 ;
      RECT 1356.530 0.140 1356.810 985.530 ;
      RECT 1358.770 0.140 1359.050 985.530 ;
      RECT 1361.010 0.140 1361.290 985.530 ;
      RECT 1363.250 0.140 1363.530 985.530 ;
      RECT 1365.490 0.140 1365.770 985.530 ;
      RECT 1367.730 0.140 1368.010 985.530 ;
      RECT 1369.970 0.140 1370.250 985.530 ;
      RECT 1372.210 0.140 1372.490 985.530 ;
      RECT 1374.450 0.140 1374.730 985.530 ;
      RECT 1376.690 0.140 1376.970 985.530 ;
      RECT 1378.930 0.140 1379.210 985.530 ;
      RECT 1381.170 0.140 1381.450 985.530 ;
      RECT 1383.410 0.140 1383.690 985.530 ;
      RECT 1385.650 0.140 1385.930 985.530 ;
      RECT 1387.890 0.140 1388.170 985.530 ;
      RECT 1390.130 0.140 1390.410 985.530 ;
      RECT 1392.370 0.140 1392.650 985.530 ;
      RECT 1394.610 0.140 1394.890 985.530 ;
      RECT 1396.850 0.140 1397.130 985.530 ;
      RECT 1399.090 0.140 1399.370 985.530 ;
      RECT 1401.330 0.140 1401.610 985.530 ;
      RECT 1403.570 0.140 1403.850 985.530 ;
      RECT 1405.810 0.140 1406.090 985.530 ;
      RECT 1408.050 0.140 1408.330 985.530 ;
      RECT 1410.290 0.140 1410.570 985.530 ;
      RECT 1412.530 0.140 1412.810 985.530 ;
      RECT 1414.770 0.140 1415.050 985.530 ;
      RECT 1417.010 0.140 1417.290 985.530 ;
      RECT 1419.250 0.140 1419.530 985.530 ;
      RECT 1421.490 0.140 1421.770 985.530 ;
      RECT 1423.730 0.140 1424.010 985.530 ;
      RECT 1425.970 0.140 1426.250 985.530 ;
      RECT 1428.210 0.140 1428.490 985.530 ;
      RECT 1430.450 0.140 1430.730 985.530 ;
      RECT 1432.690 0.140 1432.970 985.530 ;
      RECT 1434.930 0.140 1435.210 985.530 ;
      RECT 1437.170 0.140 1437.450 985.530 ;
      RECT 1439.410 0.140 1439.690 985.530 ;
      RECT 1441.650 0.140 1441.930 985.530 ;
      RECT 1443.890 0.140 1444.170 985.530 ;
      RECT 1446.130 0.140 1446.410 985.530 ;
      RECT 1448.370 0.140 1448.650 985.530 ;
      RECT 1450.610 0.140 1450.890 985.530 ;
      RECT 1452.850 0.140 1453.130 985.530 ;
      RECT 1455.090 0.140 1455.370 985.530 ;
      RECT 1457.330 0.140 1457.610 985.530 ;
      RECT 1459.570 0.140 1459.850 985.530 ;
      RECT 1461.810 0.140 1462.090 985.530 ;
      RECT 1464.050 0.140 1464.330 985.530 ;
      RECT 1466.290 0.140 1466.570 985.530 ;
      RECT 1468.530 0.140 1468.810 985.530 ;
      RECT 1470.770 0.140 1471.050 985.530 ;
      RECT 1473.010 0.140 1473.290 985.530 ;
      RECT 1475.250 0.140 1475.530 985.530 ;
      RECT 1477.490 0.140 1477.770 985.530 ;
      RECT 1479.730 0.140 1480.010 985.530 ;
      RECT 1481.970 0.140 1482.250 985.530 ;
      RECT 1484.210 0.140 1484.490 985.530 ;
      RECT 1486.450 0.140 1486.730 985.530 ;
      RECT 1488.690 0.140 1488.970 985.530 ;
      RECT 1490.930 0.140 1491.210 985.530 ;
      RECT 1493.170 0.140 1493.450 985.530 ;
      RECT 1495.410 0.140 1495.690 985.530 ;
      RECT 1497.650 0.140 1497.930 985.530 ;
      RECT 1499.890 0.140 1500.170 985.530 ;
      RECT 1502.130 0.140 1502.410 985.530 ;
      RECT 1504.370 0.140 1504.650 985.530 ;
      RECT 1506.610 0.140 1506.890 985.530 ;
      RECT 1508.850 0.140 1509.130 985.530 ;
      RECT 1511.090 0.140 1511.370 985.530 ;
      RECT 1513.330 0.140 1513.610 985.530 ;
      RECT 1515.570 0.140 1515.850 985.530 ;
      RECT 1517.810 0.140 1518.090 985.530 ;
      RECT 1520.050 0.140 1520.330 985.530 ;
      RECT 1522.290 0.140 1522.570 985.530 ;
      RECT 1524.530 0.140 1524.810 985.530 ;
      RECT 1526.770 0.140 1527.050 985.530 ;
      RECT 1529.010 0.140 1529.290 985.530 ;
      RECT 1531.250 0.140 1531.530 985.530 ;
      RECT 1533.490 0.140 1533.770 985.530 ;
      RECT 1535.730 0.140 1536.010 985.530 ;
      RECT 1537.970 0.140 1538.250 985.530 ;
      RECT 1540.210 0.140 1540.490 985.530 ;
      RECT 1542.450 0.140 1542.730 985.530 ;
      RECT 1544.690 0.140 1544.970 985.530 ;
      RECT 1546.930 0.140 1547.210 985.530 ;
      RECT 1549.170 0.140 1549.450 985.530 ;
      RECT 1551.410 0.140 1551.690 985.530 ;
      RECT 1553.650 0.140 1553.930 985.530 ;
      RECT 1555.890 0.140 1556.170 985.530 ;
      RECT 1558.130 0.140 1558.410 985.530 ;
      RECT 1560.370 0.140 1560.650 985.530 ;
      RECT 1562.610 0.140 1562.890 985.530 ;
      RECT 1564.850 0.140 1565.130 985.530 ;
      RECT 1567.090 0.140 1567.370 985.530 ;
      RECT 1569.330 0.140 1569.610 985.530 ;
      RECT 1571.570 0.140 1571.850 985.530 ;
      RECT 1573.810 0.140 1574.090 985.530 ;
      RECT 1576.050 0.140 1576.330 985.530 ;
      RECT 1578.290 0.140 1578.570 985.530 ;
      RECT 1580.530 0.140 1580.810 985.530 ;
      RECT 1582.770 0.140 1583.050 985.530 ;
      RECT 1585.010 0.140 1585.290 985.530 ;
      RECT 1587.250 0.140 1587.530 985.530 ;
      RECT 1589.490 0.140 1589.770 985.530 ;
      RECT 1591.730 0.140 1592.010 985.530 ;
      RECT 1593.970 0.140 1594.250 985.530 ;
      RECT 1596.210 0.140 1596.490 985.530 ;
      RECT 1598.450 0.140 1598.730 985.530 ;
      RECT 1600.690 0.140 1600.970 985.530 ;
      RECT 1602.930 0.140 1603.210 985.530 ;
      RECT 1605.170 0.140 1605.450 985.530 ;
      RECT 1607.410 0.140 1607.690 985.530 ;
      RECT 1609.650 0.140 1609.930 985.530 ;
      RECT 1611.890 0.140 1612.170 985.530 ;
      RECT 1614.130 0.140 1614.410 985.530 ;
      RECT 1616.370 0.140 1616.650 985.530 ;
      RECT 1618.610 0.140 1618.890 985.530 ;
      RECT 1620.850 0.140 1621.130 985.530 ;
      RECT 1623.090 0.140 1623.370 985.530 ;
      RECT 1625.330 0.140 1625.610 985.530 ;
      RECT 1627.570 0.140 1627.850 985.530 ;
      RECT 1629.810 0.140 1630.090 985.530 ;
      RECT 1632.050 0.140 1632.330 985.530 ;
      RECT 1634.290 0.140 1634.570 985.530 ;
      RECT 1636.530 0.140 1636.810 985.530 ;
      RECT 1638.770 0.140 1639.050 985.530 ;
      RECT 1641.010 0.140 1641.290 985.530 ;
      RECT 1643.250 0.140 1643.530 985.530 ;
      RECT 1645.490 0.140 1645.770 985.530 ;
      RECT 1647.730 0.140 1648.010 985.530 ;
      RECT 1649.970 0.140 1650.250 985.530 ;
      RECT 1652.210 0.140 1652.490 985.530 ;
      RECT 1654.450 0.140 1654.730 985.530 ;
      RECT 1656.690 0.140 1656.970 985.530 ;
      RECT 1658.930 0.140 1659.210 985.530 ;
      RECT 1661.170 0.140 1661.450 985.530 ;
      RECT 1663.410 0.140 1663.690 985.530 ;
      RECT 1665.650 0.140 1665.930 985.530 ;
      RECT 1667.890 0.140 1668.170 985.530 ;
      RECT 1670.130 0.140 1670.410 985.530 ;
      RECT 1672.370 0.140 1672.650 985.530 ;
      RECT 1674.610 0.140 1674.890 985.530 ;
      RECT 1676.850 0.140 1677.130 985.530 ;
      RECT 1679.090 0.140 1679.370 985.530 ;
      RECT 1681.330 0.140 1681.610 985.530 ;
      RECT 1683.570 0.140 1683.850 985.530 ;
      RECT 1685.810 0.140 1686.090 985.530 ;
      RECT 1688.050 0.140 1688.330 985.530 ;
      RECT 1690.290 0.140 1690.570 985.530 ;
      RECT 1692.530 0.140 1692.810 985.530 ;
      RECT 1694.770 0.140 1695.050 985.530 ;
      RECT 1697.010 0.140 1697.290 985.530 ;
      RECT 1699.250 0.140 1699.530 985.530 ;
      RECT 1701.490 0.140 1701.770 985.530 ;
      RECT 1703.730 0.140 1704.010 985.530 ;
      RECT 1705.970 0.140 1706.250 985.530 ;
      RECT 1708.210 0.140 1708.490 985.530 ;
      RECT 1710.450 0.140 1710.730 985.530 ;
      RECT 1712.690 0.140 1712.970 985.530 ;
      RECT 1714.930 0.140 1715.210 985.530 ;
      RECT 1717.170 0.140 1717.450 985.530 ;
      RECT 1719.410 0.140 1719.690 985.530 ;
      RECT 1721.650 0.140 1721.930 985.530 ;
      RECT 1723.890 0.140 1724.170 985.530 ;
      RECT 1726.130 0.140 1726.410 985.530 ;
      RECT 1728.370 0.140 1728.650 985.530 ;
      RECT 1730.610 0.140 1730.890 985.530 ;
      RECT 1732.850 0.140 1733.130 985.530 ;
      RECT 1735.090 0.140 1735.370 985.530 ;
      RECT 1737.330 0.140 1737.610 985.530 ;
      RECT 1739.570 0.140 1739.850 985.530 ;
      RECT 1741.810 0.140 1742.090 985.530 ;
      RECT 1744.050 0.140 1744.330 985.530 ;
      RECT 1746.290 0.140 1746.570 985.530 ;
      RECT 1748.530 0.140 1748.810 985.530 ;
      RECT 1750.770 0.140 1751.050 985.530 ;
      RECT 1753.010 0.140 1753.290 985.530 ;
      RECT 1755.250 0.140 1755.530 985.530 ;
      RECT 1757.490 0.140 1757.770 985.530 ;
      RECT 1759.730 0.140 1760.010 985.530 ;
      RECT 1761.970 0.140 1762.250 985.530 ;
      RECT 1764.210 0.140 1764.490 985.530 ;
      RECT 1766.450 0.140 1766.730 985.530 ;
      RECT 1768.690 0.140 1768.970 985.530 ;
      RECT 1770.930 0.140 1771.210 985.530 ;
      RECT 1773.170 0.140 1773.450 985.530 ;
      RECT 1775.410 0.140 1775.690 985.530 ;
      RECT 1777.650 0.140 1777.930 985.530 ;
      RECT 1779.890 0.140 1780.170 985.530 ;
      RECT 1782.130 0.140 1782.410 985.530 ;
      RECT 1784.370 0.140 1784.650 985.530 ;
      RECT 1786.610 0.140 1786.890 985.530 ;
      RECT 1788.850 0.140 1789.130 985.530 ;
      RECT 1791.090 0.140 1791.370 985.530 ;
      RECT 1793.330 0.140 1793.610 985.530 ;
      RECT 1795.570 0.140 1795.850 985.530 ;
      RECT 1797.810 0.140 1798.090 985.530 ;
      RECT 1800.050 0.140 1800.330 985.530 ;
      RECT 1802.290 0.140 1802.570 985.530 ;
      RECT 1804.530 0.140 1804.810 985.530 ;
      RECT 1806.770 0.140 1807.050 985.530 ;
      RECT 1809.010 0.140 1809.290 985.530 ;
      RECT 1811.250 0.140 1811.530 985.530 ;
      RECT 1813.490 0.140 1813.770 985.530 ;
      RECT 1815.730 0.140 1816.010 985.530 ;
      RECT 1817.970 0.140 1818.250 985.530 ;
      RECT 1820.210 0.140 1820.490 985.530 ;
      RECT 1822.450 0.140 1822.730 985.530 ;
      RECT 1824.690 0.140 1824.970 985.530 ;
      RECT 1826.930 0.140 1827.210 985.530 ;
      RECT 1829.170 0.140 1829.450 985.530 ;
      RECT 1831.410 0.140 1831.690 985.530 ;
      RECT 1833.650 0.140 1833.930 985.530 ;
    END
  END VDD
  OBS
    LAYER metal1 ;
    RECT 0 0 1835.260 985.670 ;
    LAYER metal2 ;
    RECT 0 0 1835.260 985.670 ;
    LAYER metal3 ;
    RECT 0 0 1835.260 985.670 ;
    LAYER metal4 ;
    RECT 0 0 1835.260 985.670 ;
    LAYER OVERLAP ;
    RECT 0 0 1835.260 985.670 ;
  END
END fakeram_512x1024_1r1w

END LIBRARY
